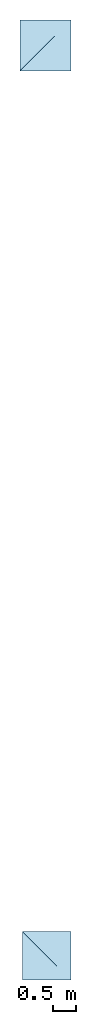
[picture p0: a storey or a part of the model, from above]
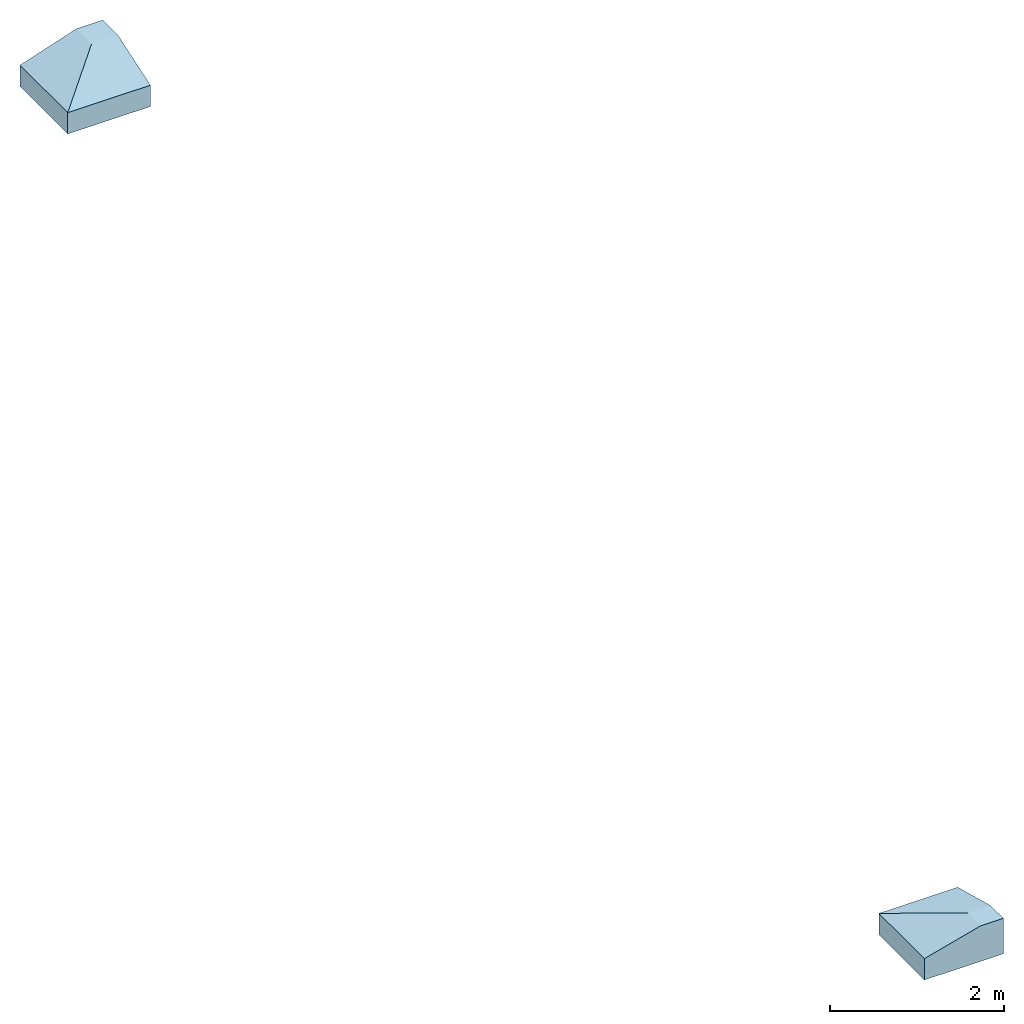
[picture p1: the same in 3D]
Properties of the parts of a building model (IFC4), part 1 of 4

# File
Description: IFC4
Time: 2026-02-24T17:23:19
Made in: IfcPlusPlus

# IfcBuildingStorey (8)
Name | LongName | Elevation (cm)
FUNDAÇÃO | FUNDAÇÃO | -295
FUNDO CISTERNA | FUNDO CISTERNA | -194
TÉRREO | TÉRREO | 10
PAVTO 01 | PAVTO 01 | 302
PAVTO 02 | PAVTO 02 | 604
COB CX DAGUA | COB CX DAGUA | 930
TELHADO CINE | TELHADO CINE | 1054
TELHADO ANEXO | TELHADO ANEXO | 1229

# IfcBeam (600)
Material: Concreto
Pset_ConcreteElementGeneral - ConcreteCover: 2.5 cm; ConstructionMethod: InSitu; ExposureClass: 2; StrengthClass: C-30
AltoQi_Eberick_Elemento - Elemento: Viga; Tipo: retangular
AltoQi_Eberick_Padrão - Ambiente: Interno; Cobrimento: 2.5 cm; Classe de concreto: C-30
AltoQi_Eberick-Itens_associados - Status: Dimensionado
AltoQi_Eberick_Cargas - Solo (S): 0; Acidental (Q): 0; Água (A): 0; Subpressão (AS): 0
Pset_BeamCommon - IsExternal: no; LoadBearing: yes
Name | In | Seção_bw (cm) | Seção_h (cm) | Elevação (cm) | Taxa de armadura | Concreto - C-30 - Abatimento 5 cm (m3) | Forma - Estrutura - Concreto (m2) | Armadura - Aço CA50 - ø 8.0 mm (kg) | Armadura - Aço CA60 - ø 5.0 mm (kg) | Cargas de parede (G2) | Adicional (G2) | Reference | Armadura - Aço CA50 - ø 10.0 mm (kg)
VB1 | TÉRREO | 12 | 30 | 0 | 0.28 % | 0.216781 | 4.33562 | 11.2677 | 5.2136 | 0 | 0 | Viga C-30 - Seção Retangular 12 X 30
VB10 | TÉRREO | 14 | 70 | -44 | 0.16 % | 0.279741 | 4.39592 |  | 3.23503 | 0 | 0 | Viga C-30 - Seção Retangular 14 X 70 | 9.00653 | AltoQi_Eberick-Itens_associados - Armadura - Aço CA50 - ø 6.3 mm: 7.07132 kg
VB10 | TÉRREO | 14 | 70 | -44 | 0.16 % | 0.279731 | 4.39578 |  | 3.23492 | 0 | 0 | Viga C-30 - Seção Retangular 14 X 70 | 9.00623 | AltoQi_Eberick-Itens_associados - Armadura - Aço CA50 - ø 6.3 mm: 7.07109 kg
VB11 | TÉRREO | 14 | 40 | -54 | 0.18 % | 0.040243 | 0.675506 | 1.52886 | 0.619849 | 0 | 0 | Viga C-30 - Seção Retangular 14 X 40
VB11 | TÉRREO | 14 | 40 | -54 | 0.18 % | 0.101426 | 1.70251 | 3.85326 | 1.56223 | 0 | 0 | Viga C-30 - Seção Retangular 14 X 40
VB12 | TÉRREO | 14 | 30 | -24 | 0.24 % | 0.147428 | 2.59755 | 6.66689 | 3.08068 | 408.48 | 0 | Viga C-30 - Seção Retangular 14 X 30
VB13 | TÉRREO | 14 | 30 | -24 | 0.24 % | 0.068809 | 1.21234 | 3.75013 | 1.47337 | 0 | 0 | Viga C-30 - Seção Retangular 14 X 30
VB14 | TÉRREO | 14 | 40 | -24 | 0.44 % | 0.178401 | 2.99458 |  | 2.5517 | 0 | 0 | Viga C-30 - Seção Retangular 14 X 40 | 8.53378 | AltoQi_Eberick-Itens_associados - Armadura - Aço CA50 - ø 12.5 mm: 7.90815 kg
VB14 | TÉRREO | 14 | 40 | -24 | 0.44 % | 0.079776 | 1.3391 |  | 1.14105 | 0 | 0 | Viga C-30 - Seção Retangular 14 X 40 | 3.81609 | AltoQi_Eberick-Itens_associados - Armadura - Aço CA50 - ø 12.5 mm: 3.53633 kg
VB15 | TÉRREO | 14 | 30 | -24 | 0.24 % | 0.07182 | 1.2654 | 3.76749 | 1.60731 | 0 | 0 | Viga C-30 - Seção Retangular 14 X 30
VB16 | TÉRREO | 14 | 40 | -24 | 0.18 % | 0.059025 | 0.990775 | 1.1063 | 0.888222 | 408.48 | 0 | Viga C-30 - Seção Retangular 14 X 40 | 1.80037 | AltoQi_Eberick-Itens_associados - Armadura - Aço CA50 - ø 6.3 mm: 1.31044 kg
VB16 | TÉRREO | 14 | 40 | -24 | 0.18 % | 0.074826 | 1.25601 | 1.40247 | 1.12601 | 0 | 0 | Viga C-30 - Seção Retangular 14 X 40 | 2.28234 | AltoQi_Eberick-Itens_associados - Armadura - Aço CA50 - ø 6.3 mm: 1.66125 kg
VB17 | TÉRREO | 14 | 30 | 21 | 0.24 % | 0.131065 | 2.30924 | 6.1634 | 2.8128 | 0 | 0 | Viga C-30 - Seção Retangular 14 X 30
VB18 | TÉRREO | 14 | 30 | -9 | 0.24 % | 0.154409 | 2.72054 | 7.13566 | 3.34857 | 0 | 0 | Viga C-30 - Seção Retangular 14 X 30
VB19 | TÉRREO | 14 | 50 | -24 | 0.14 % | 0.241591 | 3.93448 | 7.17038 | 2.82467 | 0 | 0 | Viga C-30 - Seção Retangular 14 X 50
VB2 | TÉRREO | 12 | 30 | 0 | 0.28 % | 0.119322 | 2.38644 | 6.49327 | 2.9247 | 0 | 0 | Viga C-30 - Seção Retangular 12 X 30
VB20 | TÉRREO | 14 | 60 | -24 | 0.19 % | 0.340091 | 5.42526 |  | 4.00641 | 0 | 0 | Viga C-30 - Seção Retangular 14 X 60 | 12.8314 | AltoQi_Eberick-Itens_associados - Armadura - Aço CA50 - ø 6.3 mm: 7.2677 kg
VB21 | TÉRREO | 14 | 95 | -24 | 0.18 % | 0.705073 | 10.8147 |  | 7.79581 | 0 | 0 | Viga C-30 - Seção Retangular 14 X 95 | 22.6584 | AltoQi_Eberick-Itens_associados - Armadura - Aço CA50 - ø 6.3 mm: 15.4775 kg
VB22 | TÉRREO | 14 | 40 | -54 | 0.18 % | 0.097296 | 1.63319 | 1.81966 | 1.41684 | 0 | 0 | Viga C-30 - Seção Retangular 14 X 40 | 3.08174 | AltoQi_Eberick-Itens_associados - Armadura - Aço CA50 - ø 6.3 mm: 2.2115 kg
VB22 | TÉRREO | 14 | 40 | -54 | 0.18 % | 0.041024 | 0.688612 | 0.767235 | 0.597391 | 0 | 0 | Viga C-30 - Seção Retangular 14 X 40 | 1.29938 | AltoQi_Eberick-Itens_associados - Armadura - Aço CA50 - ø 6.3 mm: 0.932451 kg
VB23 | TÉRREO | 15 | 30 | -24 | 0.35 % | 0.053107 | 0.857337 |  | 1.08502 | 0 | 0 | Viga C-30 - Seção Retangular 15 X 30 | 4.51755
VB23 | TÉRREO | 15 | 30 | -24 | 0.35 % | 0.054443 | 0.878913 |  | 1.11232 | 408.48 | 0 | Viga C-30 - Seção Retangular 15 X 30 | 4.63125
VB24 | TÉRREO | 15 | 30 | -24 | 0.22 % | 0.080253 | 1.33755 | 1.92715 | 1.648 | 408.48 | 0 | Viga C-30 - Seção Retangular 15 X 30 | 3.22819
VB25 | TÉRREO | 12 | 30 | 22 | 0.28 % | 0.216781 | 4.33562 | 11.1983 | 5.2136 | 0 | 0 | Viga C-30 - Seção Retangular 12 X 30
VB26 | TÉRREO | 12 | 30 | -24 | 0.44 % | 0.124247 | 2.48494 |  | 3.05186 | 0 | 0 | Viga C-30 - Seção Retangular 12 X 30 | 11.3665 | AltoQi_Eberick-Itens_associados - Armadura - Aço CA50 - ø 6.3 mm: 0.436062 kg
VB27 | TÉRREO | 12 | 30 | -24 | 0.44 % | 0.145294 | 2.90588 |  | 3.44934 | 0 | 0 | Viga C-30 - Seção Retangular 12 X 30 | 12.1345 | AltoQi_Eberick-Itens_associados - Armadura - Aço CA50 - ø 6.3 mm: 0.115966 kg
VB27 | TÉRREO | 12 | 30 | -24 | 0.44 % | 0.127877 | 2.55755 |  | 3.03586 | 0 | 0 | Viga C-30 - Seção Retangular 12 X 30 | 10.6799 | AltoQi_Eberick-Itens_associados - Armadura - Aço CA50 - ø 6.3 mm: 0.102065 kg
VB28 | TÉRREO | 12 | 30 | -34 | 0.28 % | 0.152348 | 3.04697 | 9.44476 | 3.68766 | 0 | 0 | Viga C-30 - Seção Retangular 12 X 30 | AltoQi_Eberick-Itens_associados - Armadura - Aço CA50 - ø 6.3 mm: 0.218031 kg
VB29 | TÉRREO | 12 | 30 | -24 | 0.28 % | 0.04334 | 0.841687 | 1.1818 | 1.05117 | 0 | 0 | Viga C-30 - Seção Retangular 12 X 30 | 1.82554
VB29 | TÉRREO | 12 | 30 | -24 | 0.28 % | 0.065104 | 1.26437 | 1.77528 | 1.57906 | 0 | 0 | Viga C-30 - Seção Retangular 12 X 30 | 2.7423
VB29 | TÉRREO | 12 | 30 | -24 | 0.28 % | 0.059326 | 1.15216 | 1.61773 | 1.43892 | 0 | 0 | Viga C-30 - Seção Retangular 12 X 30 | 2.49892
VB3 | TÉRREO | 12 | 30 | -44 | 0.28 % | 0.106154 | 2.12308 | 2.87826 | 2.57784 | 336.6 | 0 | Viga C-30 - Seção Retangular 12 X 30 | 4.39951
VB3 | TÉRREO | 12 | 30 | -44 | 0.28 % | 0.129484 | 2.58969 | 3.51085 | 3.1444 | 336.6 | 0 | Viga C-30 - Seção Retangular 12 X 30 | 5.36644
VB30 | TÉRREO | 12 | 30 | 0 | 0.28 % | 0.158047 | 3.15097 | 8.51487 | 3.81436 | 0 | 0 | Viga C-30 - Seção Retangular 12 X 30
VB30 | TÉRREO | 12 | 30 | 0 | 0.28 % | 0.116451 | 2.32168 | 6.27388 | 2.81048 | 0 | 0 | Viga C-30 - Seção Retangular 12 X 30
VB30 | TÉRREO | 12 | 30 | 0 | 0.28 % | 0.132981 | 2.65124 | 7.16444 | 3.20941 | 0 | 0 | Viga C-30 - Seção Retangular 12 X 30
VB30 | TÉRREO | 12 | 30 | 0 | 0.28 % | 0.151347 | 3.01739 | 8.15388 | 3.65265 | 0 | 0 | Viga C-30 - Seção Retangular 12 X 30
VB30 | TÉRREO | 12 | 30 | 0 | 0.28 % | 0.126128 | 2.5146 | 6.79521 | 3.04401 | 0 | 0 | Viga C-30 - Seção Retangular 12 X 30
VB31 | TÉRREO | 12 | 30 | 0 | 0.28 % | 0.083765 | 1.67529 | 4.86128 | 2.03457 | 0 | 0 | Viga C-30 - Seção Retangular 12 X 30
VB32 | TÉRREO | 12 | 30 | 41 | 0.28 % | 0.097128 | 1.94256 | 5.67727 | 2.2889 | 0 | 0 | Viga C-30 - Seção Retangular 12 X 30
VB33 | TÉRREO | 12 | 30 | 41 | 0.28 % | 0.068903 | 1.37806 | 3.80525 | 1.64145 | 0 | 0 | Viga C-30 - Seção Retangular 12 X 30
VB33 | TÉRREO | 12 | 30 | 41 | 0.28 % | 0.059172 | 1.18344 | 3.26784 | 1.40963 | 0 | 0 | Viga C-30 - Seção Retangular 12 X 30
VB33 | TÉRREO | 12 | 30 | 41 | 0.28 % | 0.068911 | 1.37822 | 3.80569 | 1.64164 | 0 | 0 | Viga C-30 - Seção Retangular 12 X 30
VB33 | TÉRREO | 12 | 30 | 41 | 0.28 % | 0.059229 | 1.18459 | 3.27101 | 1.411 | 0 | 0 | Viga C-30 - Seção Retangular 12 X 30
VB34 | TÉRREO | 15 | 40 | 0 | 0.17 % | 0.17229 | 2.72792 | 6.41949 | 2.39741 | 0 | 0 | Viga C-30 - Seção Retangular 15 X 40
VB35 | TÉRREO | 12 | 30 | -74 | 0.28 % | 0.111625 | 2.23251 | 7.68689 | 2.67038 | 0 | 0 | Viga C-30 - Seção Retangular 12 X 30
VB36 | TÉRREO | 14 | 30 | -54 | 0.24 % | 0.11424 | 2.0128 | 5.46025 | 2.41097 | 0 | 0 | Viga C-30 - Seção Retangular 14 X 30
VB37 | TÉRREO | 14 | 30 | -54 | 0.24 % | 0.11379 | 2.00488 | 5.44289 | 2.41097 | 0 | 0 | Viga C-30 - Seção Retangular 14 X 30
VB38 | TÉRREO | 14 | 40 | -24 | 0.42 % | 0.031679 | 0.546721 |  | 0.458247 | 0 | 0 | Viga C-30 - Seção Retangular 14 X 40 | 2.90532
VB38 | TÉRREO | 14 | 40 | -24 | 0.42 % | 0.107565 | 1.85639 |  | 1.55598 | 0 | 0 | Viga C-30 - Seção Retangular 14 X 40 | 9.86502
VB39 | TÉRREO | 14 | 30 | -24 | 0.36 % | 0.15181 | 2.67476 | 5.31238 | 3.28695 | 0 | 0 | Viga C-30 - Seção Retangular 14 X 30 | 5.49212
VB39 | TÉRREO | 14 | 30 | -24 | 0.36 % | 0.14513 | 2.55705 | 5.0786 | 3.1423 | 0 | 0 | Viga C-30 - Seção Retangular 14 X 30 | 5.25043
VB4 | TÉRREO | 12 | 30 | -54 | 0.28 % | 0.097362 | 1.94724 | 5.81617 | 2.41606 | 336.6 | 0 | Viga C-30 - Seção Retangular 12 X 30
VB40 | TÉRREO | 14 | 40 | -54 | 0.28 % | 0.02033 | 0.34898 |  | 0.295935 | 0 | 0 | Viga C-30 - Seção Retangular 14 X 40 | 1.2228 | AltoQi_Eberick-Itens_associados - Armadura - Aço CA50 - ø 6.3 mm: 0.474256 kg
VB40 | TÉRREO | 14 | 40 | -54 | 0.28 % | 0.152632 | 2.6201 |  | 2.22185 | 0 | 0 | Viga C-30 - Seção Retangular 14 X 40 | 9.18065 | AltoQi_Eberick-Itens_associados - Armadura - Aço CA50 - ø 6.3 mm: 3.56066 kg
VB41 | TÉRREO | 14 | 30 | -24 | 0.56 % | 0.121859 | 2.14704 |  | 2.67886 | 0 | 0 | Viga C-30 - Seção Retangular 14 X 30 | 12.2414
VB42 | TÉRREO | 15 | 30 | -24 | 0.22 % | 0.077861 | 1.29768 | 3.16325 | 1.85838 | 0 | 0 | Viga C-30 - Seção Retangular 15 X 30
VB42 | TÉRREO | 15 | 30 | -24 | 0.22 % | 0.076234 | 1.27056 | 3.09713 | 1.81954 | 0 | 0 | Viga C-30 - Seção Retangular 15 X 30
2 x VB42 | TÉRREO | 15 | 30 | -24 | 0.22 % |  | 0.058454 | 0.142489 | 0.083711 | 0 | 0 | Viga C-30 - Seção Retangular 15 X 30
VB43 | TÉRREO | 14 | 40 | -24 | 0.18 % | 0.257692 | 4.32554 | 8.47539 | 3.65879 | 408.48 | 0 | Viga C-30 - Seção Retangular 14 X 40
VB43 | TÉRREO | 14 | 40 | -24 | 0.18 % | 0.250654 | 4.20741 | 8.24393 | 3.55886 | 408.48 | 0 | Viga C-30 - Seção Retangular 14 X 40
VB44 | TÉRREO | 12 | 30 | -24 | 0.28 % | 0.0594 | 1.188 | 3.4463 | 1.39877 | 0 | 0 | Viga C-30 - Seção Retangular 12 X 30
VB45 | TÉRREO | 12 | 30 | -24 | 0.44 % | 0.112687 | 2.25374 |  | 2.67038 | 135.3 | 0 | Viga C-30 - Seção Retangular 12 X 30 | 10.2
VB46 | TÉRREO | 12 | 30 | -24 | 0.44 % | 0.105919 | 2.1075 |  | 2.57972 | 303.6 | 0 | Viga C-30 - Seção Retangular 12 X 30 | 9.91784
VB46 | TÉRREO | 12 | 30 | -24 | 0.44 % | 0.030916 | 0.615149 |  | 0.752985 | 303.6 | 0 | Viga C-30 - Seção Retangular 12 X 30 | 2.89488
VB46 | TÉRREO | 12 | 30 | -24 | 0.44 % | 0.123378 | 2.4549 |  | 3.00497 | 303.6 | 0 | Viga C-30 - Seção Retangular 12 X 30 | 11.5527
VB46 | TÉRREO | 12 | 30 | -24 | 0.44 % | 0.082068 | 1.63292 |  | 1.99881 | 303.6 | 0 | Viga C-30 - Seção Retangular 12 X 30 | 7.68451
VB46 | TÉRREO | 12 | 30 | -24 | 0.44 % | 0.069417 | 1.38122 |  | 1.6907 | 303.6 | 0 | Viga C-30 - Seção Retangular 12 X 30 | 6.49997
VB46 | TÉRREO | 12 | 30 | -24 | 0.44 % | 0.079075 | 1.57339 |  | 1.92593 | 303.6 | 0 | Viga C-30 - Seção Retangular 12 X 30 | 7.40433
VB5 | TÉRREO | 12 | 30 | -24 | 0.28 % | 0.164811 | 3.29623 | 4.45672 | 3.94664 | 303.6 | 0 | Viga C-30 - Seção Retangular 12 X 30 | 6.91101
VB5 | TÉRREO | 12 | 30 | -24 | 0.28 % | 0.09008 | 1.80159 | 2.43587 | 2.15708 | 303.6 | 0 | Viga C-30 - Seção Retangular 12 X 30 | 3.77729
VB6 | TÉRREO | 14 | 30 | 0 | 0.24 % | 0.139403 | 2.45615 | 6.30327 | 3.04343 | 0 | 0 | Viga C-30 - Seção Retangular 14 X 30
VB6 | TÉRREO | 14 | 30 | 0 | 0.24 % | 0.142816 | 2.51628 | 6.45758 | 3.11794 | 0 | 0 | Viga C-30 - Seção Retangular 14 X 30
VB7 | TÉRREO | 12 | 30 | 0 | 0.28 % | 0.042192 | 0.84384 | 2.80391 | 1.01729 | 0 | 0 | Viga C-30 - Seção Retangular 12 X 30
VB8 | TÉRREO | 14 | 50 | 0 | 0.14 % | 0.233016 | 3.79483 | 6.96204 | 2.82467 | 0 | 0 | Viga C-30 - Seção Retangular 14 X 50
VB9 | TÉRREO | 14 | 50 | -44 | 0.14 % | 0.254877 | 4.15085 | 7.50025 | 3.02643 | 0 | 0 | Viga C-30 - Seção Retangular 14 X 50
V101 | PAVTO 01 | 15 | 40 | 0 | 0.17 % | 0.361302 | 5.72061 | 11.4587 | 4.96606 | 0 | 0 | Viga C-30 - Seção Retangular 15 X 40
V102 | PAVTO 01 | 15 | 40 | 0 | 0.17 % | 0.199745 | 3.16262 | 6.39469 | 2.74602 | 0 | 0 | Viga C-30 - Seção Retangular 15 X 40
V102 | PAVTO 01 | 15 | 40 | 0 | 0.17 % | 0.198853 | 3.14851 | 6.36615 | 2.73377 | 0 | 0 | Viga C-30 - Seção Retangular 15 X 40
V103 | PAVTO 01 | 15 | 40 | 0 | 0.26 % | 0.149621 | 2.06976 |  | 2.08557 | 224.4 | 0 | Viga C-30 - Seção Retangular 15 X 40 | 8.5023
V103 | PAVTO 01 | 15 | 40 | 0 | 0.26 % | 0.215643 | 2.98306 |  | 3.00584 | 224.4 | 0 | Viga C-30 - Seção Retangular 15 X 40 | 12.254
V103 | PAVTO 01 | 15 | 40 | 0 | 0.26 % | 0.275177 | 3.80662 |  | 3.83569 | 224.4 | 0 | Viga C-30 - Seção Retangular 15 X 40 | 15.6371
V103 | PAVTO 01 | 15 | 40 | 0 | 0.26 % | 0.165588 | 2.29063 |  | 2.30812 | 224.4 | 0 | Viga C-30 - Seção Retangular 15 X 40 | 9.4096
V103 | PAVTO 01 | 15 | 40 | 0 | 0.26 % | 0.176788 | 2.44557 |  | 2.46425 | 224.4 | 0 | Viga C-30 - Seção Retangular 15 X 40 | 10.0461
V104 | PAVTO 01 | 15 | 40 | 0 | 0.17 % | 0.171791 | 2.53504 | 2.77229 | 2.41004 | 0 | 0 | Viga C-30 - Seção Retangular 15 X 40 | 4.53598
V104 | PAVTO 01 | 15 | 40 | 0 | 0.17 % | 0.202725 | 2.99152 | 3.27149 | 2.84402 | 0 | 0 | Viga C-30 - Seção Retangular 15 X 40 | 5.35276
V104 | PAVTO 01 | 15 | 40 | 0 | 0.17 % | 0.197635 | 2.91642 | 3.18936 | 2.77262 | 0 | 0 | Viga C-30 - Seção Retangular 15 X 40 | 5.21838
V104 | PAVTO 01 | 15 | 40 | 0 | 0.17 % | 0.198617 | 2.9309 | 3.2052 | 2.78639 | 0 | 0 | Viga C-30 - Seção Retangular 15 X 40 | 5.2443
V104 | PAVTO 01 | 15 | 40 | 0 | 0.17 % | 0.171762 | 2.53461 | 2.77183 | 2.40964 | 0 | 0 | Viga C-30 - Seção Retangular 15 X 40 | 4.53522
V104 | PAVTO 01 | 15 | 40 | 0 | 0.17 % | 0.21602 | 3.18771 | 3.48604 | 3.03053 | 0 | 0 | Viga C-30 - Seção Retangular 15 X 40 | 5.70381
V104 | PAVTO 01 | 15 | 40 | 0 | 0.17 % | 0.042757 | 0.630947 | 0.689997 | 0.599838 | 0 | 0 | Viga C-30 - Seção Retangular 15 X 40 | 1.12896
V104 | PAVTO 01 | 15 | 40 | 0 | 0.17 % | 0.10478 | 1.54618 | 1.69089 | 1.46995 | 0 | 0 | Viga C-30 - Seção Retangular 15 X 40 | 2.76661
V105 | PAVTO 01 | 15 | 35 | 0 | 0.70 % | 0.244666 | 2.84278 |  | 4.16579 | 0 | 0 | Viga C-30 - Seção Retangular 15 X 35 | AltoQi_Eberick-Itens_associados - Armadura - Aço CA50 - ø 12.5 mm: 14.5281 kg; Armadura - Aço CA50 - ø 16.0 mm: 26.6849 kg
V106 | PAVTO 01 | 15 | 40 | 0 | 0.17 % | 0.07032 | 1.1134 | 2.89072 | 1.02746 | 0 | 0 | Viga C-30 - Seção Retangular 15 X 40
V107 | PAVTO 01 | 20 | 40 | 0 | 0.20 % | 0.379976 | 4.7497 |  | 5.26955 | 207.2 | 0 | Viga C-30 - Seção Retangular 20 X 40 | 14.8524
V108 | PAVTO 01 | 15 | 30 | 0 | 0.22 % | 0.073724 | 1.22873 | 1.90979 | 1.648 | 0 | 0 | Viga C-30 - Seção Retangular 15 X 30 | 3.77753
V109 | PAVTO 01 | 15 | 35 | 0 | 0.75 % | 0.244666 | 2.84278 |  | 4.47437 | 0 | 0 | Viga C-30 - Seção Retangular 15 X 35 | 14.8524 | AltoQi_Eberick-Itens_associados - Armadura - Aço CA50 - ø 16.0 mm: 26.2509 kg
V110 | PAVTO 01 | 15 | 35 | 0 | 0.57 % | 0.244666 | 2.84278 | 11.6497 | 4.16579 | 0 | 0 | Viga C-30 - Seção Retangular 15 X 35 | 22.6991
V111 | PAVTO 01 | 15 | 40 | 0 | 0.61 % | 0.147717 | 1.74798 | 1.5977 | 2.04773 | 204.15 | 0 | Viga C-30 - Seção Retangular 15 X 40 | AltoQi_Eberick-Itens_associados - Armadura - Aço CA50 - ø 6.3 mm: 2.84932 kg; Armadura - Aço CA50 - ø 12.5 mm: 7.73517 kg; Armadura - Aço CA50 - ø 16.0 mm: 4.20638 kg
V111 | PAVTO 01 | 15 | 40 | 0 | 0.61 % | 0.136401 | 1.61408 | 1.47532 | 1.89087 | 286 | 0 | Viga C-30 - Seção Retangular 15 X 40 | AltoQi_Eberick-Itens_associados - Armadura - Aço CA50 - ø 6.3 mm: 2.63106 kg; Armadura - Aço CA50 - ø 12.5 mm: 7.14265 kg; Armadura - Aço CA50 - ø 16.0 mm: 3.88417 kg
V112 | PAVTO 01 | 15 | 30 | 0 | 0.22 % | 0.021466 | 0.314424 | 0.525492 | 0.459729 | 0 | 0 | Viga C-30 - Seção Retangular 15 X 30 | 0.862702
V112 | PAVTO 01 | 15 | 30 | 0 | 0.22 % | 0.055484 | 0.8127 | 1.35825 | 1.18827 | 0 | 0 | Viga C-30 - Seção Retangular 15 X 30 | 2.22985
V113 | PAVTO 01 | 15 | 30 | 0 | 0.22 % | 0.044265 | 0.555546 | 0.982881 | 0.893648 | 286 | 0 | Viga C-30 - Seção Retangular 15 X 30 | 1.55046
V113 | PAVTO 01 | 15 | 30 | 0 | 0.22 % | 0.063384 | 0.7955 | 1.40741 | 1.27964 | 0 | 0 | Viga C-30 - Seção Retangular 15 X 30 | 2.22014
V113 | PAVTO 01 | 15 | 30 | 0 | 0.22 % | 0.096426 | 1.2102 | 2.14111 | 1.94673 | 123.2 | 0 | Viga C-30 - Seção Retangular 15 X 30 | 3.37753
V114 | PAVTO 01 | 15 | 40 | 0 | 0.39 % | 0.368802 | 5.10176 |  | 4.96606 | 0 | 0 | Viga C-30 - Seção Retangular 15 X 40 | 11.2444 | AltoQi_Eberick-Itens_associados - Armadura - Aço CA50 - ø 12.5 mm: 17.3045 kg
V115 | PAVTO 01 | 15 | 40 | 0 | 0.26 % | 0.241621 | 3.36514 |  | 3.43732 | 0 | 0 | Viga C-30 - Seção Retangular 15 X 40 | 13.4535 | AltoQi_Eberick-Itens_associados - Armadura - Aço CA50 - ø 6.3 mm: 0.565848 kg
2 x V115 | PAVTO 01 | 15 | 40 | 0 | 0.26 % | 0.086831 | 1.20932 |  | 1.23526 | 0 | 0 | Viga C-30 - Seção Retangular 15 X 40 | 4.83475 | AltoQi_Eberick-Itens_associados - Armadura - Aço CA50 - ø 6.3 mm: 0.203347 kg
V115 | PAVTO 01 | 15 | 40 | 0 | 0.26 % | 0.133791 | 1.86335 |  | 1.90332 | 0 | 0 | Viga C-30 - Seção Retangular 15 X 40 | 7.4495 | AltoQi_Eberick-Itens_associados - Armadura - Aço CA50 - ø 6.3 mm: 0.313322 kg
V115 | PAVTO 01 | 15 | 40 | 0 | 0.26 % | 0.207647 | 2.89198 |  | 2.95401 | 0 | 0 | Viga C-30 - Seção Retangular 15 X 40 | 11.5619 | AltoQi_Eberick-Itens_associados - Armadura - Aço CA50 - ø 6.3 mm: 0.486286 kg
V115 | PAVTO 01 | 15 | 40 | 0 | 0.26 % | 0.188855 | 2.63025 |  | 2.68667 | 0 | 0 | Viga C-30 - Seção Retangular 15 X 40 | 10.5155 | AltoQi_Eberick-Itens_associados - Armadura - Aço CA50 - ø 6.3 mm: 0.442277 kg
V115 | PAVTO 01 | 15 | 40 | 0 | 0.26 % | 0.0779 | 1.08494 |  | 1.10821 | 0 | 0 | Viga C-30 - Seção Retangular 15 X 40 | 4.33748 | AltoQi_Eberick-Itens_associados - Armadura - Aço CA50 - ø 6.3 mm: 0.182432 kg
V115 | PAVTO 01 | 15 | 40 | 0 | 0.26 % | 0.044846 | 0.624583 |  | 0.63798 | 0 | 0 | Viga C-30 - Seção Retangular 15 X 40 | 2.49702 | AltoQi_Eberick-Itens_associados - Armadura - Aço CA50 - ø 6.3 mm: 0.105024 kg
V115 | PAVTO 01 | 15 | 40 | 0 | 0.26 % | 0.22617 | 3.14995 |  | 3.21752 | 0 | 0 | Viga C-30 - Seção Retangular 15 X 40 | 12.5932 | AltoQi_Eberick-Itens_associados - Armadura - Aço CA50 - ø 6.3 mm: 0.529664 kg
V115 | PAVTO 01 | 15 | 40 | 0 | 0.26 % | 0.029608 | 0.41236 |  | 0.421205 | 0 | 0 | Viga C-30 - Seção Retangular 15 X 40 | 1.64858 | AltoQi_Eberick-Itens_associados - Armadura - Aço CA50 - ø 6.3 mm: 0.069338 kg
V116 | PAVTO 01 | 15 | 40 | 0 | 0.26 % | 0.07176 | 1.009 |  | 1.04442 | 387.76 | 0 | Viga C-30 - Seção Retangular 15 X 40 | 3.83779
V116 | PAVTO 01 | 15 | 40 | 0 | 0.26 % | 0.069625 | 0.978974 |  | 1.01334 | 0 | 0 | Viga C-30 - Seção Retangular 15 X 40 | 3.72359
V116 | PAVTO 01 | 15 | 40 | 0 | 0.26 % | 0.129228 | 1.81704 |  | 1.88083 | 123.2 | 0 | Viga C-30 - Seção Retangular 15 X 40 | 6.91122
V117 | PAVTO 01 | 15 | 40 | 0 | 0.17 % | 0.099 | 1.3695 | 3.39421 | 1.1987 | 387.76 | 0 | Viga C-30 - Seção Retangular 15 X 40
V118 | PAVTO 01 | 15 | 40 | 0 | 0.17 % | 0.099 | 1.3695 | 3.39421 | 1.1987 | 387.76 | 0 | Viga C-30 - Seção Retangular 15 X 40
V119 | PAVTO 01 | 15 | 40 | 0 | 0.26 % | 0.056603 | 0.772551 |  | 0.782032 | 0 | 0 | Viga C-30 - Seção Retangular 15 X 40 | 2.89481
V119 | PAVTO 01 | 15 | 40 | 0 | 0.26 % | 0.11278 | 1.5393 |  | 1.55819 | 387.76 | 0 | Viga C-30 - Seção Retangular 15 X 40 | 5.76788
V119 | PAVTO 01 | 15 | 40 | 0 | 0.26 % | 0.016533 | 0.225656 |  | 0.228426 | 0 | 0 | Viga C-30 - Seção Retangular 15 X 40 | 0.845553
V120 | PAVTO 01 | 13 | 30 | 0 | 0.26 % | 0.019781 | 0.309392 | 1.38026 | 0.391655 | 131 | 0 | Viga C-30 - Seção Retangular 13 X 30
V121 | PAVTO 01 | 15 | 40 | 0 | 0.39 % | 0.336717 | 4.69339 |  | 4.62813 | 0 | 0 | Viga C-30 - Seção Retangular 15 X 40 | 23.3729
V121 | PAVTO 01 | 15 | 40 | 0 | 0.39 % | 0.024585 | 0.342688 |  | 0.337923 | 0 | 0 | Viga C-30 - Seção Retangular 15 X 40 | 1.70657
V122 | PAVTO 01 | 15 | 40 | 0 | 0.17 % | 0.086522 | 1.23098 | 1.36317 | 1.20478 | 0 | 0 | Viga C-30 - Seção Retangular 15 X 40 | 2.21202
V122 | PAVTO 01 | 15 | 40 | 0 | 0.17 % | 0.133249 | 1.89577 | 2.09936 | 1.85543 | 0 | 0 | Viga C-30 - Seção Retangular 15 X 40 | 3.40664
V122 | PAVTO 01 | 15 | 40 | 0 | 0.17 % | 0.206909 | 2.94376 | 3.25989 | 2.88112 | 0 | 0 | Viga C-30 - Seção Retangular 15 X 40 | 5.28984
V122 | PAVTO 01 | 15 | 40 | 0 | 0.17 % | 0.188217 | 2.67783 | 2.9654 | 2.62084 | 0 | 0 | Viga C-30 - Seção Retangular 15 X 40 | 4.81197
V123 | PAVTO 01 | 15 | 40 | 0 | 0.17 % | 0.242922 | 3.36042 | 3.95847 | 3.42487 | 0 | 0 | Viga C-30 - Seção Retangular 15 X 40 | 7.67034
V124 | PAVTO 01 | 15 | 40 | 0 | 0.17 % | 0.125743 | 1.88288 | 2.08171 | 1.72372 | 0 | 0 | Viga C-30 - Seção Retangular 15 X 40 | 4.24855
V124 | PAVTO 01 | 15 | 40 | 0 | 0.17 % | 0.086621 | 1.29707 | 1.43403 | 1.18742 | 0 | 0 | Viga C-30 - Seção Retangular 15 X 40 | 2.92671
V125 | PAVTO 01 | 15 | 40 | 0 | 0.17 % | 0.224133 | 3.31704 | 3.53735 | 3.16527 | 0 | 0 | Viga C-30 - Seção Retangular 15 X 40 | 7.07699
V125 | PAVTO 01 | 15 | 40 | 0 | 0.17 % | 0.252968 | 3.74379 | 3.99245 | 3.57249 | 0 | 0 | Viga C-30 - Seção Retangular 15 X 40 | 7.98746
V125 | PAVTO 01 | 15 | 40 | 0 | 0.17 % | 0.056431 | 0.835152 | 0.890622 | 0.796941 | 0 | 0 | Viga C-30 - Seção Retangular 15 X 40 | 1.78182
V126 | PAVTO 01 | 13 | 30 | 0 | 0.26 % | 0.0156 | 0.244 | 1.43234 | 0.522207 | 131 | 0 | Viga C-30 - Seção Retangular 13 X 30
V127 | PAVTO 01 | 15 | 40 | 0 | 0.17 % | 0.251313 | 3.89677 | 4.64188 | 5.31541 | 0 | 0 | Viga C-30 - Seção Retangular 15 X 40 | 6.85729 | AltoQi_Eberick-Itens_associados - Armadura - Aço CA50 - ø 6.3 mm: 0.858037 kg
V127 | PAVTO 01 | 15 | 40 | 0 | 0.17 % | 0.221573 | 3.43564 | 4.09258 | 4.68641 | 0 | 0 | Viga C-30 - Seção Retangular 15 X 40 | 6.04583 | AltoQi_Eberick-Itens_associados - Armadura - Aço CA50 - ø 6.3 mm: 0.756501 kg
V127 | PAVTO 01 | 15 | 40 | 0 | 0.34 % | 0.022159 | 0.343591 | 0.40929 | 0.468678 | 0 | 0 | Viga C-30 - Seção Retangular 15 X 40 | 0.604631 | AltoQi_Eberick-Itens_associados - Armadura - Aço CA50 - ø 6.3 mm: 0.075656 kg
V127 | PAVTO 01 | 15 | 40 | 0 | 0.17 % | 0.263338 | 4.08323 | 4.864 | 5.56976 | 0 | 0 | Viga C-30 - Seção Retangular 15 X 40 | 7.18542 | AltoQi_Eberick-Itens_associados - Armadura - Aço CA50 - ø 6.3 mm: 0.899095 kg
V127 | PAVTO 01 | 15 | 40 | 0 | 0.17 % | 0.210998 | 3.27166 | 3.89724 | 4.46273 | 0 | 0 | Viga C-30 - Seção Retangular 15 X 40 | 5.75726 | AltoQi_Eberick-Itens_associados - Armadura - Aço CA50 - ø 6.3 mm: 0.720393 kg
V127 | PAVTO 01 | 15 | 40 | 0 | 0.34 % | 0.143087 | 2.21866 | 2.64289 | 3.02637 | 0 | 0 | Viga C-30 - Seção Retangular 15 X 40 | 3.90426 | AltoQi_Eberick-Itens_associados - Armadura - Aço CA50 - ø 6.3 mm: 0.48853 kg
V127 | PAVTO 01 | 15 | 40 | 0 | 0.34 % | 0.029122 | 0.451561 | 0.537905 | 0.615955 | 0 | 0 | Viga C-30 - Seção Retangular 15 X 40 | 0.794629 | AltoQi_Eberick-Itens_associados - Armadura - Aço CA50 - ø 6.3 mm: 0.09943 kg
V128 | PAVTO 01 | 20 | 40 | 0 | 0.20 % | 0.186144 | 2.3268 |  | 2.63477 | 207.2 | 0 | Viga C-30 - Seção Retangular 20 X 40 | 8.1383
V129 | PAVTO 01 | 15 | 40 | 0 | 0.17 % | 0.167748 | 1.98502 | 3.17719 | 2.39741 | 0 | 0 | Viga C-30 - Seção Retangular 15 X 40 | 4.74734 | AltoQi_Eberick-Itens_associados - Armadura - Aço CA50 - ø 6.3 mm: 0.360693 kg
V130 | PAVTO 01 | 15 | 30 | 0 | 0.22 % | 0.12141 | 2.0235 | 5.82485 | 2.47201 | 0 | 0 | Viga C-30 - Seção Retangular 15 X 30 | AltoQi_Eberick-Itens_associados - Armadura - Aço CA50 - ø 6.3 mm: 0.279941 kg
V131 | PAVTO 01 | 15 | 40 | 10 | 0.17 % | 0.114838 | 1.81828 | 2.21895 | 1.65786 | 0 | 0 | Viga C-30 - Seção Retangular 15 X 40 | 3.01297 | AltoQi_Eberick-Itens_associados - Armadura - Aço CA50 - ø 6.3 mm: 0.060806 kg
V131 | PAVTO 01 | 15 | 40 | 10 | 0.17 % | 0.098716 | 1.563 | 1.90742 | 1.42511 | 0 | 0 | Viga C-30 - Seção Retangular 15 X 40 | 2.58997 | AltoQi_Eberick-Itens_associados - Armadura - Aço CA50 - ø 6.3 mm: 0.052269 kg
V131 | PAVTO 01 | 15 | 40 | 10 | 0.17 % | 0.09862 | 1.56149 | 1.90557 | 1.42373 | 0 | 0 | Viga C-30 - Seção Retangular 15 X 40 | 2.58746 | AltoQi_Eberick-Itens_associados - Armadura - Aço CA50 - ø 6.3 mm: 0.052218 kg
V131 | PAVTO 01 | 15 | 40 | 10 | 0.25 % | 0.114852 | 1.81849 | 2.21921 | 1.65806 | 0 | 0 | Viga C-30 - Seção Retangular 15 X 40 | 3.01332 | AltoQi_Eberick-Itens_associados - Armadura - Aço CA50 - ø 6.3 mm: 0.060813 kg
V132 | PAVTO 01 | 15 | 40 | 0 | 0.17 % | 0.17229 | 2.72792 | 5.97242 | 2.39741 | 0 | 0 | Viga C-30 - Seção Retangular 15 X 40
V133 | PAVTO 01 | 15 | 40 | 0 | 0.17 % | 0.088739 | 1.1058 | 3.02973 | 1.24513 | 387.76 | 0 | Viga C-30 - Seção Retangular 15 X 40
V133 | PAVTO 01 | 15 | 40 | 0 | 0.17 % | 0.094327 | 1.17543 | 3.22049 | 1.32352 | 0 | 0 | Viga C-30 - Seção Retangular 15 X 40
V134 | PAVTO 01 | 15 | 40 | 0 | 0.17 % | 0.094201 | 1.17386 | 1.67957 | 1.32176 | 0 | 0 | Viga C-30 - Seção Retangular 15 X 40 | 2.64527
V134 | PAVTO 01 | 15 | 40 | 0 | 0.17 % | 0.088865 | 1.10737 | 1.58443 | 1.24689 | 387.76 | 0 | Viga C-30 - Seção Retangular 15 X 40 | 2.49542
V135 | PAVTO 01 | 15 | 40 | 0 | 0.25 % | 0.183066 | 2.16628 | 4.896 | 2.56865 | 0 | 0 | Viga C-30 - Seção Retangular 15 X 40 | 4.88298
V136 | PAVTO 01 | 15 | 40 | 0 | 0.17 % | 0.188022 | 2.60097 | 3.50706 | 2.56865 | 275 | 0 | Viga C-30 - Seção Retangular 15 X 40 | 5.26276
V137 | PAVTO 01 | 15 | 40 | 0 | 0.17 % | 0.180042 | 2.1305 | 3.3074 | 2.56865 | 0 | 0 | Viga C-30 - Seção Retangular 15 X 40 | 5.18138
V138 | PAVTO 01 | 15 | 40 | 0 | 0.17 % | 0.088865 | 1.10737 | 1.58443 | 1.24689 | 387.76 | 0 | Viga C-30 - Seção Retangular 15 X 40 | 2.43617
V138 | PAVTO 01 | 15 | 40 | 0 | 0.17 % | 0.094201 | 1.17386 | 1.67957 | 1.32176 | 0 | 0 | Viga C-30 - Seção Retangular 15 X 40 | 2.58245
V139 | PAVTO 01 | 15 | 40 | 0 | 0.17 % | 0.096088 | 1.20713 | 3.26492 | 1.38135 | 387.76 | 0 | Viga C-30 - Seção Retangular 15 X 40
V139 | PAVTO 01 | 15 | 40 | 0 | 0.17 % | 0.094501 | 1.18719 | 3.21099 | 1.35854 | 0 | 0 | Viga C-30 - Seção Retangular 15 X 40
V140 | PAVTO 01 | 15 | 40 | 0 | 0.26 % | 0.186042 | 2.2015 |  | 2.56865 | 0 | 0 | Viga C-30 - Seção Retangular 15 X 40 | 11.7395
V141 | PAVTO 01 | 15 | 40 | 0 | 0.17 % | 0.180042 | 2.1305 | 3.22059 | 2.56865 | 0 | 0 | Viga C-30 - Seção Retangular 15 X 40 | 6.09016
V142 | PAVTO 01 | 15 | 30 | 0 | 0.22 % | 0.120023 | 1.7245 | 5.28575 | 2.3824 | 0 | 0 | Viga C-30 - Seção Retangular 15 X 30
V142 | PAVTO 01 | 15 | 30 | 0 | 0.22 % | 0.018352 | 0.263682 | 0.808211 | 0.364278 | 0 | 0 | Viga C-30 - Seção Retangular 15 X 30
V143 | PAVTO 01 | 15 | 30 | 0 | 0.22 % | 0.137862 | 2.2977 | 6.07659 | 2.74668 | 0 | 0 | Viga C-30 - Seção Retangular 15 X 30
V144 | PAVTO 01 | 15 | 30 | 0 | 0.22 % | 0.019098 | 0.274051 | 0.815033 | 0.378178 | 0 | 0 | Viga C-30 - Seção Retangular 15 X 30
V144 | PAVTO 01 | 15 | 30 | 0 | 0.22 % | 0.126545 | 1.81587 | 5.40046 | 2.50583 | 0 | 0 | Viga C-30 - Seção Retangular 15 X 30
V145 | PAVTO 01 | 15 | 40 | 0 | 0.26 % | 0.037163 | 0.488802 |  | 0.59811 | 0 | 0 | Viga C-30 - Seção Retangular 15 X 40 | 2.06595 | AltoQi_Eberick-Itens_associados - Armadura - Aço CA50 - ø 6.3 mm: 0.252246 kg
V145 | PAVTO 01 | 15 | 40 | 0 | 0.26 % | 0.204296 | 2.68707 |  | 3.28796 | 0 | 0 | Viga C-30 - Seção Retangular 15 X 40 | 11.3571 | AltoQi_Eberick-Itens_associados - Armadura - Aço CA50 - ø 6.3 mm: 1.38666 kg
V145 | PAVTO 01 | 15 | 40 | 0 | 0.26 % | 0.079191 | 1.04158 |  | 1.2745 | 0 | 0 | Viga C-30 - Seção Retangular 15 X 40 | 4.40229 | AltoQi_Eberick-Itens_associados - Armadura - Aço CA50 - ø 6.3 mm: 0.537506 kg
V145 | PAVTO 01 | 15 | 40 | 0 | 0.26 % | 0.119414 | 1.57063 |  | 1.92186 | 288.2 | 0 | Viga C-30 - Seção Retangular 15 X 40 | 6.63838 | AltoQi_Eberick-Itens_associados - Armadura - Aço CA50 - ø 6.3 mm: 0.810524 kg
V145 | PAVTO 01 | 15 | 40 | 0 | 0.26 % | 0.085595 | 1.12581 |  | 1.37757 | 0 | 0 | Viga C-30 - Seção Retangular 15 X 40 | 4.7583 | AltoQi_Eberick-Itens_associados - Armadura - Aço CA50 - ø 6.3 mm: 0.580973 kg
V145 | PAVTO 01 | 15 | 40 | 0 | 0.26 % | 0.134568 | 1.76995 |  | 2.16574 | 0 | 0 | Viga C-30 - Seção Retangular 15 X 40 | 7.48078 | AltoQi_Eberick-Itens_associados - Armadura - Aço CA50 - ø 6.3 mm: 0.913379 kg
V145 | PAVTO 01 | 15 | 40 | 0 | 0.26 % | 0.13053 | 1.71684 |  | 2.10077 | 0 | 0 | Viga C-30 - Seção Retangular 15 X 40 | 7.25634 | AltoQi_Eberick-Itens_associados - Armadura - Aço CA50 - ø 6.3 mm: 0.885974 kg
V145 | PAVTO 01 | 15 | 40 | 0 | 0.26 % | 0.098077 | 1.28999 |  | 1.57846 | 0 | 0 | Viga C-30 - Seção Retangular 15 X 40 | 5.45223 | AltoQi_Eberick-Itens_associados - Armadura - Aço CA50 - ø 6.3 mm: 0.665699 kg
V145 | PAVTO 01 | 15 | 40 | 0 | 0.26 % | 0.181581 | 2.38829 |  | 2.92237 | 0 | 0 | Viga C-30 - Seção Retangular 15 X 40 | 10.0943 | AltoQi_Eberick-Itens_associados - Armadura - Aço CA50 - ø 6.3 mm: 1.23248 kg
V145 | PAVTO 01 | 15 | 40 | 0 | 0.26 % | 0.05744 | 0.755502 |  | 0.924449 | 0 | 0 | Viga C-30 - Seção Retangular 15 X 40 | 3.19318 | AltoQi_Eberick-Itens_associados - Armadura - Aço CA50 - ø 6.3 mm: 0.389876 kg
V146 | PAVTO 01 | 15 | 40 | 0 | 0.17 % | 0.0945 | 1.13543 | 3.39737 | 1.30768 | 0 | 0 | Viga C-30 - Seção Retangular 15 X 40
V146 | PAVTO 01 | 15 | 40 | 0 | 0.17 % |  | 0.054068 | 0.161779 | 0.06227 | 0 | 0 | Viga C-30 - Seção Retangular 15 X 40
2 x V147 | PAVTO 01 | 15 | 40 | 0 | 0.17 % |  | 0.059254 | 0.159456 | 0.057716 | 0 | 0 | Viga C-30 - Seção Retangular 15 X 40
V147 | PAVTO 01 | 15 | 40 | 0 | 0.17 % | 0.106054 | 1.28794 | 3.46594 | 1.25451 | 0 | 0 | Viga C-30 - Seção Retangular 15 X 40
V148 | PAVTO 01 | 15 | 30 | 0 | 0.22 % | 0.088896 | 1.12826 | 1.95861 | 1.96527 | 183.67 | 0 | Viga C-30 - Seção Retangular 15 X 30 | 4.45462
V148 | PAVTO 01 | 15 | 30 | 0 | 0.22 % | 0.097467 | 1.23703 | 2.14743 | 2.15474 | 132.56 | 0 | Viga C-30 - Seção Retangular 15 X 30 | 4.88408
V149 | PAVTO 01 | 15 | 40 | 0 | 0.17 % | 0.207082 | 2.92066 | 3.36997 | 2.92414 | 288.2 | 0 | Viga C-30 - Seção Retangular 15 X 40 | 5.27437 | AltoQi_Eberick-Itens_associados - Armadura - Aço CA50 - ø 6.3 mm: 0.048873 kg
V149 | PAVTO 01 | 15 | 40 | 0 | 0.17 % | 0.184057 | 2.59591 | 2.99526 | 2.599 | 288.2 | 0 | Viga C-30 - Seção Retangular 15 X 40 | 4.68791 | AltoQi_Eberick-Itens_associados - Armadura - Aço CA50 - ø 6.3 mm: 0.043439 kg
V149 | PAVTO 01 | 15 | 40 | 0 | 0.17 % | 0.130682 | 1.84312 | 2.12666 | 1.84531 | 288.2 | 0 | Viga C-30 - Seção Retangular 15 X 40 | 3.32845 | AltoQi_Eberick-Itens_associados - Armadura - Aço CA50 - ø 6.3 mm: 0.030842 kg
V149 | PAVTO 01 | 15 | 40 | 0 | 0.17 % | 0.181975 | 2.56655 | 2.96138 | 2.5696 | 288.2 | 0 | Viga C-30 - Seção Retangular 15 X 40 | 4.63488 | AltoQi_Eberick-Itens_associados - Armadura - Aço CA50 - ø 6.3 mm: 0.042948 kg
V149 | PAVTO 01 | 15 | 40 | 0 | 0.17 % | 0.137738 | 1.94263 | 2.24148 | 1.94495 | 288.2 | 0 | Viga C-30 - Seção Retangular 15 X 40 | 3.50817 | AltoQi_Eberick-Itens_associados - Armadura - Aço CA50 - ø 6.3 mm: 0.032507 kg
V149 | PAVTO 01 | 15 | 40 | 0 | 0.17 % | 0.116511 | 1.64326 | 1.89606 | 1.64522 | 288.2 | 0 | Viga C-30 - Seção Retangular 15 X 40 | 2.96754 | AltoQi_Eberick-Itens_associados - Armadura - Aço CA50 - ø 6.3 mm: 0.027498 kg
V150 | PAVTO 01 | 15 | 30 | 0 | 0.34 % | 0.09315 | 1.5525 | 3.4897 | 1.92267 | 159.5 | 0 | Viga C-30 - Seção Retangular 15 X 30 | 3.55372
V151 | PAVTO 01 | 15 | 30 | 0 | 0.22 % | 0.095409 | 1.59015 | 2.32647 | 2.06001 | 159.5 | 0 | Viga C-30 - Seção Retangular 15 X 30 | 3.55372 | AltoQi_Eberick-Itens_associados - Armadura - Aço CA50 - ø 6.3 mm: 0.199189 kg
V152 | PAVTO 01 | 15 | 30 | 17.65 | 0.22 % | 0.075901 | 0.860217 | 3.68068 | 1.51067 | 0 | 0 | Viga C-30 - Seção Retangular 15 X 30
V153 | PAVTO 01 | 15 | 30 | 119.6 | 0.35 % | 0.094941 | 1.58235 |  | 2.06001 | 28.6 | 0 | Viga C-30 - Seção Retangular 15 X 30 | 7.1617 | AltoQi_Eberick-Itens_associados - Armadura - Aço CA50 - ø 6.3 mm: 0.398378 kg
V154 | PAVTO 01 | 15 | 35 | 17.65 | 0.19 % | 0.080347 | 1.1172 | 1.5382 | 1.31579 | 297 | 0 | Viga C-30 - Seção Retangular 15 X 35 | 2.63479
V154 | PAVTO 01 | 15 | 35 | 17.65 | 0.19 % | 0.089239 | 1.24085 | 1.70844 | 1.46141 | 297 | 0 | Viga C-30 - Seção Retangular 15 X 35 | 2.92638
V201 | PAVTO 02 | 15 | 40 | -2 | 0.82 % | 0.241937 | 3.62296 | 3.96157 | 3.28449 | 0 | 0 | Viga C-30 - Seção Retangular 15 X 40 | AltoQi_Eberick-Itens_associados - Armadura - Aço CA50 - ø 6.3 mm: 4.57177 kg; Armadura - Aço CA50 - ø 12.5 mm: 15.1525 kg
V201 | PAVTO 02 | 15 | 40 | -2 | 0.82 % | 0.123865 | 1.85486 | 2.02822 | 1.68157 | 0 | 0 | Viga C-30 - Seção Retangular 15 X 40 | AltoQi_Eberick-Itens_associados - Armadura - Aço CA50 - ø 6.3 mm: 2.34062 kg; Armadura - Aço CA50 - ø 12.5 mm: 7.75766 kg
V202 | PAVTO 02 | 15 | 40 | 0 | 0.17 % | 0.086673 | 1.21716 | 1.46012 | 1.20629 | 0 | 0 | Viga C-30 - Seção Retangular 15 X 40 | 2.143 | AltoQi_Eberick-Itens_associados - Armadura - Aço CA50 - ø 6.3 mm: 0.578904 kg
V202 | PAVTO 02 | 15 | 40 | 0 | 0.25 % | 0.065424 | 0.918758 | 1.10215 | 0.910551 | 0 | 0 | Viga C-30 - Seção Retangular 15 X 40 | 1.61761 | AltoQi_Eberick-Itens_associados - Armadura - Aço CA50 - ø 6.3 mm: 0.436978 kg
V202 | PAVTO 02 | 15 | 40 | 0 | 0.17 % | 0.117485 | 1.64986 | 1.97919 | 1.63512 | 0 | 0 | Viga C-30 - Seção Retangular 15 X 40 | 2.90482 | AltoQi_Eberick-Itens_associados - Armadura - Aço CA50 - ø 6.3 mm: 0.784702 kg
V202 | PAVTO 02 | 15 | 40 | 0 | 0.17 % | 0.198864 | 2.79266 | 3.35012 | 2.76772 | 0 | 0 | Viga C-30 - Seção Retangular 15 X 40 | 4.91691 | AltoQi_Eberick-Itens_associados - Armadura - Aço CA50 - ø 6.3 mm: 1.32824 kg
V202 | PAVTO 02 | 15 | 40 | 0 | 0.25 % | 0.134451 | 1.88811 | 2.265 | 1.87124 | 0 | 0 | Viga C-30 - Seção Retangular 15 X 40 | 3.3243 | AltoQi_Eberick-Itens_associados - Armadura - Aço CA50 - ø 6.3 mm: 0.898019 kg
V203 | PAVTO 02 | 15 | 40 | 0 | 0.26 % | 0.150685 | 2.08447 |  | 2.11102 | 384.8 | 0 | Viga C-30 - Seção Retangular 15 X 40 | 11.0955
V203 | PAVTO 02 | 15 | 40 | 0 | 0.39 % | 0.277133 | 3.83368 |  | 3.8825 | 404.8 | 0 | Viga C-30 - Seção Retangular 15 X 40 | 20.4065
V204 | PAVTO 02 | 15 | 40 | -2 | 0.26 % | 0.0933 | 1.28021 | 0.88702 | 1.26421 | 384.8 | 0 | Viga C-30 - Seção Retangular 15 X 40 | 2.16657 | AltoQi_Eberick-Itens_associados - Armadura - Aço CA50 - ø 6.3 mm: 0.402858 kg; Armadura - Aço CA50 - ø 16.0 mm: 2.71495 kg
V204 | PAVTO 02 | 15 | 40 | -2 | 0.26 % | 0.21087 | 2.89343 | 2.00478 | 2.85728 | 384.8 | 0 | Viga C-30 - Seção Retangular 15 X 40 | 4.89673 | AltoQi_Eberick-Itens_associados - Armadura - Aço CA50 - ø 6.3 mm: 0.910511 kg; Armadura - Aço CA50 - ø 16.0 mm: 6.13614 kg
V204 | PAVTO 02 | 15 | 40 | -2 | 0.26 % | 0.126 | 1.7289 | 1.1979 | 1.7073 | 384.8 | 0 | Viga C-30 - Seção Retangular 15 X 40 | 2.92592 | AltoQi_Eberick-Itens_associados - Armadura - Aço CA50 - ø 6.3 mm: 0.544053 kg; Armadura - Aço CA50 - ø 16.0 mm: 3.66649 kg
V204 | PAVTO 02 | 15 | 40 | -2 | 0.26 % | 0.125898 | 1.7275 | 1.19694 | 1.70591 | 384.8 | 0 | Viga C-30 - Seção Retangular 15 X 40 | 2.92355 | AltoQi_Eberick-Itens_associados - Armadura - Aço CA50 - ø 6.3 mm: 0.543612 kg; Armadura - Aço CA50 - ø 16.0 mm: 3.66352 kg
V205 | PAVTO 02 | 15 | 50 | 0 | 0.42 % | 0.032179 | 0.428451 |  | 0.400968 | 0 | 0 | Viga C-30 - Seção Retangular 15 X 50 | 1.90969 | AltoQi_Eberick-Itens_associados - Armadura - Aço CA50 - ø 6.3 mm: 0.729396 kg
V205 | PAVTO 02 | 15 | 50 | 0 | 0.42 % | 0.118635 | 1.57956 |  | 1.47824 | 0 | 0 | Viga C-30 - Seção Retangular 15 X 50 | 7.04038 | AltoQi_Eberick-Itens_associados - Armadura - Aço CA50 - ø 6.3 mm: 2.68904 kg
V205 | PAVTO 02 | 15 | 50 | 0 | 0.42 % |  | 0.082551 |  | 0.077256 | 0 | 0 | Viga C-30 - Seção Retangular 15 X 50 | 0.367945 | AltoQi_Eberick-Itens_associados - Armadura - Aço CA50 - ø 6.3 mm: 0.140535 kg
V205 | PAVTO 02 | 15 | 50 | 0 | 0.42 % | 0.303988 | 4.04744 |  | 3.78782 | 0 | 0 | Viga C-30 - Seção Retangular 15 X 50 | 18.0402 | AltoQi_Eberick-Itens_associados - Armadura - Aço CA50 - ø 6.3 mm: 6.89037 kg
V206 | PAVTO 02 | 15 | 40 | 0 | 0.17 % | 0.199023 | 2.75314 | 3.18394 | 2.7896 | 0 | 0 | Viga C-30 - Seção Retangular 15 X 40 | 5.48713
V206 | PAVTO 02 | 15 | 40 | 0 | 0.17 % | 0.204147 | 2.82404 | 3.26593 | 2.86143 | 0 | 0 | Viga C-30 - Seção Retangular 15 X 40 | 5.62843
V207 | PAVTO 02 | 15 | 40 | 0 | 0.26 % | 0.091891 | 1.24989 |  | 1.28436 | 0 | 0 | Viga C-30 - Seção Retangular 15 X 40 | 5.89693
V207 | PAVTO 02 | 15 | 40 | 0 | 0.26 % | 0.164259 | 2.23422 |  | 2.29585 | 0 | 0 | Viga C-30 - Seção Retangular 15 X 40 | 10.541
V207 | PAVTO 02 | 15 | 40 | 0 | 0.26 % | 0.023127 | 0.314569 |  | 0.323245 | 0 | 0 | Viga C-30 - Seção Retangular 15 X 40 | 1.48413
V207 | PAVTO 02 | 15 | 40 | 0 | 0.26 % |  | 0.065322 |  | 0.067123 | 0 | 0 | Viga C-30 - Seção Retangular 15 X 40 | 0.308185
V207 | PAVTO 02 | 15 | 40 | 0 | 0.26 % | 0.071223 | 0.968756 |  | 0.995477 | 0 | 0 | Viga C-30 - Seção Retangular 15 X 40 | 4.57056
V208 | PAVTO 02 | 15 | 40 | 0 | 0.26 % | 0.134352 | 1.94361 |  | 1.84306 | 0 | 0 | Viga C-30 - Seção Retangular 15 X 40 | 7.17152 | AltoQi_Eberick-Itens_associados - Armadura - Aço CA50 - ø 6.3 mm: 2.73774 kg
V208 | PAVTO 02 | 15 | 40 | 0 | 0.26 % | 0.065376 | 0.945754 |  | 0.89683 | 0 | 0 | Viga C-30 - Seção Retangular 15 X 40 | 3.48965 | AltoQi_Eberick-Itens_associados - Armadura - Aço CA50 - ø 6.3 mm: 1.33218 kg
V209 | PAVTO 02 | 15 | 35 | 91 | 0.19 % | 0.1507 | 2.43991 | 5.46868 | 2.51046 | 0 | 0 | Viga C-30 - Seção Retangular 15 X 35
V209 | PAVTO 02 | 15 | 35 | 91 | 0.19 % | 0.1895 | 3.06809 | 6.87665 | 3.1568 | 0 | 0 | Viga C-30 - Seção Retangular 15 X 35
V209 | PAVTO 02 | 15 | 35 | 91 | 0.19 % | 0.150675 | 2.4395 | 5.46777 | 2.51004 | 0 | 0 | Viga C-30 - Seção Retangular 15 X 35
V210 | PAVTO 02 | 15 | 45 | 0 | 0.30 % | 0.174564 | 2.20106 | 12.7937 | 3.85115 | 0 | 0 | Viga C-30 - Seção Retangular 15 X 45 | 1.85555 | AltoQi_Eberick-Itens_associados - Armadura - Aço CA50 - ø 6.3 mm: 1.82507 kg
V210 | PAVTO 02 | 15 | 45 | 0 | 0.15 % | 0.028671 | 0.361513 | 2.1013 | 0.632531 | 0 | 0 | Viga C-30 - Seção Retangular 15 X 45 | 0.304764 | AltoQi_Eberick-Itens_associados - Armadura - Aço CA50 - ø 6.3 mm: 0.299758 kg
V210 | PAVTO 02 | 15 | 45 | 0 | 0.15 % | 0.067558 | 0.851829 | 4.95128 | 1.49043 | 0 | 0 | Viga C-30 - Seção Retangular 15 X 45 | 0.718111 | AltoQi_Eberick-Itens_associados - Armadura - Aço CA50 - ø 6.3 mm: 0.706316 kg
V210 | PAVTO 02 | 15 | 45 | 0 | 0.15 % | 0.046822 | 0.590371 | 3.43155 | 1.03296 | 0 | 0 | Viga C-30 - Seção Retangular 15 X 45 | 0.497697 | AltoQi_Eberick-Itens_associados - Armadura - Aço CA50 - ø 6.3 mm: 0.489522 kg
V210 | PAVTO 02 | 15 | 45 | 0 | 0.30 % | 0.063329 | 0.798515 | 4.64139 | 1.39714 | 0 | 0 | Viga C-30 - Seção Retangular 15 X 45 | 0.673167 | AltoQi_Eberick-Itens_associados - Armadura - Aço CA50 - ø 6.3 mm: 0.66211 kg
V210 | PAVTO 02 | 15 | 45 | 0 | 0.15 % | 0.086087 | 1.08547 | 6.30931 | 1.89922 | 0 | 0 | Viga C-30 - Seção Retangular 15 X 45 | 0.915075 | AltoQi_Eberick-Itens_associados - Armadura - Aço CA50 - ø 6.3 mm: 0.900044 kg
V211 | PAVTO 02 | 20 | 60 | 0 | 0.20 % | 0.140172 | 1.37062 |  | 1.76754 | 0 | 0 | Viga C-30 - Seção Retangular 20 X 60 | AltoQi_Eberick-Itens_associados - Armadura - Aço CA50 - ø 6.3 mm: 2.78226 kg; Armadura - Aço CA50 - ø 12.5 mm: 7.68388 kg
V211 | PAVTO 02 | 20 | 60 | 0 | 0.31 % | 0.190339 | 1.86116 |  | 2.40014 | 0 | 0 | Viga C-30 - Seção Retangular 20 X 60 | AltoQi_Eberick-Itens_associados - Armadura - Aço CA50 - ø 6.3 mm: 3.77802 kg; Armadura - Aço CA50 - ø 12.5 mm: 10.4339 kg
V211 | PAVTO 02 | 20 | 60 | 0 | 0.31 % | 0.056766 | 0.555061 |  | 0.715805 | 0 | 0 | Viga C-30 - Seção Retangular 20 X 60 | AltoQi_Eberick-Itens_associados - Armadura - Aço CA50 - ø 6.3 mm: 1.12674 kg; Armadura - Aço CA50 - ø 12.5 mm: 3.11175 kg
V211 | PAVTO 02 | 20 | 60 | 0 | 0.31 % | 0.323328 | 3.16154 |  | 4.07711 | 0 | 0 | Viga C-30 - Seção Retangular 20 X 60 | AltoQi_Eberick-Itens_associados - Armadura - Aço CA50 - ø 6.3 mm: 6.41771 kg; Armadura - Aço CA50 - ø 12.5 mm: 17.7241 kg
V212 | PAVTO 02 | 15 | 30 | 0 | 0.35 % | 0.018409 | 0.26717 |  | 0.377227 | 0 | 0 | Viga C-30 - Seção Retangular 15 X 30 | 1.50721
V212 | PAVTO 02 | 15 | 30 | 0 | 0.35 % | 0.055314 | 0.80276 |  | 1.13345 | 0 | 0 | Viga C-30 - Seção Retangular 15 X 30 | 4.52869
V213 | PAVTO 02 | 15 | 45 | 0 | 0.23 % | 0.067892 | 0.814702 | 0.679431 | 1.6955 | 0 | 0 | Viga C-30 - Seção Retangular 15 X 45 | 6.69804
V213 | PAVTO 02 | 15 | 45 | 0 | 0.35 % | 0.06367 | 0.764039 | 0.63718 | 1.59007 | 0 | 0 | Viga C-30 - Seção Retangular 15 X 45 | 6.28152
V213 | PAVTO 02 | 15 | 45 | 0 | 0.35 % | 0.175509 | 2.1061 | 1.75641 | 4.38308 | 0 | 0 | Viga C-30 - Seção Retangular 15 X 45 | 17.3152
V214 | PAVTO 02 | 15 | 40 | 0 | 0.41 % | 0.247404 | 2.92761 | 4.05396 | 3.25362 | 408.48 | 0 | Viga C-30 - Seção Retangular 15 X 40 | AltoQi_Eberick-Itens_associados - Armadura - Aço CA50 - ø 12.5 mm: 9.45229 kg
V215 | PAVTO 02 | 15 | 40 | 0 | 0.41 % | 0.02789 | 0.348931 |  | 0.571988 | 0 | 0 | Viga C-30 - Seção Retangular 15 X 40 | AltoQi_Eberick-Itens_associados - Armadura - Aço CA50 - ø 12.5 mm: 3.89348 kg
V215 | PAVTO 02 | 15 | 40 | 0 | 0.41 % | 0.089008 | 1.11356 |  | 1.82542 | 0 | 0 | Viga C-30 - Seção Retangular 15 X 40 | AltoQi_Eberick-Itens_associados - Armadura - Aço CA50 - ø 12.5 mm: 12.4255 kg
V216 | PAVTO 02 | 15 | 50 | 0 | 0.82 % | 0.21715 | 2.63475 | 1.86396 | 3.25959 | 544.64 | 0 | Viga C-30 - Seção Retangular 15 X 50 | 6.52514 | AltoQi_Eberick-Itens_associados - Armadura - Aço CA50 - ø 6.3 mm: 2.11924 kg; Armadura - Aço CA50 - ø 12.5 mm: 15.0695 kg; Armadura - Aço CA50 - ø 20.0 mm: 28.4401 kg
V216 | PAVTO 02 | 15 | 50 | 0 | 0.82 % | 0.022387 | 0.271624 | 0.192161 | 0.33604 | 442.62 | 0 | Viga C-30 - Seção Retangular 15 X 50 | 0.672695 | AltoQi_Eberick-Itens_associados - Armadura - Aço CA50 - ø 6.3 mm: 0.218478 kg; Armadura - Aço CA50 - ø 12.5 mm: 1.55356 kg; Armadura - Aço CA50 - ø 20.0 mm: 2.93196 kg
V216 | PAVTO 02 | 15 | 50 | 0 | 0.82 % | 0.054362 | 0.659594 | 0.466631 | 0.816017 | 544.64 | 0 | Viga C-30 - Seção Retangular 15 X 50 | 1.63353 | AltoQi_Eberick-Itens_associados - Armadura - Aço CA50 - ø 6.3 mm: 0.530538 kg; Armadura - Aço CA50 - ø 12.5 mm: 3.77255 kg; Armadura - Aço CA50 - ø 20.0 mm: 7.11979 kg
V216 | PAVTO 02 | 15 | 50 | 0 | 0.65 % | 0.076241 | 0.925061 | 0.654436 | 1.14444 | 442.62 | 0 | Viga C-30 - Seção Retangular 15 X 50 | 2.29097 | AltoQi_Eberick-Itens_associados - Armadura - Aço CA50 - ø 6.3 mm: 0.744064 kg; Armadura - Aço CA50 - ø 12.5 mm: 5.29089 kg; Armadura - Aço CA50 - ø 20.0 mm: 9.9853 kg
V217 | PAVTO 02 | 20 | 60 | 0 | 0.31 % | 0.199194 | 1.94667 | 1.2414 | 3.55188 | 0 | 0 | Viga C-30 - Seção Retangular 20 X 60 | AltoQi_Eberick-Itens_associados - Armadura - Aço CA50 - ø 6.3 mm: 3.79187 kg; Armadura - Aço CA50 - ø 12.5 mm: 4.82605 kg; Armadura - Aço CA50 - ø 16.0 mm: 5.10458 kg
V217 | PAVTO 02 | 20 | 60 | 0 | 0.31 % | 0.485063 | 4.7404 | 3.02297 | 8.64928 | 0 | 0 | Viga C-30 - Seção Retangular 20 X 60 | AltoQi_Eberick-Itens_associados - Armadura - Aço CA50 - ø 6.3 mm: 9.23368 kg; Armadura - Aço CA50 - ø 12.5 mm: 11.752 kg; Armadura - Aço CA50 - ø 16.0 mm: 12.4303 kg
V217 | PAVTO 02 | 20 | 60 | 0 | 0.31 % | 0.062347 | 0.609305 | 0.388557 | 1.11173 | 0 | 0 | Viga C-30 - Seção Retangular 20 X 60 | AltoQi_Eberick-Itens_associados - Armadura - Aço CA50 - ø 6.3 mm: 1.18685 kg; Armadura - Aço CA50 - ø 12.5 mm: 1.51055 kg; Armadura - Aço CA50 - ø 16.0 mm: 1.59772 kg
V218 | PAVTO 02 | 20 | 50 | 0 | 0.40 % | 0.050264 | 0.489205 | 0.965954 | 0.673021 | 0 | 0 | Viga C-30 - Seção Retangular 20 X 50 | AltoQi_Eberick-Itens_associados - Armadura - Aço CA50 - ø 6.3 mm: 0.029227 kg; Armadura - Aço CA50 - ø 16.0 mm: 5.34417 kg
V218 | PAVTO 02 | 20 | 50 | 0 | 0.40 % | 0.16059 | 1.56296 | 3.08613 | 2.15024 | 0 | 0 | Viga C-30 - Seção Retangular 20 X 50 | AltoQi_Eberick-Itens_associados - Armadura - Aço CA50 - ø 6.3 mm: 0.093378 kg; Armadura - Aço CA50 - ø 16.0 mm: 17.0741 kg
V218 | PAVTO 02 | 20 | 50 | 0 | 0.40 % | 0.386315 | 3.75986 | 7.424 | 5.17261 | 0 | 0 | Viga C-30 - Seção Retangular 20 X 50 | AltoQi_Eberick-Itens_associados - Armadura - Aço CA50 - ø 6.3 mm: 0.22463 kg; Armadura - Aço CA50 - ø 16.0 mm: 41.0735 kg
V219 | PAVTO 02 | 15 | 30 | 0 | 0.22 % | 0.021458 | 0.314301 | 1.70903 | 0.497856 | 0 | 0 | Viga C-30 - Seção Retangular 15 X 30
V219 | PAVTO 02 | 15 | 30 | 0 | 0.22 % | 0.055492 | 0.812799 | 4.41965 | 1.28748 | 0 | 0 | Viga C-30 - Seção Retangular 15 X 30
V220 | PAVTO 02 | 15 | 45 | 0 | 0.22 % | 0.067763 | 0.825933 | 3.27754 | 1.15515 | 0 | 0 | Viga C-30 - Seção Retangular 15 X 45 | 1.85394 | AltoQi_Eberick-Itens_associados - Armadura - Aço CA50 - ø 6.3 mm: 0.602247 kg; Armadura - Aço CA50 - ø 12.5 mm: 0.828925 kg; Armadura - Aço CA50 - ø 16.0 mm: 2.43876 kg
V220 | PAVTO 02 | 15 | 45 | 0 | 0.36 % | 0.047072 | 0.573742 | 2.27677 | 0.802433 | 0 | 0 | Viga C-30 - Seção Retangular 15 X 45 | 1.28785 | AltoQi_Eberick-Itens_associados - Armadura - Aço CA50 - ø 6.3 mm: 0.418356 kg; Armadura - Aço CA50 - ø 12.5 mm: 0.57582 kg; Armadura - Aço CA50 - ø 16.0 mm: 1.6941 kg
V220 | PAVTO 02 | 15 | 45 | 0 | 0.35 % | 0.188031 | 2.29182 | 9.09458 | 3.20533 | 0 | 0 | Viga C-30 - Seção Retangular 15 X 45 | 5.14435 | AltoQi_Eberick-Itens_associados - Armadura - Aço CA50 - ø 6.3 mm: 1.67113 kg; Armadura - Aço CA50 - ø 12.5 mm: 2.30012 kg; Armadura - Aço CA50 - ø 16.0 mm: 6.76711 kg
V220 | PAVTO 02 | 15 | 45 | 0 | 0.36 % | 0.019385 | 0.23627 | 0.937585 | 0.330446 | 0 | 0 | Viga C-30 - Seção Retangular 15 X 45 | 0.530345 | AltoQi_Eberick-Itens_associados - Armadura - Aço CA50 - ø 6.3 mm: 0.172281 kg; Armadura - Aço CA50 - ø 12.5 mm: 0.237125 kg; Armadura - Aço CA50 - ø 16.0 mm: 0.697641 kg
V221 | PAVTO 02 | 15 | 40 | 0 | 0.82 % | 0.247404 | 3.02732 |  | 6.58246 | 138 | 0 | Viga C-30 - Seção Retangular 15 X 40 | 6.12175 | AltoQi_Eberick-Itens_associados - Armadura - Aço CA50 - ø 12.5 mm: 14.4743 kg
V221 | PAVTO 02 | 15 | 40 | 0 | 0.82 % | 0.101598 | 1.24319 |  | 2.70313 | 0 | 0 | Viga C-30 - Seção Retangular 15 X 40 | 2.51394 | AltoQi_Eberick-Itens_associados - Armadura - Aço CA50 - ø 12.5 mm: 5.94395 kg
V221 | PAVTO 02 | 15 | 40 | 0 | 0.82 % | 0.0243 | 0.297344 |  | 0.646528 | 0 | 0 | Viga C-30 - Seção Retangular 15 X 40 | 0.601278 | AltoQi_Eberick-Itens_associados - Armadura - Aço CA50 - ø 12.5 mm: 1.42166 kg
V222 | PAVTO 02 | 15 | 60 | 0 | 0.17 % | 0.2259 | 3.0873 |  | 3.47064 | 444 | 0 | Viga C-30 - Seção Retangular 15 X 60 | 11.7463 | AltoQi_Eberick-Itens_associados - Armadura - Aço CA50 - ø 6.3 mm: 4.87744 kg; Armadura - Aço CA50 - ø 16.0 mm: 17.5527 kg
V223 | PAVTO 02 | 15 | 50 | 0 | 0.20 % | 0.068044 | 0.877289 | 3.75452 | 1.15473 | 0 | 0 | Viga C-30 - Seção Retangular 15 X 50
V223 | PAVTO 02 | 15 | 50 | 0 | 0.20 % | 0.03595 | 0.463502 | 1.98364 | 0.610084 | 408.48 | 0 | Viga C-30 - Seção Retangular 15 X 50
V223 | PAVTO 02 | 15 | 50 | 0 | 0.20 % | 0.01998 | 0.257597 | 1.10243 | 0.339061 | 0 | 0 | Viga C-30 - Seção Retangular 15 X 50
V223 | PAVTO 02 | 15 | 50 | 0 | 0.20 % | 0.154509 | 1.99208 | 8.52548 | 2.62207 | 296 | 0 | Viga C-30 - Seção Retangular 15 X 50
V223 | PAVTO 02 | 15 | 50 | 0 | 0.20 % | 0.048517 | 0.625531 | 2.67707 | 0.823353 | 408.48 | 0 | Viga C-30 - Seção Retangular 15 X 50
V224 | PAVTO 02 | 15 | 40 | 0 | 0.82 % | 0.094727 | 1.28845 |  | 1.30744 | 0 | 0 | Viga C-30 - Seção Retangular 15 X 40 | AltoQi_Eberick-Itens_associados - Armadura - Aço CA50 - ø 12.5 mm: 10.2249 kg
V224 | PAVTO 02 | 15 | 40 | 0 | 0.82 % |  | 0.059713 |  | 0.060593 | 408.48 | 0 | Viga C-30 - Seção Retangular 15 X 40 | AltoQi_Eberick-Itens_associados - Armadura - Aço CA50 - ø 12.5 mm: 0.473871 kg
V224 | PAVTO 02 | 15 | 40 | 0 | 0.82 % | 0.236978 | 3.2233 |  | 3.27081 | 0 | 0 | Viga C-30 - Seção Retangular 15 X 40 | AltoQi_Eberick-Itens_associados - Armadura - Aço CA50 - ø 12.5 mm: 25.5794 kg
V224 | PAVTO 02 | 15 | 40 | 0 | 0.82 % | 0.023707 | 0.322451 |  | 0.327204 | 0 | 0 | Viga C-30 - Seção Retangular 15 X 40 | AltoQi_Eberick-Itens_associados - Armadura - Aço CA50 - ø 12.5 mm: 2.5589 kg
V225 | PAVTO 02 | 15 | 40 | 0 | 0.41 % | 0.095444 | 1.28617 |  | 1.2852 | 0 | 0 | Viga C-30 - Seção Retangular 15 X 40 | AltoQi_Eberick-Itens_associados - Armadura - Aço CA50 - ø 12.5 mm: 8.63853 kg
V225 | PAVTO 02 | 15 | 40 | 0 | 0.41 % | 0.025743 | 0.346908 |  | 0.346646 | 0 | 0 | Viga C-30 - Seção Retangular 15 X 40 | AltoQi_Eberick-Itens_associados - Armadura - Aço CA50 - ø 12.5 mm: 2.33001 kg
V225 | PAVTO 02 | 15 | 40 | 0 | 0.41 % |  | 0.059607 |  | 0.059562 | 0 | 0 | Viga C-30 - Seção Retangular 15 X 40 | AltoQi_Eberick-Itens_associados - Armadura - Aço CA50 - ø 12.5 mm: 0.400352 kg
V225 | PAVTO 02 | 15 | 40 | 0 | 0.41 % | 0.243191 | 3.27713 |  | 3.27465 | 0 | 0 | Viga C-30 - Seção Retangular 15 X 40 | AltoQi_Eberick-Itens_associados - Armadura - Aço CA50 - ø 12.5 mm: 22.0108 kg
V226 | PAVTO 02 | 15 | 60 | 0 | 0.17 % | 0.041484 | 0.553326 |  | 0.494359 | 0 | 0 | Viga C-30 - Seção Retangular 15 X 60 | 0.72526 | AltoQi_Eberick-Itens_associados - Armadura - Aço CA50 - ø 6.3 mm: 0.851639 kg; Armadura - Aço CA50 - ø 12.5 mm: 1.23965 kg
V226 | PAVTO 02 | 15 | 60 | 0 | 0.17 % | 0.23937 | 3.19276 |  | 2.85251 | 0 | 0 | Viga C-30 - Seção Retangular 15 X 60 | 4.18485 | AltoQi_Eberick-Itens_associados - Armadura - Aço CA50 - ø 6.3 mm: 4.91407 kg; Armadura - Aço CA50 - ø 12.5 mm: 7.15296 kg
V227 | PAVTO 02 | 15 | 40 | 0 | 0.26 % | 0.04491 | 0.626169 |  | 0.629113 | 0 | 0 | Viga C-30 - Seção Retangular 15 X 40 | 2.47546 | AltoQi_Eberick-Itens_associados - Armadura - Aço CA50 - ø 6.3 mm: 0.122495 kg
V227 | PAVTO 02 | 15 | 40 | 0 | 0.26 % | 0.226492 | 3.15795 |  | 3.1728 | 0 | 0 | Viga C-30 - Seção Retangular 15 X 40 | 12.4845 | AltoQi_Eberick-Itens_associados - Armadura - Aço CA50 - ø 6.3 mm: 0.617777 kg
V227 | PAVTO 02 | 15 | 40 | 0 | 0.26 % | 0.207943 | 2.89932 |  | 2.91295 | 0 | 0 | Viga C-30 - Seção Retangular 15 X 40 | 11.462 | AltoQi_Eberick-Itens_associados - Armadura - Aço CA50 - ø 6.3 mm: 0.567182 kg
V227 | PAVTO 02 | 15 | 40 | 0 | 0.26 % | 0.241965 | 3.37369 |  | 3.38955 | 0 | 0 | Viga C-30 - Seção Retangular 15 X 40 | 13.3374 | AltoQi_Eberick-Itens_associados - Armadura - Aço CA50 - ø 6.3 mm: 0.659981 kg
V227 | PAVTO 02 | 15 | 40 | 0 | 0.26 % | 0.078022 | 1.08785 |  | 1.09297 | 0 | 0 | Viga C-30 - Seção Retangular 15 X 40 | 4.30065 | AltoQi_Eberick-Itens_associados - Armadura - Aço CA50 - ø 6.3 mm: 0.212812 kg
V227 | PAVTO 02 | 15 | 40 | 0 | 0.26 % | 0.029639 | 0.41325 |  | 0.415193 | 0 | 0 | Viga C-30 - Seção Retangular 15 X 40 | 1.63372 | AltoQi_Eberick-Itens_associados - Armadura - Aço CA50 - ø 6.3 mm: 0.080842 kg
2 x V227 | PAVTO 02 | 15 | 40 | 0 | 0.26 % | 0.086954 | 1.21239 |  | 1.21809 | 0 | 0 | Viga C-30 - Seção Retangular 15 X 40 | 4.79301 | AltoQi_Eberick-Itens_associados - Armadura - Aço CA50 - ø 6.3 mm: 0.237175 kg
V227 | PAVTO 02 | 15 | 40 | 0 | 0.26 % | 0.133981 | 1.86808 |  | 1.87687 | 0 | 0 | Viga C-30 - Seção Retangular 15 X 40 | 7.38518 | AltoQi_Eberick-Itens_associados - Armadura - Aço CA50 - ø 6.3 mm: 0.365445 kg
V228 | PAVTO 02 | 15 | 40 | 0 | 0.17 % | 0.026398 | 0.373793 | 1.15371 | 0.625742 | 0 | 0 | Viga C-30 - Seção Retangular 15 X 40
V228 | PAVTO 02 | 15 | 40 | 0 | 0.17 % | 0.053 | 0.750474 | 2.31634 | 1.25632 | 408.48 | 0 | Viga C-30 - Seção Retangular 15 X 40
V228 | PAVTO 02 | 15 | 40 | 0 | 0.17 % | 0.126712 | 1.79425 | 5.53795 | 3.00363 | 296 | 0 | Viga C-30 - Seção Retangular 15 X 40
V228 | PAVTO 02 | 15 | 40 | 0 | 0.17 % | 0.059252 | 0.839013 | 2.58961 | 1.40454 | 0 | 0 | Viga C-30 - Seção Retangular 15 X 40
V229 | PAVTO 02 | 15 | 40 | 0 | 0.17 % | 0.099 | 1.3695 | 3.39421 | 1.1987 | 399.6 | 0 | Viga C-30 - Seção Retangular 15 X 40
V230 | PAVTO 02 | 15 | 40 | 0 | 0.17 % | 0.099 | 1.3695 | 3.39421 | 1.1987 | 399.6 | 0 | Viga C-30 - Seção Retangular 15 X 40
V231 | PAVTO 02 | 15 | 40 | 0 | 0.26 % | 0.056603 | 0.77975 | 0.988448 | 0.782032 | 0 | 0 | Viga C-30 - Seção Retangular 15 X 40 | 1.42469
V231 | PAVTO 02 | 15 | 40 | 0 | 0.26 % | 0.035529 | 0.489438 | 0.620435 | 0.490871 | 408.48 | 0 | Viga C-30 - Seção Retangular 15 X 40 | 0.89426
V231 | PAVTO 02 | 15 | 40 | 0 | 0.26 % | 0.093785 | 1.29196 | 1.63776 | 1.29575 | 408.48 | 0 | Viga C-30 - Seção Retangular 15 X 40 | 2.36057
V232 | PAVTO 02 | 13 | 30 | 0 | 0.26 % | 0.014711 | 0.230092 | 1.38026 | 0.391655 | 135 | 0 | Viga C-30 - Seção Retangular 13 X 30
V233 | PAVTO 02 | 15 | 40 | 0 | 0.39 % | 0.213535 | 3.01318 | 2.06759 | 3.45607 | 0 | 0 | Viga C-30 - Seção Retangular 15 X 40 | 7.8641 | AltoQi_Eberick-Itens_associados - Armadura - Aço CA50 - ø 16.0 mm: 5.33572 kg
V233 | PAVTO 02 | 15 | 40 | 0 | 0.39 % | 0.02435 | 0.343597 | 0.23577 | 0.394101 | 0 | 0 | Viga C-30 - Seção Retangular 15 X 40 | 0.896754 | AltoQi_Eberick-Itens_associados - Armadura - Aço CA50 - ø 16.0 mm: 0.60844 kg
V233 | PAVTO 02 | 15 | 40 | 0 | 0.39 % | 0.123418 | 1.74155 | 1.19502 | 1.99753 | 0 | 0 | Viga C-30 - Seção Retangular 15 X 40 | 4.54526 | AltoQi_Eberick-Itens_associados - Armadura - Aço CA50 - ø 16.0 mm: 3.08392 kg
V234 | PAVTO 02 | 15 | 40 | 0 | 0.17 % | 0.086392 | 1.2464 | 1.38104 | 1.1971 | 0 | 0 | Viga C-30 - Seção Retangular 15 X 40 | 2.60468
V234 | PAVTO 02 | 15 | 40 | 0 | 0.17 % | 0.188156 | 2.7146 | 3.00782 | 2.60722 | 0 | 0 | Viga C-30 - Seção Retangular 15 X 40 | 5.67283
V234 | PAVTO 02 | 15 | 40 | 0 | 0.17 % | 0.133272 | 1.92276 | 2.13045 | 1.84671 | 0 | 0 | Viga C-30 - Seção Retangular 15 X 40 | 4.01809
V235 | PAVTO 02 | 15 | 40 | 0 | 0.17 % | 0.223727 | 3.23664 | 3.46563 | 3.42786 | 0 | 0 | Viga C-30 - Seção Retangular 15 X 40 | 6.48461
V235 | PAVTO 02 | 15 | 40 | 0 | 0.17 % | 0.086991 | 1.2585 | 1.34753 | 1.33285 | 0 | 0 | Viga C-30 - Seção Retangular 15 X 40 | 2.5214
V235 | PAVTO 02 | 15 | 40 | 0 | 0.17 % | 0.208032 | 3.00958 | 3.2225 | 3.18738 | 0 | 0 | Viga C-30 - Seção Retangular 15 X 40 | 6.02968
V235 | PAVTO 02 | 15 | 40 | 0 | 0.17 % | 0.25251 | 3.65305 | 3.91149 | 3.86886 | 0 | 0 | Viga C-30 - Seção Retangular 15 X 40 | 7.31887
V235 | PAVTO 02 | 15 | 40 | 0 | 0.17 % | 0.126237 | 1.82626 | 1.95547 | 1.93416 | 0 | 0 | Viga C-30 - Seção Retangular 15 X 40 | 3.65891
V235 | PAVTO 02 | 15 | 40 | 0 | 0.17 % | 0.056329 | 0.814911 | 0.872563 | 0.863054 | 0 | 0 | Viga C-30 - Seção Retangular 15 X 40 | 1.63267
V235 | PAVTO 02 | 15 | 40 | 0 | 0.17 % | 0.242069 | 3.50199 | 3.74974 | 3.70888 | 0 | 0 | Viga C-30 - Seção Retangular 15 X 40 | 7.01622
V236 | PAVTO 02 | 13 | 30 | 0 | 0.26 % | 0.019554 | 0.305852 | 1.38026 | 0.391655 | 135 | 0 | Viga C-30 - Seção Retangular 13 X 30
V237 | PAVTO 02 | 15 | 60 | 0 | 0.22 % | 0.176559 | 2.40361 | 6.34596 | 4.53543 | 0 | 0 | Viga C-30 - Seção Retangular 15 X 60 | 0.125168 | AltoQi_Eberick-Itens_associados - Armadura - Aço CA50 - ø 6.3 mm: 3.46534 kg
V237 | PAVTO 02 | 15 | 60 | 0 | 0.22 % | 0.261605 | 3.56139 | 9.40271 | 6.72007 | 0 | 0 | Viga C-30 - Seção Retangular 15 X 60 | 0.18546 | AltoQi_Eberick-Itens_associados - Armadura - Aço CA50 - ø 6.3 mm: 5.13454 kg
V237 | PAVTO 02 | 15 | 60 | 0 | 0.22 % | 0.218509 | 2.97469 | 7.85373 | 5.61302 | 0 | 0 | Viga C-30 - Seção Retangular 15 X 60 | 0.154908 | AltoQi_Eberick-Itens_associados - Armadura - Aço CA50 - ø 6.3 mm: 4.28869 kg
V237 | PAVTO 02 | 15 | 60 | 0 | 0.17 % | 0.181103 | 2.46546 | 6.50927 | 4.65214 | 0 | 0 | Viga C-30 - Seção Retangular 15 X 60 | 0.128389 | AltoQi_Eberick-Itens_associados - Armadura - Aço CA50 - ø 6.3 mm: 3.55451 kg
V237 | PAVTO 02 | 15 | 60 | 0 | 0.17 % | 0.151291 | 2.05962 | 5.43778 | 3.88635 | 0 | 0 | Viga C-30 - Seção Retangular 15 X 60 | 0.107255 | AltoQi_Eberick-Itens_associados - Armadura - Aço CA50 - ø 6.3 mm: 2.96941 kg
V237 | PAVTO 02 | 15 | 60 | 0 | 0.22 % | 0.214581 | 2.92123 | 7.71257 | 5.51213 | 0 | 0 | Viga C-30 - Seção Retangular 15 X 60 | 0.152123 | AltoQi_Eberick-Itens_associados - Armadura - Aço CA50 - ø 6.3 mm: 4.2116 kg
V237 | PAVTO 02 | 15 | 60 | 0 | 0.22 % | 0.033231 | 0.452394 | 1.1944 | 0.853634 | 0 | 0 | Viga C-30 - Seção Retangular 15 X 60 | 0.023559 | AltoQi_Eberick-Itens_associados - Armadura - Aço CA50 - ø 6.3 mm: 0.652228 kg
V237 | PAVTO 02 | 15 | 60 | 0 | 0.22 % | 0.216988 | 2.95399 | 7.79906 | 5.57395 | 0 | 0 | Viga C-30 - Seção Retangular 15 X 60 | 0.153829 | AltoQi_Eberick-Itens_associados - Armadura - Aço CA50 - ø 6.3 mm: 4.25883 kg
V237 | PAVTO 02 | 15 | 60 | 0 | 0.22 % | 0.054821 | 0.746311 | 1.9704 | 1.40823 | 0 | 0 | Viga C-30 - Seção Retangular 15 X 60 | 0.038864 | AltoQi_Eberick-Itens_associados - Armadura - Aço CA50 - ø 6.3 mm: 1.07597 kg
V237 | PAVTO 02 | 15 | 60 | 0 | 0.22 % | 0.043674 | 0.594555 | 1.56973 | 1.12188 | 0 | 0 | Viga C-30 - Seção Retangular 15 X 60 | 0.030962 | AltoQi_Eberick-Itens_associados - Armadura - Aço CA50 - ø 6.3 mm: 0.857183 kg
V237 | PAVTO 02 | 15 | 60 | 0 | 0.22 % | 0.100518 | 1.36841 | 3.61285 | 2.58209 | 0 | 0 | Viga C-30 - Seção Retangular 15 X 60 | 0.07126 | AltoQi_Eberick-Itens_associados - Armadura - Aço CA50 - ø 6.3 mm: 1.97287 kg
V237 | PAVTO 02 | 15 | 60 | 0 | 0.22 % | 0.059505 | 0.810082 | 2.13876 | 1.52856 | 0 | 0 | Viga C-30 - Seção Retangular 15 X 60 | 0.042185 | AltoQi_Eberick-Itens_associados - Armadura - Aço CA50 - ø 6.3 mm: 1.16791 kg
V238 | PAVTO 02 | 15 | 40 | 0 | 0.17 % | 0.168594 | 1.99503 | 5.83353 | 2.39741 | 399.6 | 0 | Viga C-30 - Seção Retangular 15 X 40
V239 | PAVTO 02 | 15 | 40 | 0 | 0.26 % | 0.126273 | 1.49423 |  | 1.71631 | 408.48 | 0 | Viga C-30 - Seção Retangular 15 X 40 | 5.90024 | AltoQi_Eberick-Itens_associados - Armadura - Aço CA50 - ø 6.3 mm: 0.674016 kg; Armadura - Aço CA50 - ø 12.5 mm: 2.04405 kg
V239 | PAVTO 02 | 15 | 40 | 0 | 0.26 % | 0.109923 | 1.30075 |  | 1.49407 | 408.48 | 0 | Viga C-30 - Seção Retangular 15 X 40 | 5.13625 | AltoQi_Eberick-Itens_associados - Armadura - Aço CA50 - ø 6.3 mm: 0.586741 kg; Armadura - Aço CA50 - ø 12.5 mm: 1.77938 kg
V239 | PAVTO 02 | 15 | 40 | 0 | 0.26 % | 0.151336 | 1.79081 |  | 2.05696 | 408.48 | 0 | Viga C-30 - Seção Retangular 15 X 40 | 7.07131 | AltoQi_Eberick-Itens_associados - Armadura - Aço CA50 - ø 6.3 mm: 0.807793 kg; Armadura - Aço CA50 - ø 12.5 mm: 2.44975 kg
V239 | PAVTO 02 | 15 | 40 | 0 | 0.61 % | 0.121576 | 1.43865 |  | 1.65247 | 408.48 | 0 | Viga C-30 - Seção Retangular 15 X 40 | 5.68077 | AltoQi_Eberick-Itens_associados - Armadura - Aço CA50 - ø 6.3 mm: 0.648944 kg; Armadura - Aço CA50 - ø 12.5 mm: 1.96802 kg
V239 | PAVTO 02 | 15 | 40 | 0 | 0.61 % | 0.152368 | 1.80302 |  | 2.07098 | 408.48 | 0 | Viga C-30 - Seção Retangular 15 X 40 | 7.11953 | AltoQi_Eberick-Itens_associados - Armadura - Aço CA50 - ø 6.3 mm: 0.813301 kg; Armadura - Aço CA50 - ø 12.5 mm: 2.46646 kg
V239 | PAVTO 02 | 15 | 40 | 0 | 0.26 % | 0.070105 | 0.829576 |  | 0.952868 | 408.48 | 0 | Viga C-30 - Seção Retangular 15 X 40 | 3.27573 | AltoQi_Eberick-Itens_associados - Armadura - Aço CA50 - ø 6.3 mm: 0.374203 kg; Armadura - Aço CA50 - ø 12.5 mm: 1.13483 kg
V239 | PAVTO 02 | 15 | 40 | 0 | 0.26 % | 0.036947 | 0.43721 |  | 0.502188 | 408.48 | 0 | Viga C-30 - Seção Retangular 15 X 40 | 1.7264 | AltoQi_Eberick-Itens_associados - Armadura - Aço CA50 - ø 6.3 mm: 0.197216 kg; Armadura - Aço CA50 - ø 12.5 mm: 0.598086 kg
V240 | PAVTO 02 | 15 | 40 | -2 | 0.17 % | 0.077031 | 1.12644 | 2.50746 | 1.03915 | 384.8 | 0 | Viga C-30 - Seção Retangular 15 X 40 | AltoQi_Eberick-Itens_associados - Armadura - Aço CA50 - ø 6.3 mm: 1.43741 kg
V240 | PAVTO 02 | 15 | 40 | -2 | 0.17 % | 0.11338 | 1.65799 | 3.69067 | 1.5295 | 384.8 | 0 | Viga C-30 - Seção Retangular 15 X 40 | AltoQi_Eberick-Itens_associados - Armadura - Aço CA50 - ø 6.3 mm: 2.11569 kg
V241 | PAVTO 02 | 15 | 40 | 0 | 0.17 % | 0.170797 | 2.21337 | 11.1531 | 1.10638 | 0 | 0 | Viga C-30 - Seção Retangular 15 X 40 | 4.15011 | AltoQi_Eberick-Itens_associados - Armadura - Aço CA50 - ø 6.3 mm: 8.47688 kg
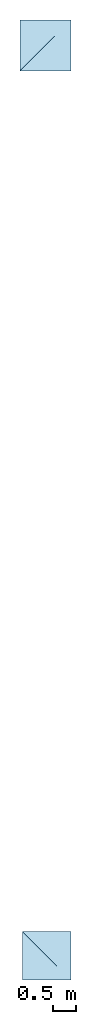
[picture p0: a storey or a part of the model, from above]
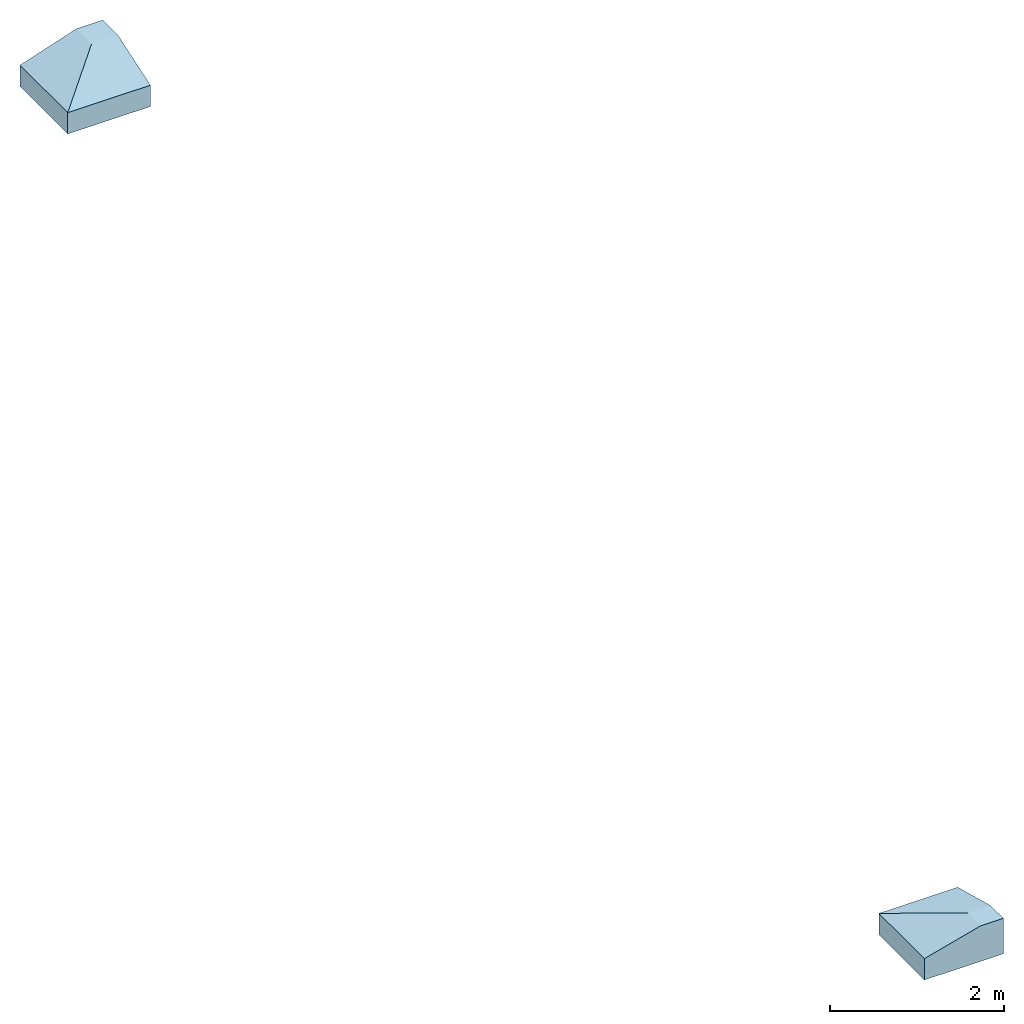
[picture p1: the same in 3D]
Properties of the parts of a building model (IFC4), part 2 of 4

# IfcBeam (600)
Name | In | Seção_bw (cm) | Seção_h (cm) | Elevação (cm) | Taxa de armadura | Concreto - C-30 - Abatimento 5 cm (m3) | Forma - Estrutura - Concreto (m2) | Armadura - Aço CA50 - ø 8.0 mm (kg) | Armadura - Aço CA60 - ø 5.0 mm (kg) | Cargas de parede (G2) | Adicional (G2) | Reference | Armadura - Aço CA50 - ø 10.0 mm (kg)
V241 | PAVTO 02 | 15 | 50 | 0 | 0.40 % | 0.028188 | 0.365294 | 1.84071 | 0.182597 | 0 | 0 | Viga C-30 - Seção Retangular 15 X 50 | 0.684934 | AltoQi_Eberick-Itens_associados - Armadura - Aço CA50 - ø 6.3 mm: 1.39902 kg
V241 | PAVTO 02 | 15 | 50 | 0 | 0.40 % | 0.138031 | 1.78874 | 9.01343 | 0.89413 | 0 | 0 | Viga C-30 - Seção Retangular 15 X 50 | 3.35393 | AltoQi_Eberick-Itens_associados - Armadura - Aço CA50 - ø 6.3 mm: 6.85064 kg
V241 | PAVTO 02 | 15 | 50 | 0 | 0.40 % |  | 0.035077 | 0.176751 | 0.017534 | 0 | 0 | Viga C-30 - Seção Retangular 15 X 50 | 0.06577 | AltoQi_Eberick-Itens_associados - Armadura - Aço CA50 - ø 6.3 mm: 0.134339 kg
V241 | PAVTO 02 | 15 | 50 | 0 | 0.40 % | 0.030375 | 0.393631 | 1.9835 | 0.196762 | 0 | 0 | Viga C-30 - Seção Retangular 15 X 50 | 0.738067 | AltoQi_Eberick-Itens_associados - Armadura - Aço CA50 - ø 6.3 mm: 1.50755 kg
V242 | PAVTO 02 | 15 | 50 | 0 | 0.31 % | 0.176051 | 2.69944 |  | 2.85098 | 0 | 0 | Viga C-30 - Seção Retangular 15 X 50 | 5.80453 | AltoQi_Eberick-Itens_associados - Armadura - Aço CA50 - ø 6.3 mm: 4.4228 kg; Armadura - Aço CA50 - ø 12.5 mm: 6.6181 kg
V242 | PAVTO 02 | 15 | 50 | 0 | 0.31 % | 0.039312 | 0.60278 |  | 0.636617 | 0 | 0 | Viga C-30 - Seção Retangular 15 X 50 | 1.29614 | AltoQi_Eberick-Itens_associados - Armadura - Aço CA50 - ø 6.3 mm: 0.987601 kg; Armadura - Aço CA50 - ø 12.5 mm: 1.47781 kg
V243 | PAVTO 02 | 15 | 50 | -2 | 0.33 % | 0.091046 | 1.21989 |  | 1.95434 | 0 | 0 | Viga C-30 - Seção Retangular 15 X 50 | AltoQi_Eberick-Itens_associados - Armadura - Aço CA50 - ø 12.5 mm: 7.25609 kg
V243 | PAVTO 02 | 15 | 50 | -2 | 0.33 % | 0.126421 | 1.69387 |  | 2.71367 | 0 | 0 | Viga C-30 - Seção Retangular 15 X 50 | AltoQi_Eberick-Itens_associados - Armadura - Aço CA50 - ø 12.5 mm: 10.0754 kg
V243 | PAVTO 02 | 15 | 50 | -2 | 0.33 % | 0.021468 | 0.287635 |  | 0.460808 | 0 | 0 | Viga C-30 - Seção Retangular 15 X 50 | AltoQi_Eberick-Itens_associados - Armadura - Aço CA50 - ø 12.5 mm: 1.71089 kg
V244 | PAVTO 02 | 15 | 30 | -2 | 0.22 % | 0.10039 | 1.13776 | 4.52272 | 1.92267 | 384.8 | 0 | Viga C-30 - Seção Retangular 15 X 30
V245 | PAVTO 02 | 15 | 60 | 0 | 0.17 % | 0.043374 | 0.602427 | 1.06231 | 0.511003 | 444 | 0 | Viga C-30 - Seção Retangular 15 X 60 | AltoQi_Eberick-Itens_associados - Armadura - Aço CA50 - ø 6.3 mm: 0.791541 kg
V245 | PAVTO 02 | 15 | 60 | 0 | 0.17 % | 0.240711 | 3.34324 | 5.89539 | 2.83587 | 444 | 0 | Viga C-30 - Seção Retangular 15 X 60 | AltoQi_Eberick-Itens_associados - Armadura - Aço CA50 - ø 6.3 mm: 4.39275 kg
V246 | PAVTO 02 | 15 | 40 | -2 | 0.41 % | 0.072855 | 0.997075 |  | 1.63171 | 0 | 0 | Viga C-30 - Seção Retangular 15 X 40 | 2.41945 | AltoQi_Eberick-Itens_associados - Armadura - Aço CA50 - ø 12.5 mm: 3.13417 kg
V246 | PAVTO 02 | 15 | 40 | -2 | 0.41 % | 0.118293 | 1.61893 |  | 2.64938 | 0 | 0 | Viga C-30 - Seção Retangular 15 X 40 | 3.92842 | AltoQi_Eberick-Itens_associados - Armadura - Aço CA50 - ø 12.5 mm: 5.0889 kg
V247 | PAVTO 02 | 15 | 40 | 0 | 0.17 % | 0.09379 | 1.17227 | 3.19203 | 1.27983 | 399.6 | 0 | Viga C-30 - Seção Retangular 15 X 40
V247 | PAVTO 02 | 15 | 40 | 0 | 0.17 % | 0.094448 | 1.18051 | 3.21444 | 1.28882 | 0 | 0 | Viga C-30 - Seção Retangular 15 X 40
V248 | PAVTO 02 | 15 | 40 | 0 | 0.17 % | 0.088865 | 1.10737 | 1.58443 | 1.24689 | 399.6 | 0 | Viga C-30 - Seção Retangular 15 X 40 | 2.37032
V248 | PAVTO 02 | 15 | 40 | 0 | 0.17 % | 0.094201 | 1.17386 | 1.67957 | 1.32176 | 0 | 0 | Viga C-30 - Seção Retangular 15 X 40 | 2.51265
V249 | PAVTO 02 | 15 | 45 | 0 | 0.35 % | 0.13308 | 1.59696 |  | 1.63055 | 384.8 | 0 | Viga C-30 - Seção Retangular 15 X 45 | 8.29333 | AltoQi_Eberick-Itens_associados - Armadura - Aço CA50 - ø 6.3 mm: 3.73806 kg
V249 | PAVTO 02 | 15 | 45 | 0 | 0.35 % | 0.081962 | 0.983541 |  | 1.00423 | 384.8 | 0 | Viga C-30 - Seção Retangular 15 X 45 | 5.10773 | AltoQi_Eberick-Itens_associados - Armadura - Aço CA50 - ø 6.3 mm: 2.30221 kg
V250 | PAVTO 02 | 15 | 40 | 0 | 0.26 % | 0.218022 | 3.01597 | 3.61991 | 2.91114 | 384.8 | 0 | Viga C-30 - Seção Retangular 15 X 40 | 5.26276
V251 | PAVTO 02 | 15 | 40 | 0 | 0.17 % | 0.183066 | 2.16628 | 6.3891 | 2.56865 | 0 | 0 | Viga C-30 - Seção Retangular 15 X 40
V252 | PAVTO 02 | 15 | 40 | -12 | 0.17 % | 0.182194 | 2.88474 | 6.26244 | 2.49569 | 0 | 0 | Viga C-30 - Seção Retangular 15 X 40
V252 | PAVTO 02 | 15 | 40 | -12 | 0.17 % | 0.017828 | 0.282276 | 0.612789 | 0.244207 | 0 | 0 | Viga C-30 - Seção Retangular 15 X 40
V253 | PAVTO 02 | 15 | 40 | 0 | 0.17 % | 0.088865 | 1.10737 | 1.58443 | 1.24689 | 399.6 | 0 | Viga C-30 - Seção Retangular 15 X 40 | 2.43617
V253 | PAVTO 02 | 15 | 40 | 0 | 0.17 % | 0.094201 | 1.17386 | 1.67957 | 1.32176 | 0 | 0 | Viga C-30 - Seção Retangular 15 X 40 | 2.58245
V254 | PAVTO 02 | 15 | 40 | 0 | 0.17 % | 0.097532 | 1.22621 | 3.30612 | 1.39133 | 399.6 | 0 | Viga C-30 - Seção Retangular 15 X 40
V254 | PAVTO 02 | 15 | 40 | 0 | 0.17 % | 0.094534 | 1.18852 | 3.20451 | 1.34857 | 0 | 0 | Viga C-30 - Seção Retangular 15 X 40
V255 | PAVTO 02 | 15 | 40 | 28 | 0.17 % | 0.180042 | 2.49058 | 3.22059 | 2.56865 | 384.8 | 0 | Viga C-30 - Seção Retangular 15 X 40 | 5.07287
V256 | PAVTO 02 | 15 | 30 | 0 | 0.22 % | 0.018378 | 0.264064 | 0.8278 | 0.364793 | 0 | 0 | Viga C-30 - Seção Retangular 15 X 30
V256 | PAVTO 02 | 15 | 30 | 0 | 0.22 % | 0.119997 | 1.72419 | 5.40505 | 2.38188 | 0 | 0 | Viga C-30 - Seção Retangular 15 X 30
V257 | PAVTO 02 | 15 | 30 | 0 | 0.22 % | 0.017359 | 0.249096 | 0.782466 | 0.345778 | 0 | 0 | Viga C-30 - Seção Retangular 15 X 30
V257 | PAVTO 02 | 15 | 30 | 0 | 0.22 % | 0.120534 | 1.72959 | 5.43302 | 2.4009 | 0 | 0 | Viga C-30 - Seção Retangular 15 X 30
V258 | PAVTO 02 | 15 | 30 | 0 | 0.22 % | 0.126518 | 1.81555 | 5.3993 | 2.5053 | 0 | 0 | Viga C-30 - Seção Retangular 15 X 30
V258 | PAVTO 02 | 15 | 30 | 0 | 0.22 % | 0.019125 | 0.274447 | 0.816185 | 0.378713 | 0 | 0 | Viga C-30 - Seção Retangular 15 X 30
V259 | PAVTO 02 | 15 | 30 | 0 | 0.22 % | 0.018067 | 0.258917 | 0.770388 | 0.357463 | 0 | 0 | Viga C-30 - Seção Retangular 15 X 30
V259 | PAVTO 02 | 15 | 30 | 0 | 0.22 % | 0.127701 | 1.83002 | 5.4451 | 2.52655 | 0 | 0 | Viga C-30 - Seção Retangular 15 X 30
V260 | PAVTO 02 | 15 | 50 | 0 | 0.31 % | 0.076617 | 1.00982 | 1.41014 | 1.21412 | 0 | 0 | Viga C-30 - Seção Retangular 15 X 50 | 2.21217 | AltoQi_Eberick-Itens_associados - Armadura - Aço CA50 - ø 6.3 mm: 0.304998 kg
V260 | PAVTO 02 | 15 | 50 | 0 | 0.20 % | 0.225465 | 2.97167 | 4.14973 | 3.57289 | 0 | 0 | Viga C-30 - Seção Retangular 15 X 50 | 6.5099 | AltoQi_Eberick-Itens_associados - Armadura - Aço CA50 - ø 6.3 mm: 0.897538 kg
V260 | PAVTO 02 | 15 | 40 | 0 | 0.17 % | 0.097424 | 1.28407 | 1.79312 | 1.54386 | 0 | 0 | Viga C-30 - Seção Retangular 15 X 40 | 2.81296 | AltoQi_Eberick-Itens_associados - Armadura - Aço CA50 - ø 6.3 mm: 0.387831 kg
V260 | PAVTO 02 | 15 | 50 | 0 | 0.20 % | 0.219513 | 2.89323 | 4.04019 | 3.47858 | 384.8 | 0 | Viga C-30 - Seção Retangular 15 X 50 | 6.33807 | AltoQi_Eberick-Itens_associados - Armadura - Aço CA50 - ø 6.3 mm: 0.873847 kg
V260 | PAVTO 02 | 15 | 40 | 0 | 0.17 % | 0.085025 | 1.12064 | 1.5649 | 1.34737 | 0 | 0 | Viga C-30 - Seção Retangular 15 X 40 | 2.45494 | AltoQi_Eberick-Itens_associados - Armadura - Aço CA50 - ø 6.3 mm: 0.33847 kg
V260 | PAVTO 02 | 15 | 50 | 0 | 0.20 % | 0.075435 | 0.994246 | 1.3884 | 1.1954 | 0 | 0 | Viga C-30 - Seção Retangular 15 X 50 | 2.17805 | AltoQi_Eberick-Itens_associados - Armadura - Aço CA50 - ø 6.3 mm: 0.300294 kg
V260 | PAVTO 02 | 15 | 50 | 0 | 0.20 % | 0.046145 | 0.608199 | 0.849308 | 0.731248 | 0 | 0 | Viga C-30 - Seção Retangular 15 X 50 | 1.33236 | AltoQi_Eberick-Itens_associados - Armadura - Aço CA50 - ø 6.3 mm: 0.183695 kg
V260 | PAVTO 02 | 15 | 50 | 0 | 0.20 % | 0.089275 | 1.17667 | 1.64314 | 1.41473 | 0 | 0 | Viga C-30 - Seção Retangular 15 X 50 | 2.57768 | AltoQi_Eberick-Itens_associados - Armadura - Aço CA50 - ø 6.3 mm: 0.355391 kg
V260 | PAVTO 02 | 15 | 50 | 0 | 0.20 % | 0.162077 | 2.1362 | 2.98306 | 2.56839 | 0 | 0 | Viga C-30 - Seção Retangular 15 X 50 | 4.67969 | AltoQi_Eberick-Itens_associados - Armadura - Aço CA50 - ø 6.3 mm: 0.645201 kg
V260 | PAVTO 02 | 15 | 50 | 0 | 0.31 % | 0.088099 | 1.16116 | 1.62148 | 1.39608 | 0 | 0 | Viga C-30 - Seção Retangular 15 X 50 | 2.54371 | AltoQi_Eberick-Itens_associados - Armadura - Aço CA50 - ø 6.3 mm: 0.350707 kg
V260 | PAVTO 02 | 15 | 50 | 0 | 0.20 % | 0.189979 | 2.50396 | 3.49661 | 3.01056 | 0 | 0 | Viga C-30 - Seção Retangular 15 X 50 | 5.48533 | AltoQi_Eberick-Itens_associados - Armadura - Aço CA50 - ø 6.3 mm: 0.756277 kg
V261 | PAVTO 02 | 15 | 40 | 0 | 0.17 % |  | 0.054068 | 0.161779 | 0.06227 | 0 | 0 | Viga C-30 - Seção Retangular 15 X 40
V261 | PAVTO 02 | 15 | 40 | 0 | 0.17 % | 0.0945 | 1.13543 | 3.39737 | 1.30768 | 0 | 0 | Viga C-30 - Seção Retangular 15 X 40
V262 | PAVTO 02 | 15 | 30 | 0 | 0.22 % | 0.080109 | 1.12153 | 3.68068 | 1.51067 | 408.48 | 0 | Viga C-30 - Seção Retangular 15 X 30
V263 | PAVTO 02 | 15 | 45 | 0 | 0.15 % | 0.035951 | 0.431408 | 1.37157 | 0.564594 | 408.48 | 0 | Viga C-30 - Seção Retangular 15 X 45 | AltoQi_Eberick-Itens_associados - Armadura - Aço CA50 - ø 6.3 mm: 1.30819 kg
V264 | PAVTO 02 | 15 | 45 | 0 | 0.55 % | 0.077945 | 0.935345 | 1.18354 | 1.3236 | 408.48 | 0 | Viga C-30 - Seção Retangular 15 X 45 | 0.736899 | AltoQi_Eberick-Itens_associados - Armadura - Aço CA50 - ø 12.5 mm: 6.11882 kg; Armadura - Aço CA50 - ø 16.0 mm: 1.25764 kg
V264 | PAVTO 02 | 15 | 45 | 0 | 0.91 % | 0.25993 | 3.11916 | 3.94684 | 4.4139 | 408.48 | 0 | Viga C-30 - Seção Retangular 15 X 45 | 2.45738 | AltoQi_Eberick-Itens_associados - Armadura - Aço CA50 - ø 12.5 mm: 20.4048 kg; Armadura - Aço CA50 - ø 16.0 mm: 4.19393 kg
V265 | PAVTO 02 | 15 | 72 | 0 | 0.15 % | 0.227858 | 3.10141 |  | 2.79754 | 178.36 | 0 | Viga C-30 - Seção Retangular 15 X 72 | 7.75851 | AltoQi_Eberick-Itens_associados - Armadura - Aço CA50 - ø 6.3 mm: 5.82493 kg
V266 | PAVTO 02 | 15 | 50 | 0 | 0.21 % | 0.163553 | 2.3196 |  | 2.81977 | 412.5 | 0 | Viga C-30 - Seção Retangular 15 X 50 | 7.32935 | AltoQi_Eberick-Itens_associados - Armadura - Aço CA50 - ø 6.3 mm: 1.11175 kg
V266 | PAVTO 02 | 15 | 50 | 0 | 0.21 % | 0.172384 | 2.44484 |  | 2.97201 | 404.8 | 0 | Viga C-30 - Seção Retangular 15 X 50 | 7.72508 | AltoQi_Eberick-Itens_associados - Armadura - Aço CA50 - ø 6.3 mm: 1.17178 kg
V266 | PAVTO 02 | 15 | 50 | 0 | 0.31 % | 0.078277 | 1.11017 |  | 1.34956 | 404.8 | 0 | Viga C-30 - Seção Retangular 15 X 50 | 3.50787 | AltoQi_Eberick-Itens_associados - Armadura - Aço CA50 - ø 6.3 mm: 0.532091 kg
V266 | PAVTO 02 | 15 | 50 | 0 | 0.21 % | 0.230354 | 3.26701 |  | 3.97146 | 404.8 | 0 | Viga C-30 - Seção Retangular 15 X 50 | 10.3229 | AltoQi_Eberick-Itens_associados - Armadura - Aço CA50 - ø 6.3 mm: 1.56583 kg
V266 | PAVTO 02 | 15 | 50 | 0 | 0.21 % | 0.227748 | 3.23005 |  | 3.92653 | 404.8 | 0 | Viga C-30 - Seção Retangular 15 X 50 | 10.2061 | AltoQi_Eberick-Itens_associados - Armadura - Aço CA50 - ø 6.3 mm: 1.54812 kg
V266 | PAVTO 02 | 15 | 50 | 0 | 0.21 % | 0.240272 | 3.40768 |  | 4.14246 | 314.6 | 0 | Viga C-30 - Seção Retangular 15 X 50 | 10.7674 | AltoQi_Eberick-Itens_associados - Armadura - Aço CA50 - ø 6.3 mm: 1.63325 kg
V266 | PAVTO 02 | 15 | 50 | 0 | 0.21 % | 0.042705 | 0.605667 |  | 0.736265 | 404.8 | 0 | Viga C-30 - Seção Retangular 15 X 50 | 1.91376 | AltoQi_Eberick-Itens_associados - Armadura - Aço CA50 - ø 6.3 mm: 0.290288 kg
V266 | PAVTO 02 | 15 | 50 | 0 | 0.31 % | 0.181145 | 2.5691 |  | 3.12307 | 404.8 | 0 | Viga C-30 - Seção Retangular 15 X 50 | 8.11772 | AltoQi_Eberick-Itens_associados - Armadura - Aço CA50 - ø 6.3 mm: 1.23134 kg
V266 | PAVTO 02 | 15 | 50 | 0 | 0.21 % | 0.103381 | 1.46621 |  | 1.78236 | 404.8 | 0 | Viga C-30 - Seção Retangular 15 X 50 | 4.63286 | AltoQi_Eberick-Itens_associados - Armadura - Aço CA50 - ø 6.3 mm: 0.702734 kg
V267 | PAVTO 02 | 15 | 60 | 0 | 0.26 % | 0.065681 | 0.963509 |  | 2.20322 | 0 | 0 | Viga C-30 - Seção Retangular 15 X 60 | 3.20944 | AltoQi_Eberick-Itens_associados - Armadura - Aço CA50 - ø 6.3 mm: 1.33613 kg
V267 | PAVTO 02 | 15 | 60 | 0 | 0.26 % | 0.240769 | 3.53199 |  | 8.07647 | 0 | 0 | Viga C-30 - Seção Retangular 15 X 60 | 11.765 | AltoQi_Eberick-Itens_associados - Armadura - Aço CA50 - ø 6.3 mm: 4.89794 kg
V268 | PAVTO 02 | 15 | 30 | 0 | 0.22 % | 0.1287 | 1.8018 | 5.55574 | 2.60934 | 0 | 0 | Viga C-30 - Seção Retangular 15 X 30
V269 | PAVTO 02 | 15 | 60 | 0 | 0.17 % | 0.2394 | 2.9526 |  | 3.47064 | 0 | 0 | Viga C-30 - Seção Retangular 15 X 60 | 8.7351 | AltoQi_Eberick-Itens_associados - Armadura - Aço CA50 - ø 6.3 mm: 4.87744 kg; Armadura - Aço CA50 - ø 12.5 mm: 12.6737 kg
V270 | PAVTO 02 | 15 | 60 | 0 | 0.17 % | 0.22815 | 2.81385 |  | 2.86875 | 0 | 0 | Viga C-30 - Seção Retangular 15 X 60 | 4.21835 | AltoQi_Eberick-Itens_associados - Armadura - Aço CA50 - ø 6.3 mm: 4.87744 kg; Armadura - Aço CA50 - ø 16.0 mm: 21.0424 kg
V271 | PAVTO 02 | 20 | 60 | 0 | 0.20 % | 0.3132 | 3.0276 |  | 4.09628 | 0 | 0 | Viga C-30 - Seção Retangular 20 X 60 | 4.72021 | AltoQi_Eberick-Itens_associados - Armadura - Aço CA50 - ø 6.3 mm: 6.50325 kg; Armadura - Aço CA50 - ø 16.0 mm: 20.8688 kg
V272 | PAVTO 02 | 15 | 60 | 0 | 0.17 % | 0.22815 | 2.81385 |  | 2.86875 | 0 | 0 | Viga C-30 - Seção Retangular 15 X 60 | 4.21835 | AltoQi_Eberick-Itens_associados - Armadura - Aço CA50 - ø 6.3 mm: 4.87744 kg; Armadura - Aço CA50 - ø 12.5 mm: 12.3982 kg
V273 | PAVTO 02 | 15 | 60 | 0 | 0.17 % | 0.2259 | 3.0873 |  | 2.86875 | 44 | 0 | Viga C-30 - Seção Retangular 15 X 60 | 4.21835 | AltoQi_Eberick-Itens_associados - Armadura - Aço CA50 - ø 6.3 mm: 4.87744 kg; Armadura - Aço CA50 - ø 12.5 mm: 12.6737 kg
V274 | PAVTO 02 | 15 | 30 | -30 | 0.22 % | 0.020745 | 0.345757 | 0.931044 | 0.426057 | 0 | 0 | Viga C-30 - Seção Retangular 15 X 30
V274 | PAVTO 02 | 15 | 30 | -30 | 0.22 % | 0.119682 | 1.99469 | 5.37125 | 2.45795 | 0 | 0 | Viga C-30 - Seção Retangular 15 X 30
V275 | PAVTO 02 | 15 | 60 | 0 | 0.17 % | 0.207923 | 2.85326 |  | 2.87521 | 0 | 0 | Viga C-30 - Seção Retangular 15 X 60 | 7.21861 | AltoQi_Eberick-Itens_associados - Armadura - Aço CA50 - ø 6.3 mm: 4.20982 kg
V275 | PAVTO 02 | 15 | 60 | 0 | 0.17 % | 0.046429 | 0.637126 |  | 0.642027 | 0 | 0 | Viga C-30 - Seção Retangular 15 X 60 | 1.6119 | AltoQi_Eberick-Itens_associados - Armadura - Aço CA50 - ø 6.3 mm: 0.940042 kg
V275 | PAVTO 02 | 15 | 60 | 0 | 0.17 % | 0.149018 | 2.04492 |  | 2.06065 | 0 | 0 | Viga C-30 - Seção Retangular 15 X 60 | 5.17356 | AltoQi_Eberick-Itens_associados - Armadura - Aço CA50 - ø 6.3 mm: 3.01716 kg
V275 | PAVTO 02 | 15 | 60 | 0 | 0.17 % | 0.173376 | 2.37918 |  | 2.39749 | 0 | 0 | Viga C-30 - Seção Retangular 15 X 60 | 6.01922 | AltoQi_Eberick-Itens_associados - Armadura - Aço CA50 - ø 6.3 mm: 3.51035 kg
V275 | PAVTO 02 | 15 | 60 | 0 | 0.17 % | 0.173356 | 2.37891 |  | 2.39721 | 0 | 0 | Viga C-30 - Seção Retangular 15 X 60 | 6.01853 | AltoQi_Eberick-Itens_associados - Armadura - Aço CA50 - ø 6.3 mm: 3.50994 kg
V275 | PAVTO 02 | 15 | 60 | 0 | 0.17 % | 0.148873 | 2.04294 |  | 2.05866 | 0 | 0 | Viga C-30 - Seção Retangular 15 X 60 | 5.16855 | AltoQi_Eberick-Itens_associados - Armadura - Aço CA50 - ø 6.3 mm: 3.01424 kg
V276 | PAVTO 02 | 15 | 30 | -30 | 0.22 % | 0.135319 | 2.25533 | 5.53838 | 2.74668 | 77 | 0 | Viga C-30 - Seção Retangular 15 X 30
V277 | PAVTO 02 | 15 | 60 | 0 | 0.17 % | 0.19422 | 2.64731 | 1.55852 | 2.6862 | 370 | 0 | Viga C-30 - Seção Retangular 15 X 60 | 4.58129 | AltoQi_Eberick-Itens_associados - Armadura - Aço CA50 - ø 6.3 mm: 3.50121 kg
V277 | PAVTO 02 | 15 | 60 | 0 | 0.17 % | 0.191949 | 2.61635 | 1.5403 | 2.65479 | 370 | 0 | Viga C-30 - Seção Retangular 15 X 60 | 4.52771 | AltoQi_Eberick-Itens_associados - Armadura - Aço CA50 - ø 6.3 mm: 3.46027 kg
V277 | PAVTO 02 | 15 | 60 | 0 | 0.17 % | 0.058808 | 0.801578 | 0.471905 | 0.813354 | 0 | 0 | Viga C-30 - Seção Retangular 15 X 60 | 1.38717 | AltoQi_Eberick-Itens_associados - Armadura - Aço CA50 - ø 6.3 mm: 1.06013 kg
V277 | PAVTO 02 | 15 | 60 | 0 | 0.17 % | 0.22912 | 3.12301 | 1.83858 | 3.16889 | 370 | 0 | Viga C-30 - Seção Retangular 15 X 60 | 5.40451 | AltoQi_Eberick-Itens_associados - Armadura - Aço CA50 - ø 6.3 mm: 4.13035 kg
V277 | PAVTO 02 | 15 | 60 | 0 | 0.17 % | 0.170586 | 2.32516 | 1.36887 | 2.35932 | 370 | 0 | Viga C-30 - Seção Retangular 15 X 60 | 4.0238 | AltoQi_Eberick-Itens_associados - Armadura - Aço CA50 - ø 6.3 mm: 3.07515 kg
V277 | PAVTO 02 | 15 | 60 | 0 | 0.17 % | 0.133953 | 1.82584 | 1.07491 | 1.85266 | 370 | 0 | Viga C-30 - Seção Retangular 15 X 60 | 3.1597 | AltoQi_Eberick-Itens_associados - Armadura - Aço CA50 - ø 6.3 mm: 2.41477 kg
V277 | PAVTO 02 | 15 | 60 | 0 | 0.17 % | 0.032838 | 0.4476 | 0.263512 | 0.454176 | 370 | 0 | Viga C-30 - Seção Retangular 15 X 60 | 0.774593 | AltoQi_Eberick-Itens_associados - Armadura - Aço CA50 - ø 6.3 mm: 0.591976 kg
V278 | PAVTO 02 | 15 | 30 | 0 | 0.22 % | 0.09315 | 1.5525 | 4.51404 | 1.92267 | 148.5 | 0 | Viga C-30 - Seção Retangular 15 X 30
V279 | PAVTO 02 | 15 | 30 | 0 | 0.22 % | 0.095409 | 1.59015 | 4.65294 | 2.06001 | 148.5 | 0 | Viga C-30 - Seção Retangular 15 X 30
V280 | PAVTO 02 | 15 | 30 | 0 | 0.22 % | 0.145359 | 2.03503 | 7.30059 | 3.02134 | 132 | 0 | Viga C-30 - Seção Retangular 15 X 30
V301 | COB CX DAGUA | 15 | 40 | -26 | 0.17 % | 0.117485 | 1.64484 | 3.75539 | 1.63512 | 0 | 0 | Viga C-30 - Seção Retangular 15 X 40
V301 | COB CX DAGUA | 15 | 40 | -26 | 0.17 % | 0.065424 | 0.915963 | 2.09127 | 0.910551 | 0 | 0 | Viga C-30 - Seção Retangular 15 X 40
V301 | COB CX DAGUA | 15 | 40 | -26 | 0.17 % | 0.086673 | 1.21346 | 2.77049 | 1.20629 | 0 | 0 | Viga C-30 - Seção Retangular 15 X 40
V301 | COB CX DAGUA | 15 | 40 | -26 | 0.17 % | 0.134451 | 1.88237 | 4.2977 | 1.87124 | 0 | 0 | Viga C-30 - Seção Retangular 15 X 40
V301 | COB CX DAGUA | 15 | 40 | -26 | 0.17 % | 0.198864 | 2.78417 | 6.35664 | 2.76772 | 0 | 0 | Viga C-30 - Seção Retangular 15 X 40
V302 | COB CX DAGUA | 15 | 25 | -41 | 0.27 % | 0.092625 | 1.3091 | 5.10434 | 2.52796 | 199.8 | 0 | Viga C-30 - Seção Retangular 15 X 25
V303 | COB CX DAGUA | 15 | 60 | -26 | 0.17 % | 0.30645 | 4.18815 | 10.2087 | 3.58594 | 0 | 0 | Viga C-30 - Seção Retangular 15 X 60 | AltoQi_Eberick-Itens_associados - Armadura - Aço CA50 - ø 6.3 mm: 6.23407 kg
V304 | COB CX DAGUA | 15 | 40 | -26 | 0.17 % | 0.19887 | 2.75103 | 6.63217 | 2.73989 | 0 | 0 | Viga C-30 - Seção Retangular 15 X 40
V305 | COB CX DAGUA | 15 | 50 | 0 | 0.21 % | 0.029641 | 0.401088 |  | 0.34719 | 0 | 0 | Viga C-30 - Seção Retangular 15 X 50 | 1.18746 | AltoQi_Eberick-Itens_associados - Armadura - Aço CA50 - ø 6.3 mm: 0.012965 kg
V305 | COB CX DAGUA | 15 | 50 | 0 | 0.21 % | 0.091282 | 1.2352 |  | 1.06922 | 0 | 0 | Viga C-30 - Seção Retangular 15 X 50 | 3.65695 | AltoQi_Eberick-Itens_associados - Armadura - Aço CA50 - ø 6.3 mm: 0.039928 kg
V305 | COB CX DAGUA | 15 | 50 | 0 | 0.21 % | 0.206387 | 2.79276 |  | 2.41747 | 0 | 0 | Viga C-30 - Seção Retangular 15 X 50 | 8.26827 | AltoQi_Eberick-Itens_associados - Armadura - Aço CA50 - ø 6.3 mm: 0.090277 kg
V305 | COB CX DAGUA | 15 | 50 | 0 | 0.21 % | 0.128068 | 1.73298 |  | 1.5001 | 0 | 0 | Viga C-30 - Seção Retangular 15 X 50 | 5.13066 | AltoQi_Eberick-Itens_associados - Armadura - Aço CA50 - ø 6.3 mm: 0.056019 kg
V306 | COB CX DAGUA | 15 | 40 | -26 | 0.17 % | 0.134352 | 2.02214 | 4.48466 | 1.84306 | 0 | 0 | Viga C-30 - Seção Retangular 15 X 40
V306 | COB CX DAGUA | 15 | 40 | -26 | 0.17 % | 0.065376 | 0.983969 | 2.18223 | 0.89683 | 0 | 0 | Viga C-30 - Seção Retangular 15 X 40
V307 | COB CX DAGUA | 15 | 25 | -41 | 0.27 % | 0.088867 | 1.25599 | 5.03489 | 2.40758 | 0 | 0 | Viga C-30 - Seção Retangular 15 X 25
V308 | COB CX DAGUA | 15 | 50 | 0 | 0.21 % | 0.08761 | 1.00267 |  | 1.09267 | 0 | 0 | Viga C-30 - Seção Retangular 15 X 50 | 2.73987 | AltoQi_Eberick-Itens_associados - Armadura - Aço CA50 - ø 12.5 mm: 4.0323 kg
V308 | COB CX DAGUA | 15 | 50 | 0 | 0.42 % | 0.035516 | 0.406467 |  | 0.442954 | 0 | 0 | Viga C-30 - Seção Retangular 15 X 50 | 1.11071 | AltoQi_Eberick-Itens_associados - Armadura - Aço CA50 - ø 12.5 mm: 1.63464 kg
V308 | COB CX DAGUA | 15 | 50 | 0 | 0.42 % | 0.198085 | 2.267 |  | 2.4705 | 0 | 0 | Viga C-30 - Seção Retangular 15 X 50 | 6.19477 | AltoQi_Eberick-Itens_associados - Armadura - Aço CA50 - ø 12.5 mm: 9.11691 kg
V308 | COB CX DAGUA | 15 | 50 | 0 | 0.42 % | 0.122916 | 1.40673 |  | 1.533 | 0 | 0 | Viga C-30 - Seção Retangular 15 X 50 | 3.84401 | AltoQi_Eberick-Itens_associados - Armadura - Aço CA50 - ø 12.5 mm: 5.65726 kg
V309 | COB CX DAGUA | 12 | 25 | -50 | 0.34 % | 0.0753 | 1.5562 | 2.70843 | 2.53474 | 0 | 0 | Viga C-30 - Seção Retangular 12 X 25 | AltoQi_Eberick-Itens_associados - Armadura - Aço CA50 - ø 12.5 mm: 7.43891 kg
V310 | COB CX DAGUA | 15 | 50 | 0 | 0.49 % | 0.200534 | 2.26653 |  | 2.38825 | 0 | 0 | Viga C-30 - Seção Retangular 15 X 50 | AltoQi_Eberick-Itens_associados - Armadura - Aço CA50 - ø 12.5 mm: 16.2883 kg
V310 | COB CX DAGUA | 15 | 50 | 0 | 0.49 % | 0.209612 | 2.36913 |  | 2.49636 | 0 | 0 | Viga C-30 - Seção Retangular 15 X 50 | AltoQi_Eberick-Itens_associados - Armadura - Aço CA50 - ø 12.5 mm: 17.0256 kg
V310 | COB CX DAGUA | 15 | 50 | 0 | 0.49 % | 0.037731 | 0.426453 |  | 0.449355 | 0 | 0 | Viga C-30 - Seção Retangular 15 X 50 | AltoQi_Eberick-Itens_associados - Armadura - Aço CA50 - ø 12.5 mm: 3.06468 kg
V311 | COB CX DAGUA | 15 | 50 | 0 | 0.65 % | 0.038497 | 0.434856 |  | 0.462561 | 0 | 0 | Viga C-30 - Seção Retangular 15 X 50 | AltoQi_Eberick-Itens_associados - Armadura - Aço CA50 - ø 12.5 mm: 3.96883 kg
V311 | COB CX DAGUA | 15 | 50 | 0 | 0.65 % | 0.204835 | 2.31376 |  | 2.46117 | 0 | 0 | Viga C-30 - Seção Retangular 15 X 50 | AltoQi_Eberick-Itens_associados - Armadura - Aço CA50 - ø 12.5 mm: 21.1172 kg
V311 | COB CX DAGUA | 15 | 50 | 0 | 0.65 % | 0.21767 | 2.45874 |  | 2.61539 | 0 | 0 | Viga C-30 - Seção Retangular 15 X 50 | AltoQi_Eberick-Itens_associados - Armadura - Aço CA50 - ø 12.5 mm: 22.4404 kg
V312 | COB CX DAGUA | 12 | 30 | 0 | 0.28 % | 0.10026 | 2.0052 | 2.70843 | 2.54322 | 0 | 0 | Viga C-30 - Seção Retangular 12 X 30 | AltoQi_Eberick-Itens_associados - Armadura - Aço CA50 - ø 12.5 mm: 7.20578 kg
V313 | COB CX DAGUA | 15 | 50 | 0 | 0.82 % | 0.209596 | 2.36894 |  | 2.59218 | 0 | 0 | Viga C-30 - Seção Retangular 15 X 50 | AltoQi_Eberick-Itens_associados - Armadura - Aço CA50 - ø 12.5 mm: 29.2284 kg
V313 | COB CX DAGUA | 15 | 50 | 0 | 0.82 % | 0.200584 | 2.26708 |  | 2.48072 | 0 | 0 | Viga C-30 - Seção Retangular 15 X 50 | AltoQi_Eberick-Itens_associados - Armadura - Aço CA50 - ø 12.5 mm: 27.9717 kg
V313 | COB CX DAGUA | 15 | 50 | 0 | 0.82 % | 0.037698 | 0.426083 |  | 0.466234 | 0 | 0 | Viga C-30 - Seção Retangular 15 X 50 | AltoQi_Eberick-Itens_associados - Armadura - Aço CA50 - ø 12.5 mm: 5.25709 kg
V314 | COB CX DAGUA | 12 | 25 | 0 | 0.52 % | 0.0753 | 1.5562 |  | 2.53474 | 0 | 0 | Viga C-30 - Seção Retangular 12 X 25 | 4.21835 | AltoQi_Eberick-Itens_associados - Armadura - Aço CA50 - ø 12.5 mm: 11.116 kg
V315 | COB CX DAGUA | 15 | 50 | 0 | 0.63 % | 0.21405 | 2.43844 | 2.90965 | 3.53347 | 0 | 0 | Viga C-30 - Seção Retangular 15 X 50 | 10.1532
V315 | COB CX DAGUA | 15 | 50 | 0 | 0.63 % | 0.227462 | 2.59123 | 3.09197 | 3.75487 | 0 | 0 | Viga C-30 - Seção Retangular 15 X 50 | 10.7893
V315 | COB CX DAGUA | 15 | 50 | 0 | 0.63 % | 0.030741 | 0.350201 | 0.417875 | 0.507466 | 0 | 0 | Viga C-30 - Seção Retangular 15 X 50 | 1.45816
V316 | COB CX DAGUA | 15 | 50 | 0 | 0.42 % | 0.216458 | 2.85846 |  | 2.53544 | 0 | 0 | Viga C-30 - Seção Retangular 15 X 50 | 11.1669
V316 | COB CX DAGUA | 15 | 50 | 0 | 0.42 % | 0.208916 | 2.75886 |  | 2.44709 | 0 | 0 | Viga C-30 - Seção Retangular 15 X 50 | 10.7778
V316 | COB CX DAGUA | 15 | 50 | 0 | 0.42 % | 0.030004 | 0.396219 |  | 0.351444 | 0 | 0 | Viga C-30 - Seção Retangular 15 X 50 | 1.54787
V317 | COB CX DAGUA | 15 | 40 | 0 | 0.17 % | 0.133842 | 2.13357 | 4.26893 | 1.86944 | 0 | 0 | Viga C-30 - Seção Retangular 15 X 40
V317 | COB CX DAGUA | 15 | 40 | 0 | 0.17 % | 0.188928 | 3.0117 | 6.0259 | 2.63885 | 0 | 0 | Viga C-30 - Seção Retangular 15 X 40
V317 | COB CX DAGUA | 15 | 40 | 0 | 0.17 % | 0.207727 | 3.31137 | 6.6255 | 2.90142 | 0 | 0 | Viga C-30 - Seção Retangular 15 X 40
V317 | COB CX DAGUA | 15 | 40 | 0 | 0.17 % | 0.1519 | 2.42143 | 4.84487 | 2.12166 | 0 | 0 | Viga C-30 - Seção Retangular 15 X 40
V317 | COB CX DAGUA | 15 | 40 | 0 | 0.17 % | 0.226257 | 3.60676 | 7.21652 | 3.16024 | 0 | 0 | Viga C-30 - Seção Retangular 15 X 40
2 x V317 | COB CX DAGUA | 15 | 40 | 0 | 0.17 % | 0.086864 | 1.3847 | 2.77055 | 1.21327 | 0 | 0 | Viga C-30 - Seção Retangular 15 X 40
V317 | COB CX DAGUA | 15 | 40 | 0 | 0.17 % | 0.241714 | 3.85316 | 7.70952 | 3.37613 | 0 | 0 | Viga C-30 - Seção Retangular 15 X 40
V318 | COB CX DAGUA | 15 | 40 | 0 | 0.17 % | 0.129238 | 1.78779 | 4.33648 | 1.88098 | 72.52 | 0 | Viga C-30 - Seção Retangular 15 X 40
V318 | COB CX DAGUA | 15 | 40 | 0 | 0.17 % | 0.141374 | 1.95567 | 4.74369 | 2.05761 | 72.52 | 0 | Viga C-30 - Seção Retangular 15 X 40
V319 | COB CX DAGUA | 15 | 40 | 0 | 0.17 % | 0.099 | 1.5675 | 3.39421 | 1.1987 | 229.4 | 0 | Viga C-30 - Seção Retangular 15 X 40
V320 | COB CX DAGUA | 15 | 40 | 0 | 0.17 % | 0.099 | 1.5675 | 3.39421 | 1.1987 | 229.4 | 0 | Viga C-30 - Seção Retangular 15 X 40
V321 | COB CX DAGUA | 15 | 40 | 0 | 0.17 % | 0.133288 | 2.13367 | 4.34085 | 1.84692 | 103.6 | 0 | Viga C-30 - Seção Retangular 15 X 40
V321 | COB CX DAGUA | 15 | 40 | 0 | 0.17 % | 0.086402 | 1.38313 | 2.8139 | 1.19724 | 229.4 | 0 | Viga C-30 - Seção Retangular 15 X 40
V321 | COB CX DAGUA | 15 | 40 | 0 | 0.17 % | 0.18813 | 3.0116 | 6.12695 | 2.60686 | 103.6 | 0 | Viga C-30 - Seção Retangular 15 X 40
V322 | COB CX DAGUA | 15 | 40 | 0 | 0.17 % | 0.208077 | 3.20965 | 6.71299 | 2.91992 | 103.6 | 0 | Viga C-30 - Seção Retangular 15 X 40
V322 | COB CX DAGUA | 15 | 40 | 0 | 0.17 % | 0.242121 | 3.73479 | 7.81133 | 3.39766 | 103.6 | 0 | Viga C-30 - Seção Retangular 15 X 40
V322 | COB CX DAGUA | 15 | 40 | 0 | 0.17 % | 0.126265 | 1.94767 | 4.07356 | 1.77186 | 103.6 | 0 | Viga C-30 - Seção Retangular 15 X 40
V322 | COB CX DAGUA | 15 | 40 | 0 | 0.17 % | 0.279857 | 4.31687 | 9.02875 | 3.92719 | 103.6 | 0 | Viga C-30 - Seção Retangular 15 X 40
V322 | COB CX DAGUA | 15 | 40 | 0 | 0.17 % | 0.252565 | 3.89589 | 8.14827 | 3.54422 | 103.6 | 0 | Viga C-30 - Seção Retangular 15 X 40
V322 | COB CX DAGUA | 15 | 40 | 0 | 0.17 % | 0.08701 | 1.34216 | 2.80713 | 1.22101 | 229.4 | 0 | Viga C-30 - Seção Retangular 15 X 40
V323 | COB CX DAGUA | 15 | 50 | 0 | 0.31 % | 0.188218 | 2.46922 |  | 2.31936 | 0 | 0 | Viga C-30 - Seção Retangular 15 X 50 | 8.29183 | AltoQi_Eberick-Itens_associados - Armadura - Aço CA50 - ø 6.3 mm: 1.65769 kg
V323 | COB CX DAGUA | 15 | 50 | 0 | 0.21 % | 0.150155 | 1.96987 |  | 1.85032 | 0 | 0 | Viga C-30 - Seção Retangular 15 X 50 | 6.61499 | AltoQi_Eberick-Itens_associados - Armadura - Aço CA50 - ø 6.3 mm: 1.32246 kg
V323 | COB CX DAGUA | 15 | 50 | 0 | 0.21 % | 0.125438 | 1.64561 |  | 1.54574 | 0 | 0 | Viga C-30 - Seção Retangular 15 X 50 | 5.5261 | AltoQi_Eberick-Itens_associados - Armadura - Aço CA50 - ø 6.3 mm: 1.10477 kg
V323 | COB CX DAGUA | 15 | 50 | 0 | 0.21 % | 0.13436 | 1.76266 |  | 1.65568 | 0 | 0 | Viga C-30 - Seção Retangular 15 X 50 | 5.91916 | AltoQi_Eberick-Itens_associados - Armadura - Aço CA50 - ø 6.3 mm: 1.18335 kg
V323 | COB CX DAGUA | 15 | 50 | 0 | 0.21 % | 0.178146 | 2.33708 |  | 2.19523 | 0 | 0 | Viga C-30 - Seção Retangular 15 X 50 | 7.84809 | AltoQi_Eberick-Itens_associados - Armadura - Aço CA50 - ø 6.3 mm: 1.56897 kg
V323 | COB CX DAGUA | 15 | 50 | 0 | 0.31 % | 0.139343 | 1.82802 |  | 1.71708 | 0 | 0 | Viga C-30 - Seção Retangular 15 X 50 | 6.13865 | AltoQi_Eberick-Itens_associados - Armadura - Aço CA50 - ø 6.3 mm: 1.22723 kg
V324 | COB CX DAGUA | 15 | 50 | 0 | 0.21 % | 0.15969 | 1.75701 |  | 1.88763 | 0 | 0 | Viga C-30 - Seção Retangular 15 X 50 | 6.65351
V324 | COB CX DAGUA | 15 | 50 | 0 | 0.21 % | 0.139012 | 1.5295 |  | 1.64321 | 0 | 0 | Viga C-30 - Seção Retangular 15 X 50 | 5.79198
V324 | COB CX DAGUA | 15 | 50 | 0 | 0.42 % | 0.20019 | 2.20261 |  | 2.36637 | 0 | 0 | Viga C-30 - Seção Retangular 15 X 50 | 8.34095
V324 | COB CX DAGUA | 15 | 50 | 0 | 0.21 % | 0.18951 | 2.08511 |  | 2.24012 | 0 | 0 | Viga C-30 - Seção Retangular 15 X 50 | 7.89597
V324 | COB CX DAGUA | 15 | 50 | 0 | 0.21 % | 0.137257 | 1.51019 |  | 1.62247 | 0 | 0 | Viga C-30 - Seção Retangular 15 X 50 | 5.71886
V324 | COB CX DAGUA | 15 | 50 | 0 | 0.42 % | 0.14625 | 1.60913 |  | 1.72876 | 0 | 0 | Viga C-30 - Seção Retangular 15 X 50 | 6.09353
V325 | COB CX DAGUA | 15 | 40 | 0 | 0.17 % | 0.176748 | 2.79851 | 6.40647 | 2.56865 | 0 | 0 | Viga C-30 - Seção Retangular 15 X 40
V326 | COB CX DAGUA | 15 | 50 | 0 | 0.20 % | 0.031386 | 0.454491 | 0.668512 | 0.954611 | 0 | 0 | Viga C-30 - Seção Retangular 15 X 50 | 0.746859 | AltoQi_Eberick-Itens_associados - Armadura - Aço CA50 - ø 6.3 mm: 0.804114 kg
V326 | COB CX DAGUA | 15 | 50 | 0 | 0.20 % | 0.133401 | 1.93176 | 2.84144 | 4.05747 | 0 | 0 | Viga C-30 - Seção Retangular 15 X 50 | 3.17444 | AltoQi_Eberick-Itens_associados - Armadura - Aço CA50 - ø 6.3 mm: 3.41779 kg
V326 | COB CX DAGUA | 15 | 50 | 0 | 0.20 % | 0.037563 | 0.543948 | 0.800094 | 1.14251 | 0 | 0 | Viga C-30 - Seção Retangular 15 X 50 | 0.893861 | AltoQi_Eberick-Itens_associados - Armadura - Aço CA50 - ø 6.3 mm: 0.962386 kg
V327 | COB CX DAGUA | 15 | 50 | 0 | 0.21 % | 0.123885 | 1.88531 | 0.254091 | 1.35703 | 0 | 0 | Viga C-30 - Seção Retangular 15 X 50 | 6.62367 | AltoQi_Eberick-Itens_associados - Armadura - Aço CA50 - ø 6.3 mm: 2.93608 kg
V327 | COB CX DAGUA | 15 | 50 | 0 | 0.42 % | 0.025794 | 0.392544 | 0.052905 | 0.282551 | 0 | 0 | Viga C-30 - Seção Retangular 15 X 50 | 1.37913 | AltoQi_Eberick-Itens_associados - Armadura - Aço CA50 - ø 6.3 mm: 0.611326 kg
V327 | COB CX DAGUA | 15 | 50 | 0 | 0.21 % | 0.038598 | 0.587396 | 0.079166 | 0.422804 | 0 | 0 | Viga C-30 - Seção Retangular 15 X 50 | 2.06371 | AltoQi_Eberick-Itens_associados - Armadura - Aço CA50 - ø 6.3 mm: 0.914778 kg
V327 | COB CX DAGUA | 15 | 50 | 0 | 0.21 % | 0.172856 | 2.63055 | 0.35453 | 1.89346 | 0 | 0 | Viga C-30 - Seção Retangular 15 X 50 | 9.24195 | AltoQi_Eberick-Itens_associados - Armadura - Aço CA50 - ø 6.3 mm: 4.09668 kg
V327 | COB CX DAGUA | 15 | 50 | 0 | 0.21 % | 0.144135 | 2.19348 | 0.295624 | 1.57885 | 0 | 0 | Viga C-30 - Seção Retangular 15 X 50 | 7.70638 | AltoQi_Eberick-Itens_associados - Armadura - Aço CA50 - ø 6.3 mm: 3.41601 kg
V327 | COB CX DAGUA | 15 | 50 | 0 | 0.21 % | 0.144119 | 2.19323 | 0.29559 | 1.57867 | 0 | 0 | Viga C-30 - Seção Retangular 15 X 50 | 7.70549 | AltoQi_Eberick-Itens_associados - Armadura - Aço CA50 - ø 6.3 mm: 3.41561 kg
V327 | COB CX DAGUA | 15 | 50 | 0 | 0.42 % | 0.099757 | 1.51813 | 0.204604 | 1.09274 | 0 | 0 | Viga C-30 - Seção Retangular 15 X 50 | 5.33366 | AltoQi_Eberick-Itens_associados - Armadura - Aço CA50 - ø 6.3 mm: 2.36425 kg
V328 | COB CX DAGUA | 15 | 50 | -26 | 0.20 % | 0.07108 | 0.97617 | 3.51494 | 1.05224 | 0 | 0 | Viga C-30 - Seção Retangular 15 X 50
V328 | COB CX DAGUA | 15 | 50 | -26 | 0.20 % | 0.164855 | 2.26401 | 8.15212 | 2.44044 | 0 | 0 | Viga C-30 - Seção Retangular 15 X 50
V329 | COB CX DAGUA | 12 | 30 | -150 | 0.28 % | 0.156695 | 3.13389 | 8.46378 | 3.7727 | 222 | 0 | Viga C-30 - Seção Retangular 12 X 30
V329 | COB CX DAGUA | 12 | 30 | -150 | 0.28 % | 0.112661 | 2.25322 | 6.08532 | 2.71251 | 222 | 0 | Viga C-30 - Seção Retangular 12 X 30
V330 | COB CX DAGUA | 15 | 40 | -26 | 0.17 % | 0.131465 | 1.55566 | 6.01704 | 2.83139 | 0 | 0 | Viga C-30 - Seção Retangular 15 X 40
V330 | COB CX DAGUA | 15 | 40 | -26 | 0.17 % | 0.056683 | 0.670755 | 2.59436 | 1.22081 | 0 | 0 | Viga C-30 - Seção Retangular 15 X 40
V331 | COB CX DAGUA | 15 | 40 | 0 | 0.17 % | 0.09379 | 1.4495 | 3.19203 | 1.27983 | 229.4 | 0 | Viga C-30 - Seção Retangular 15 X 40
V331 | COB CX DAGUA | 15 | 40 | 0 | 0.17 % | 0.094448 | 1.45968 | 3.21444 | 1.28882 | 0 | 0 | Viga C-30 - Seção Retangular 15 X 40
V332 | COB CX DAGUA | 15 | 40 | 0 | 0.17 % | 0.094201 | 1.45485 | 3.38594 | 1.32176 | 0 | 0 | Viga C-30 - Seção Retangular 15 X 40
V332 | COB CX DAGUA | 15 | 40 | 0 | 0.17 % | 0.088865 | 1.37244 | 3.19414 | 1.24689 | 229.4 | 0 | Viga C-30 - Seção Retangular 15 X 40
V333 | COB CX DAGUA | 15 | 40 | -26 | 0.17 % | 0.055893 | 0.680027 | 2.63359 | 1.40265 | 0 | 0 | Viga C-30 - Seção Retangular 15 X 40
V333 | COB CX DAGUA | 15 | 40 | -26 | 0.17 % | 0.12963 | 1.57717 | 6.10802 | 3.25313 | 0 | 0 | Viga C-30 - Seção Retangular 15 X 40
V334 | COB CX DAGUA | 15 | 40 | -26 | 0.17 % | 0.058416 | 0.835598 | 1.87469 | 0.779999 | 0 | 0 | Viga C-30 - Seção Retangular 15 X 40
V334 | COB CX DAGUA | 15 | 40 | -26 | 0.17 % | 0.141606 | 2.02557 | 4.54442 | 1.89079 | 0 | 0 | Viga C-30 - Seção Retangular 15 X 40
V334 | COB CX DAGUA | 15 | 40 | -26 | 0.17 % | 0.018 | 0.257477 | 0.577656 | 0.240345 | 0 | 0 | Viga C-30 - Seção Retangular 15 X 40
V335 | COB CX DAGUA | 15 | 40 | 0 | 0.17 % | 0.183066 | 2.89854 | 6.58008 | 2.56865 | 0 | 0 | Viga C-30 - Seção Retangular 15 X 40
V336 | COB CX DAGUA | 15 | 40 | 0 | 0.17 % | 0.094201 | 1.45485 | 3.38594 | 1.32176 | 0 | 0 | Viga C-30 - Seção Retangular 15 X 40
V336 | COB CX DAGUA | 15 | 40 | 0 | 0.17 % | 0.088865 | 1.37244 | 3.19414 | 1.24689 | 229.4 | 0 | Viga C-30 - Seção Retangular 15 X 40
V337 | COB CX DAGUA | 15 | 40 | 0 | 0.17 % | 0.094534 | 1.46172 | 3.20451 | 1.34857 | 0 | 0 | Viga C-30 - Seção Retangular 15 X 40
V337 | COB CX DAGUA | 15 | 40 | 0 | 0.17 % | 0.097532 | 1.50807 | 3.30612 | 1.39133 | 229.4 | 0 | Viga C-30 - Seção Retangular 15 X 40
V338 | COB CX DAGUA | 15 | 30 | -41 | 0.22 % | 0.135032 | 1.89044 | 6.37174 | 2.88401 | 66.6 | 0 | Viga C-30 - Seção Retangular 15 X 30
V339 | COB CX DAGUA | 15 | 40 | 0 | 0.17 % | 0.180066 | 2.49091 | 6.58008 | 2.56865 | 0 | 0 | Viga C-30 - Seção Retangular 15 X 40
V340 | COB CX DAGUA | 15 | 30 | -41 | 0.22 % | 0.132813 | 1.85938 | 6.11132 | 2.74668 | 122.84 | 0 | Viga C-30 - Seção Retangular 15 X 30
V341 | COB CX DAGUA | 15 | 40 | 0 | 0.17 % | 0.193812 | 2.68107 | 6.61481 | 2.73989 | 296 | 0 | Viga C-30 - Seção Retangular 15 X 40
V342 | COB CX DAGUA | 15 | 30 | 60 | 0.22 % | 0.09315 | 1.5525 | 4.51404 | 1.92267 | 214.6 | 0 | Viga C-30 - Seção Retangular 15 X 30
V343 | COB CX DAGUA | 15 | 30 | 60 | 0.22 % | 0.095409 | 1.59015 | 4.65294 | 2.06001 | 214.6 | 0 | Viga C-30 - Seção Retangular 15 X 30
V344 | COB CX DAGUA | 15 | 30 | 90 | 0.22 % | 0.094941 | 1.58235 | 4.54877 | 2.06001 | 170.2 | 0 | Viga C-30 - Seção Retangular 15 X 30
V401 | TELHADO CINE | 15 | 30 | 0 | 0.22 % | 0.1134 | 1.89 | 5.24323 | 2.33467 | 177.6 | 0 | Viga C-30 - Seção Retangular 15 X 30
V402 | TELHADO CINE | 15 | 40 | -42 | 0.17 % | 0.279618 | 3.86805 | 4.57481 | 3.9386 | 266.4 | 0 | Viga C-30 - Seção Retangular 15 X 40 | 7.44654
V403 | TELHADO CINE | 15 | 40 | -42 | 0.26 % | 0.279618 | 3.30881 |  | 3.9386 | 0 | 0 | Viga C-30 - Seção Retangular 15 X 40 | 15.734
V404 | TELHADO CINE | 15 | 40 | -42 | 0.26 % | 0.279618 | 3.30881 |  | 3.9386 | 0 | 0 | Viga C-30 - Seção Retangular 15 X 40 | 15.734
V405 | TELHADO CINE | 15 | 40 | -42 | 0.39 % | 0.279618 | 3.30881 |  | 3.9386 | 0 | 0 | Viga C-30 - Seção Retangular 15 X 40 | 17.6398
V406 | TELHADO CINE | 15 | 40 | -42 | 0.17 % | 0.1509 | 1.81103 | 4.77287 | 2.02762 | 0 | 0 | Viga C-30 - Seção Retangular 15 X 40
V406 | TELHADO CINE | 15 | 40 | -42 | 0.17 % | 0.142218 | 1.70684 | 4.49828 | 1.91097 | 0 | 0 | Viga C-30 - Seção Retangular 15 X 40
V407 | TELHADO CINE | 15 | 40 | -35 | 0.17 % | 0.1242 | 1.5111 | 4.896 | 1.71243 | 0 | 0 | Viga C-30 - Seção Retangular 15 X 40
V408 | TELHADO CINE | 15 | 40 | -42 | 0.17 % | 0.1434 | 2.0315 | 5.06962 | 2.05492 | 0 | 0 | Viga C-30 - Seção Retangular 15 X 40 | AltoQi_Eberick-Itens_associados - Armadura - Aço CA50 - ø 6.3 mm: 0.199189 kg
V409 | TELHADO CINE | 15 | 40 | -35 | 0.17 % | 0.127212 | 1.80217 | 4.77447 | 1.88368 | 0 | 0 | Viga C-30 - Seção Retangular 15 X 40
V410 | TELHADO CINE | 15 | 40 | -42 | 0.17 % | 0.210355 | 2.94001 | 7.07287 | 2.87875 | 0 | 0 | Viga C-30 - Seção Retangular 15 X 40
V410 | TELHADO CINE | 15 | 40 | -42 | 0.17 % | 0.165036 | 2.30662 | 5.54909 | 2.25855 | 0 | 0 | Viga C-30 - Seção Retangular 15 X 40
V411 | TELHADO CINE | 15 | 40 | -42 | 0.17 % | 0.207831 | 2.875 | 6.66943 | 2.92228 | 0 | 0 | Viga C-30 - Seção Retangular 15 X 40
V411 | TELHADO CINE | 15 | 40 | -42 | 0.17 % | 0.184722 | 2.55533 | 5.92786 | 2.59736 | 0 | 0 | Viga C-30 - Seção Retangular 15 X 40
V411 | TELHADO CINE | 15 | 40 | -42 | 0.17 % | 0.179847 | 2.48788 | 5.77139 | 2.5288 | 0 | 0 | Viga C-30 - Seção Retangular 15 X 40
V412 | TELHADO CINE | 15 | 40 | -35 | 0.17 % | 0.081282 | 1.03849 | 3.08239 | 1.2095 | 0 | 0 | Viga C-30 - Seção Retangular 15 X 40
V412 | TELHADO CINE | 15 | 40 | -35 | 0.17 % | 0.01916 | 0.244796 | 0.726587 | 0.285106 | 0 | 0 | Viga C-30 - Seção Retangular 15 X 40
V412 | TELHADO CINE | 15 | 40 | -35 | 0.17 % | 0.026146 | 0.334059 | 0.991531 | 0.389068 | 0 | 0 | Viga C-30 - Seção Retangular 15 X 40
V413 | TELHADO CINE | 15 | 30 | -42 | 0.22 % | 0.032517 | 0.382979 | 0.92017 | 0.824002 | 0 | 0 | Viga C-30 - Seção Retangular 15 X 30 | 2.6246
V414 | TELHADO CINE | 15 | 40 | -35 | 0.17 % | 0.04201 | 0.621072 | 1.55341 | 0.610648 | 266.4 | 0 | Viga C-30 - Seção Retangular 15 X 40
V414 | TELHADO CINE | 15 | 40 | -35 | 0.17 % | 0.043277 | 0.639815 | 1.60029 | 0.629077 | 266.4 | 0 | Viga C-30 - Seção Retangular 15 X 40
V414 | TELHADO CINE | 15 | 40 | -35 | 0.17 % | 0.044301 | 0.654943 | 1.63813 | 0.643952 | 266.4 | 0 | Viga C-30 - Seção Retangular 15 X 40
V415 | TELHADO CINE | 15 | 40 | -42 | 0.17 % | 0.070742 | 0.978597 | 2.40673 | 1.01736 | 266.4 | 0 | Viga C-30 - Seção Retangular 15 X 40
V415 | TELHADO CINE | 15 | 40 | -42 | 0.17 % | 0.135358 | 1.87245 | 4.60506 | 1.94661 | 266.4 | 0 | Viga C-30 - Seção Retangular 15 X 40
V415 | TELHADO CINE | 15 | 40 | -42 | 0.17 % | 0.043956 | 0.60806 | 1.49544 | 0.632142 | 266.4 | 0 | Viga C-30 - Seção Retangular 15 X 40
V416 | TELHADO CINE | 15 | 40 | -42 | 0.17 % | 0.183653 | 2.54054 | 5.89305 | 2.55553 | 266.4 | 0 | Viga C-30 - Seção Retangular 15 X 40
V416 | TELHADO CINE | 15 | 40 | -42 | 0.17 % | 0.185755 | 2.5696 | 5.96048 | 2.58477 | 266.4 | 0 | Viga C-30 - Seção Retangular 15 X 40
V416 | TELHADO CINE | 15 | 40 | -42 | 0.17 % | 0.208992 | 2.89106 | 6.70613 | 2.90813 | 266.4 | 0 | Viga C-30 - Seção Retangular 15 X 40
VTR1 | TELHADO CINE | 13 | 40 | 0 | 0.30 % | 0.152301 | 2.72385 |  | 2.3668 | 0 | 0 | Viga C-30 - Seção Retangular 13 X 40 | 8.76822
VTR1 | TELHADO CINE | 13 | 40 | 0 | 0.30 % | 0.134898 | 2.4126 |  | 2.09634 | 0 | 0 | Viga C-30 - Seção Retangular 13 X 40 | 7.76627
VTR1 | TELHADO CINE | 13 | 40 | 0 | 0.30 % | 0.036833 | 0.65874 |  | 0.57239 | 0 | 0 | Viga C-30 - Seção Retangular 13 X 40 | 2.12052
VTR1 | TELHADO CINE | 13 | 40 | 0 | 0.30 % | 0.066916 | 1.19677 |  | 1.0399 | 0 | 0 | Viga C-30 - Seção Retangular 13 X 40 | 3.85248
VTR1 | TELHADO CINE | 13 | 40 | 0 | 0.30 % | 0.037734 | 0.674859 |  | 0.586396 | 0 | 0 | Viga C-30 - Seção Retangular 13 X 40 | 2.17241
VTR1 | TELHADO CINE | 13 | 40 | 0 | 0.30 % | 0.172284 | 3.08124 |  | 2.67734 | 0 | 0 | Viga C-30 - Seção Retangular 13 X 40 | 9.91867
VTR1 | TELHADO CINE | 13 | 40 | 0 | 0.30 % | 0.035304 | 0.631401 |  | 0.548635 | 0 | 0 | Viga C-30 - Seção Retangular 13 X 40 | 2.03251
VTR1 | TELHADO CINE | 13 | 40 | 0 | 0.30 % | 0.091864 | 1.64294 |  | 1.42758 | 0 | 0 | Viga C-30 - Seção Retangular 13 X 40 | 5.28872
VTR1 | TELHADO CINE | 13 | 40 | 0 | 0.30 % | 0.149014 | 2.66507 |  | 2.31572 | 0 | 0 | Viga C-30 - Seção Retangular 13 X 40 | 8.57899
VTR1 | TELHADO CINE | 13 | 40 | 0 | 0.30 % | 0.057566 | 1.02955 |  | 0.89459 | 0 | 0 | Viga C-30 - Seção Retangular 13 X 40 | 3.31417
VTR1 | TELHADO CINE | 13 | 40 | 0 | 0.30 % | 0.109138 | 1.95189 |  | 1.69603 | 0 | 0 | Viga C-30 - Seção Retangular 13 X 40 | 6.28325
VTR1 | TELHADO CINE | 13 | 40 | 0 | 0.30 % |  | 0.069006 |  | 0.05996 | 0 | 0 | Viga C-30 - Seção Retangular 13 X 40 | 0.222134
VTR2 | TELHADO CINE | 13 | 40 | 0 | 0.30 % | 0.096251 | 1.72141 |  | 1.49602 | 0 | 0 | Viga C-30 - Seção Retangular 13 X 40 | 5.50535
VTR2 | TELHADO CINE | 13 | 40 | 0 | 0.30 % | 0.208441 | 3.72788 |  | 3.23978 | 0 | 0 | Viga C-30 - Seção Retangular 13 X 40 | 11.9224
VTR2 | TELHADO CINE | 13 | 40 | 0 | 0.30 % | 0.183744 | 3.28618 |  | 2.85591 | 0 | 0 | Viga C-30 - Seção Retangular 13 X 40 | 10.5098
VTR2 | TELHADO CINE | 13 | 40 | 0 | 0.30 % | 0.041006 | 0.733381 |  | 0.637356 | 0 | 0 | Viga C-30 - Seção Retangular 13 X 40 | 2.34547
VTR2 | TELHADO CINE | 13 | 40 | 0 | 0.30 % | 0.150285 | 2.68779 |  | 2.33587 | 0 | 0 | Viga C-30 - Seção Retangular 13 X 40 | 8.596
VTR2 | TELHADO CINE | 13 | 40 | 0 | 0.30 % | 0.038218 | 0.683516 |  | 0.59402 | 0 | 0 | Viga C-30 - Seção Retangular 13 X 40 | 2.186
VTR2 | TELHADO CINE | 13 | 40 | 0 | 0.30 % |  | 0.069711 |  | 0.060584 | 0 | 0 | Viga C-30 - Seção Retangular 13 X 40 | 0.222948
VTR2 | TELHADO CINE | 13 | 40 | 0 | 0.30 % | 0.067505 | 1.20729 |  | 1.04922 | 0 | 0 | Viga C-30 - Seção Retangular 13 X 40 | 3.86112
VTR2 | TELHADO CINE | 13 | 40 | 0 | 0.30 % | 0.179926 | 3.21791 |  | 2.79658 | 0 | 0 | Viga C-30 - Seção Retangular 13 X 40 | 10.2914
VTR2 | TELHADO CINE | 13 | 40 | 0 | 0.30 % | 0.026008 | 0.465144 |  | 0.404241 | 0 | 0 | Viga C-30 - Seção Retangular 13 X 40 | 1.48761
VTR2 | TELHADO CINE | 13 | 40 | 0 | 0.30 % | 0.06283 | 1.1237 |  | 0.976567 | 0 | 0 | Viga C-30 - Seção Retangular 13 X 40 | 3.59377
V501 | TELHADO ANEXO | 15 | 30 | 0 | 0.22 % | 0.211964 | 3.53273 | 9.28851 | 4.39468 | 88.8 | 40 | Viga C-30 - Seção Retangular 15 X 30
V502 | TELHADO ANEXO | 12 | 30 | -50 | 0.28 % | 0.106817 | 2.13634 | 5.65107 | 2.55456 | 162.8 | 100 | Viga C-30 - Seção Retangular 12 X 30
V502 | TELHADO ANEXO | 12 | 30 | -50 | 0.28 % | 0.128403 | 2.56805 | 6.79305 | 3.0708 | 162.8 | 100 | Viga C-30 - Seção Retangular 12 X 30
V502 | TELHADO ANEXO | 12 | 30 | -50 | 0.28 % | 0.126007 | 2.52015 | 6.66634 | 3.01351 | 162.8 | 100 | Viga C-30 - Seção Retangular 12 X 30
V502 | TELHADO ANEXO | 12 | 30 | -50 | 0.28 % | 0.111997 | 2.23994 | 5.92511 | 2.67844 | 162.8 | 100 | Viga C-30 - Seção Retangular 12 X 30
V503 | TELHADO ANEXO | 12 | 30 | 0 | 0.28 % | 0.10805 | 2.16101 | 6.25021 | 2.67038 | 88.8 | 100 | Viga C-30 - Seção Retangular 12 X 30
V504 | TELHADO ANEXO | 12 | 30 | 0 | 0.28 % | 0.113658 | 2.27316 | 5.89626 | 2.73883 | 88.8 | 100 | Viga C-30 - Seção Retangular 12 X 30
V504 | TELHADO ANEXO | 12 | 30 | 0 | 0.28 % | 0.113217 | 2.26435 | 5.8734 | 2.72821 | 88.8 | 100 | Viga C-30 - Seção Retangular 12 X 30
V504 | TELHADO ANEXO | 12 | 30 | 0 | 0.28 % | 0.127381 | 2.54762 | 6.60815 | 3.06951 | 88.8 | 100 | Viga C-30 - Seção Retangular 12 X 30
V504 | TELHADO ANEXO | 12 | 30 | 0 | 0.28 % | 0.084725 | 1.69451 | 4.39532 | 2.04164 | 88.8 | 100 | Viga C-30 - Seção Retangular 12 X 30
V504 | TELHADO ANEXO | 12 | 30 | 0 | 0.28 % | 0.152045 | 3.04089 | 7.88763 | 3.66383 | 88.8 | 100 | Viga C-30 - Seção Retangular 12 X 30

# IfcColumn (267)
Material: Concreto
Pset_ConcreteElementGeneral - ConstructionMethod: InSitu; ExposureClass: 2; StrengthClass: C-30
AltoQi_Eberick_Elemento - Elemento: Pilar; Tipo: retangular
AltoQi_Eberick_Padrão - Classe de concreto: C-30
AltoQi_Eberick-Itens_associados - Status: Dimensionado
Pset_ColumnCommon - LoadBearing: yes
Name | In | ConcreteCover (cm) = Cobrimento (cm) | Seção_b (cm) | Seção_h (cm) | Elevação (cm) | Taxa de armadura | Taxa de compressão bruta | Taxa de compressão homogeneizada | Ambiente | Concreto - C-30 - Abatimento 5 cm (m3) | Forma - Estrutura - Concreto (m2) | Armadura - Aço CA50 - ø 10.0 mm (kg) | Armadura - Aço CA60 - ø 5.0 mm (kg) | Reference | IsExternal
P1 | TÉRREO | 4.5 | 20 | 30 | 0 | 0.52 % | 0.06 | 0.06 | Contato com solo | 0.192 | 3.2 | 10.7697 | 3.81483 | Pilar C-30 - Retangular 20x30 | yes
P10 | TÉRREO | 4.5 | 35 | 35 | -24 | 0.90 % | 0.07 | 0.06 | Contato com solo | 0.331975 | 3.794 | 26.2867 | 8.19933 | Pilar C-30 - Retangular 35x35 | yes
P11 | TÉRREO | 4.5 | 20 | 30 | 0 | 1.31 % | 0.17 | 0.14 | Contato com solo | 0.189 | 3.15 | 26.9242 | 3.81483 | Pilar C-30 - Retangular 20x30 | yes
P12 | TÉRREO | 4.5 | 20 | 30 | 0 | 1.05 % | 0.13 | 0.11 | Contato com solo | 0.192 | 3.2 | 21.5394 | 3.81483 | Pilar C-30 - Retangular 20x30 | yes
P13 | TÉRREO | 4.5 | 20 | 65 | 0 | 0.48 % | 0.06 | 0.06 | Contato com solo | 0.416 | 5.44 | 21.4173 | 10.0203 | Pilar C-30 - Retangular 20x65 | yes
P14 | TÉRREO | 4.5 | 20 | 50 | 0 | 0.47 % | 0.07 | 0.06 | Contato com solo | 0.32 | 4.48 | 15.6391 | 7.17187 | Pilar C-30 - Retangular 20x50 | yes
P15 | TÉRREO | 4.5 | 20 | 50 | -44 | 0.47 % | 0.05 | 0.05 | Contato com solo | 0.276 | 3.864 | 15.1508 | 6.21562 | Pilar C-30 - Retangular 20x50 | yes
P16 | TÉRREO | 4.5 | 20 | 50 | -44 | 0.47 % | 0.05 | 0.05 | Contato com solo | 0.276 | 3.864 | 15.1508 | 6.21562 | Pilar C-30 - Retangular 20x50 | yes
P17 | TÉRREO | 4.5 | 20 | 50 | -44 | 0.47 % | 0.06 | 0.06 | Contato com solo | 0.276 | 3.864 | 13.8487 | 6.21562 | Pilar C-30 - Retangular 20x50 | yes
P18 | TÉRREO | 4.5 | 20 | 30 | -24 | 0.79 % | 0.19 | 0.17 | Contato com solo | 0.1746 | 2.91 | 15.1779 | 3.5605 | Pilar C-30 - Retangular 20x30 | yes
P19 | TÉRREO | 4.5 | 20 | 35 | -24 | 1.72 % | 0.17 | 0.14 | Contato com solo | 0.1827 | 2.871 | 0.908776 | 3.02643 | Pilar C-30 - Retangular 20x35 | yes | AltoQi_Eberick-Itens_associados - Armadura - Aço CA50 - ø 16.0 mm: 46.4599 kg
P2 | TÉRREO | 4.5 | 20 | 55 | 0 | 0.43 % | 0.06 | 0.05 | Contato com solo | 0.352 | 4.8 | 16.1545 | 7.68052 | Pilar C-30 - Retangular 20x55 | yes
P20 | TÉRREO | 4.5 | 20 | 30 | 0 | 0.52 % | 0.11 | 0.1 | Contato com solo | 0.192 | 3.2 | 10.7697 | 3.81483 | Pilar C-30 - Retangular 20x30 | yes
P21 | TÉRREO | 2.5 | 15 | 25 | -24 | 0.84 % | 0.04 | 0.04 | Interno | 0.111 | 2.368 | 9.14202 | 3.37061 | Pilar C-30 - Retangular 15x25 | no
P22 | TÉRREO | 2.5 | 20 | 30 | 0 | 0.52 % | 0.14 | 0.12 | Interno | 0.189 | 3.15 | 10.7697 | 4.62866 | Pilar C-30 - Retangular 20x30 | no
P23 | TÉRREO | 4.5 | 20 | 35 | 0 | 0.45 % | 0.14 | 0.13 | Contato com solo | 0.2205 | 3.465 | 10.7697 | 4.32347 | Pilar C-30 - Retangular 20x35 | yes
P24 | TÉRREO | 4.5 | 15 | 25 | -24 | 0.84 % | 0.03 | 0.03 | Contato com solo | 0.111 | 2.368 | 10.1186 | 2.61104 | Pilar C-30 - Retangular 15x25 | yes
P25 | TÉRREO | 4.5 | 20 | 30 | -24 | 0.79 % | 0.17 | 0.15 | Contato com solo | 0.1746 | 2.91 | 15.1779 | 3.5605 | Pilar C-30 - Retangular 20x30 | yes
P26 | TÉRREO | 4.5 | 20 | 35 | -24 | 2.87 % | 0.18 | 0.13 | Contato com solo | 0.1827 | 2.871 | 2.72633 | 3.02643 | Pilar C-30 - Retangular 20x35 | yes | AltoQi_Eberick-Itens_associados - Armadura - Aço CA50 - ø 16.0 mm: 76.2873 kg
P27 | TÉRREO | 4.5 | 25 | 30 | 0 | 1.05 % | 0.09 | 0.08 | Contato com solo | 0.24 | 3.52 | 26.4088 | 4.32347 | Pilar C-30 - Retangular 25x30 | yes
P28 | TÉRREO | 4.5 | 20 | 40 | 41 | 0.61 % | 0.1 | 0.09 | Contato com solo | 0.2848 | 4.272 |  | 4.3489 | Pilar C-30 - Retangular 20x40 | yes | AltoQi_Eberick-Itens_associados - Armadura - Aço CA50 - ø 12.5 mm: 18.9046 kg
P29 | TÉRREO | 4.5 | 20 | 40 | 41 | 0.61 % | 0.12 | 0.11 | Contato com solo | 0.2808 | 4.212 |  | 4.3489 | Pilar C-30 - Retangular 20x40 | yes | AltoQi_Eberick-Itens_associados - Armadura - Aço CA50 - ø 12.5 mm: 18.9046 kg
P3 | TÉRREO | 4.5 | 20 | 30 | 0 | 1.83 % | 0.09 | 0.07 | Contato com solo | 0.186 | 3.1 | 38.9553 | 3.81483 | Pilar C-30 - Retangular 20x30 | yes
P30 | TÉRREO | 4.5 | 20 | 30 | -24 | 0.79 % | 0.19 | 0.17 | Contato com solo | 0.1716 | 2.86 | 15.1779 | 3.5605 | Pilar C-30 - Retangular 20x30 | yes
P31 | TÉRREO | 4.5 | 20 | 35 | -24 | 2.30 % | 0.18 | 0.13 | Contato com solo | 0.1862 | 2.926 |  | 3.95216 | Pilar C-30 - Retangular 20x35 | yes | AltoQi_Eberick-Itens_associados - Armadura - Aço CA50 - ø 16.0 mm: 58.6131 kg
P32 | TÉRREO | 4.5 | 25 | 30 | 0 | 2.14 % | 0.13 | 0.1 | Contato com solo | 0.23625 | 3.465 | 2.72633 | 2.7382 | Pilar C-30 - Retangular 25x30 | yes | AltoQi_Eberick-Itens_associados - Armadura - Aço CA50 - ø 16.0 mm: 57.6408 kg
P33 | TÉRREO | 4.5 | 20 | 40 | 41 | 0.61 % | 0.13 | 0.12 | Contato com solo | 0.2808 | 4.212 |  | 4.3489 | Pilar C-30 - Retangular 20x40 | yes | AltoQi_Eberick-Itens_associados - Armadura - Aço CA50 - ø 12.5 mm: 18.9046 kg
P34 | TÉRREO | 4.5 | 20 | 30 | -24 | 1.64 % | 0.13 | 0.11 | Contato com solo | 0.1656 | 2.76 | 0.908776 | 2.79754 | Pilar C-30 - Retangular 20x30 | yes | AltoQi_Eberick-Itens_associados - Armadura - Aço CA50 - ø 12.5 mm: 35.1176 kg
P35 | TÉRREO | 4.5 | 20 | 35 | 41 | 0.45 % | 0.14 | 0.13 | Contato com solo | 0.2492 | 3.916 | 11.8819 | 4.75582 | Pilar C-30 - Retangular 20x35 | yes
P36 | TÉRREO | 4.5 | 15 | 25 | -24 | 0.84 % | 0.14 | 0.12 | Contato com solo | 0.111 | 2.368 | 10.1186 | 2.61104 | Pilar C-30 - Retangular 15x25 | yes
P37 | TÉRREO | 4.5 | 20 | 40 | -24 | 0.59 % | 0.13 | 0.12 | Contato com solo | 0.2328 | 3.492 | 15.1779 | 5.74428 | Pilar C-30 - Retangular 20x40 | yes
P38 | TÉRREO | 4.5 | 15 | 25 | -24 | 1.68 % | 0.19 | 0.15 | Contato com solo | 0.111 | 2.368 | 20.2372 | 2.61104 | Pilar C-30 - Retangular 15x25 | yes
P39 | TÉRREO | 4.5 | 20 | 35 | -24 | 1.72 % | 0.13 | 0.1 | Contato com solo | 0.1862 | 2.926 | 0.908776 | 3.02643 | Pilar C-30 - Retangular 20x35 | yes | AltoQi_Eberick-Itens_associados - Armadura - Aço CA50 - ø 16.0 mm: 43.4737 kg
P4 | TÉRREO | 4.5 | 20 | 30 | 0 | 1.31 % | 0.1 | 0.08 | Contato com solo | 0.183 | 3.05 | 27.5888 | 3.81483 | Pilar C-30 - Retangular 20x30 | yes
P40 | TÉRREO | 4.5 | 20 | 30 | 0 | 1.64 % | 0.14 | 0.12 | Contato com solo | 0.189 | 3.15 |  | 3.05186 | Pilar C-30 - Retangular 20x30 | yes | AltoQi_Eberick-Itens_associados - Armadura - Aço CA50 - ø 12.5 mm: 32.3412 kg
P41 | TÉRREO | 4.5 | 20 | 30 | 21 | 0.52 % | 0.18 | 0.16 | Contato com solo | 0.2016 | 3.36 | 11.3394 | 3.94199 | Pilar C-30 - Retangular 20x30 | yes
P42 | TÉRREO | 4.5 | 20 | 30 | -9 | 0.52 % | 0.12 | 0.11 | Contato com solo | 0.1866 | 3.11 | 10.5255 | 3.68766 | Pilar C-30 - Retangular 20x30 | yes
P43 | TÉRREO | 4.5 | 20 | 50 | -24 | 0.47 % | 0.08 | 0.08 | Contato com solo | 0.291 | 4.074 | 14.6625 | 6.69375 | Pilar C-30 - Retangular 20x50 | yes
P44 | TÉRREO | 4.5 | 20 | 50 | -24 | 0.47 % | 0.08 | 0.07 | Contato com solo | 0.291 | 4.074 | 14.6625 | 6.69375 | Pilar C-30 - Retangular 20x50 | yes
P45 | TÉRREO | 4.5 | 20 | 50 | -24 | 0.47 % | 0.11 | 0.1 | Contato com solo | 0.291 | 4.074 | 14.6625 | 6.69375 | Pilar C-30 - Retangular 20x50 | yes
P46 | TÉRREO | 4.5 | 20 | 50 | -24 | 0.47 % | 0.08 | 0.08 | Contato com solo | 0.296 | 4.144 | 14.6625 | 6.69375 | Pilar C-30 - Retangular 20x50 | yes
P47 | TÉRREO | 4.5 | 20 | 50 | -24 | 0.47 % | 0.1 | 0.09 | Contato com solo | 0.291 | 4.074 | 14.6625 | 6.69375 | Pilar C-30 - Retangular 20x50 | yes
P48 | TÉRREO | 4.5 | 15 | 25 | -24 | 1.26 % | 0.19 | 0.16 | Contato com solo | 0.111 | 2.368 | 14.6625 | 2.61104 | Pilar C-30 - Retangular 15x25 | yes
P49 | TÉRREO | 4.5 | 20 | 35 | -24 | 2.80 % | 0.16 | 0.12 | Contato com solo | 0.1792 | 2.816 |  | 4.14036 | Pilar C-30 - Retangular 20x35 | yes | AltoQi_Eberick-Itens_associados - Armadura - Aço CA50 - ø 12.5 mm: 68.794 kg
P5 | TÉRREO | 4.5 | 20 | 50 | -44 | 0.47 % | 0.05 | 0.05 | Contato com solo | 0.266 | 3.724 | 15.9918 | 6.21562 | Pilar C-30 - Retangular 20x50 | yes
P50 | TÉRREO | 4.5 | 15 | 25 | -24 | 0.84 % | 0.19 | 0.16 | Contato com solo | 0.111 | 2.368 | 12.3295 | 2.61104 | Pilar C-30 - Retangular 15x25 | yes
P51 | TÉRREO | 4.5 | 20 | 30 | 0 | 0.52 % | 0.07 | 0.06 | Contato com solo | 0.189 | 3.15 | 11.4479 | 3.81483 | Pilar C-30 - Retangular 20x30 | yes
P52 | TÉRREO | 4.5 | 20 | 45 | 22 | 0.52 % | 0.09 | 0.08 | Contato com solo | 0.2853 | 4.121 | 19.4912 | 6.88534 | Pilar C-30 - Retangular 20x45 | yes
P53 | TÉRREO | 4.5 | 20 | 30 | -40 | 1.05 % | 0.12 | 0.11 | Contato com solo | 0.153 | 2.55 | 20.7798 | 3.30618 | Pilar C-30 - Retangular 20x30 | yes
P54 | TÉRREO | 4.5 | 20 | 30 | -24 | 2.09 % | 0.15 | 0.1 | Contato com solo | 0.1596 | 2.66 |  | 2.67038 | Pilar C-30 - Retangular 20x30 | yes | AltoQi_Eberick-Itens_associados - Armadura - Aço CA50 - ø 20.0 mm: 49.6979 kg
P55 | TÉRREO | 4.5 | 20 | 30 | -24 | 1.05 % | 0.1 | 0.08 | Contato com solo | 0.1686 | 2.81 | 21.3766 | 3.5605 | Pilar C-30 - Retangular 20x30 | yes
P56 | TÉRREO | 4.5 | 20 | 30 | -24 | 1.31 % | 0.13 | 0.11 | Contato com solo | 0.1626 | 2.71 | 26.1239 | 3.5605 | Pilar C-30 - Retangular 20x30 | yes
P57 | TÉRREO | 4.5 | 20 | 30 | -24 | 1.05 % | 0.1 | 0.09 | Contato com solo | 0.1686 | 2.81 | 21.3766 | 3.5605 | Pilar C-30 - Retangular 20x30 | yes
P58 | TÉRREO | 4.5 | 20 | 35 | -24 | 1.35 % | 0.14 | 0.12 | Contato com solo | 0.1862 | 2.926 | 32.3633 | 5.26955 | Pilar C-30 - Retangular 20x35 | yes
P59 | TÉRREO | 4.5 | 30 | 30 | -24 | 1.05 % | 0.06 | 0.06 | Contato com solo | 0.2484 | 3.312 | 23.0856 | 4.18783 | Pilar C-30 - Retangular 30x30 | yes
P6 | TÉRREO | 4.5 | 20 | 30 | -44 | 0.52 % | 0.06 | 0.05 | Contato com solo | 0.1656 | 2.76 | 10.1186 | 3.30618 | Pilar C-30 - Retangular 20x30 | yes
P7 | TÉRREO | 4.5 | 20 | 30 | -44 | 0.79 % | 0.05 | 0.04 | Contato com solo | 0.1656 | 2.76 | 15.1779 | 3.30618 | Pilar C-30 - Retangular 20x30 | yes
P8 | TÉRREO | 4.5 | 20 | 30 | -24 | 0.52 % | 0.09 | 0.08 | Contato com solo | 0.1716 | 2.86 | 10.9324 | 3.5605 | Pilar C-30 - Retangular 20x30 | yes
P9 | TÉRREO | 4.5 | 20 | 35 | -24 | 1.72 % | 0.17 | 0.13 | Contato com solo | 0.1862 | 2.926 |  | 3.02643 | Pilar C-30 - Retangular 20x35 | yes | AltoQi_Eberick-Itens_associados - Armadura - Aço CA50 - ø 16.0 mm: 44.9668 kg
P1 | PAVTO 01 | 2.5 | 20 | 30 | 0 | 0.52 % | 0.05 | 0.05 | Interno | 0.1752 | 2.92 | 8.81649 | 3.85721 | Pilar C-30 - Retangular 20x30 | no
P10 | PAVTO 01 | 2.5 | 20 | 30 | 0 | 0.52 % | 0.12 | 0.11 | Interno | 0.1896 | 3.16 | 9.46755 | 4.16579 | Pilar C-30 - Retangular 20x30 | no
P11 | PAVTO 01 | 2.5 | 20 | 30 | 0 | 1.31 % | 0.16 | 0.14 | Interno | 0.1752 | 2.92 | 22.0412 | 3.85721 | Pilar C-30 - Retangular 20x30 | no
P12 | PAVTO 01 | 2.5 | 20 | 30 | 0 | 1.05 % | 0.12 | 0.11 | Interno | 0.1752 | 2.92 | 17.633 | 5.12882 | Pilar C-30 - Retangular 20x30 | no
P13 | PAVTO 01 | 2.5 | 20 | 30 | 0 | 0.79 % | 0.11 | 0.1 | Interno | 0.1752 | 2.92 | 13.2247 | 3.85721 | Pilar C-30 - Retangular 20x30 | no
P14 | PAVTO 01 | 2.5 | 20 | 30 | 0 | 0.52 % | 0.09 | 0.08 | Interno | 0.1752 | 2.92 | 8.81649 | 3.85721 | Pilar C-30 - Retangular 20x30 | no
P15 | PAVTO 01 | 2.5 | 20 | 40 | 0 | 0.59 % | 0.05 | 0.05 | Interno | 0.2688 | 4.032 | 15.0152 | 6.69375 | Pilar C-30 - Retangular 20x40 | no
P16 | PAVTO 01 | 2.5 | 20 | 40 | 0 | 0.59 % | 0.05 | 0.04 | Interno | 0.2688 | 4.032 | 15.0152 | 6.69375 | Pilar C-30 - Retangular 20x40 | no
P17 | PAVTO 01 | 2.5 | 20 | 30 | 0 | 0.52 % | 0.08 | 0.07 | Interno | 0.2016 | 3.36 | 10.0101 | 4.32008 | Pilar C-30 - Retangular 20x30 | no
P18 | PAVTO 01 | 2.5 | 20 | 30 | 0 | 0.79 % | 0.17 | 0.15 | Interno | 0.1896 | 3.16 | 14.2013 | 4.16579 | Pilar C-30 - Retangular 20x30 | no
P19 | PAVTO 01 | 2.5 | 20 | 30 | 0 | 1.05 % | 0.18 | 0.16 | Interno | 0.1896 | 3.16 | 21.6614 | 5.53913 | Pilar C-30 - Retangular 20x30 | no
P2 | PAVTO 01 | 2.5 | 20 | 55 | 0 | 0.43 % | 0.05 | 0.05 | Interno | 0.3212 | 4.38 | 13.6452 | 7.24817 | Pilar C-30 - Retangular 20x55 | no
P20 | PAVTO 01 | 2.5 | 20 | 30 | 0 | 0.52 % | 0.09 | 0.08 | Interno | 0.1752 | 2.92 | 8.81649 | 3.85721 | Pilar C-30 - Retangular 20x30 | no
P22 | PAVTO 01 | 2.5 | 20 | 30 | 0 | 0.52 % | 0.13 | 0.12 | Interno | 0.1752 | 2.92 | 8.81649 | 3.85721 | Pilar C-30 - Retangular 20x30 | no
P23 | PAVTO 01 | 2.5 | 20 | 35 | 0 | 0.45 % | 0.13 | 0.12 | Interno | 0.2044 | 3.212 | 12.4516 | 4.28108 | Pilar C-30 - Retangular 20x35 | no
P24 | PAVTO 01 | 2.5 | 15 | 25 | 0 | 0.84 % | 0.02 | 0.02 | Interno | 0.1185 | 2.528 | 9.46755 | 3.25023 | Pilar C-30 - Retangular 15x25 | no
P25 | PAVTO 01 | 2.5 | 20 | 30 | 0 | 0.79 % | 0.16 | 0.14 | Interno | 0.1896 | 3.16 | 14.2013 | 4.16579 | Pilar C-30 - Retangular 20x30 | no
P26 | PAVTO 01 | 2.5 | 20 | 30 | 0 | 1.83 % | 0.18 | 0.15 | Interno | 0.1896 | 3.16 | 34.0452 | 5.53913 | Pilar C-30 - Retangular 20x30 | no
P27 | PAVTO 01 | 2.5 | 25 | 30 | 0 | 0.84 % | 0.08 | 0.07 | Interno | 0.219 | 3.212 | 17.633 | 4.28108 | Pilar C-30 - Retangular 25x30 | no
P28 | PAVTO 01 | 2.5 | 20 | 40 | 0 | 0.61 % | 0.09 | 0.08 | Interno | 0.2008 | 3.012 |  | 3.19937 | Pilar C-30 - Retangular 20x40 | no | AltoQi_Eberick-Itens_associados - Armadura - Aço CA50 - ø 12.5 mm: 22.9737 kg
P29 | PAVTO 01 | 2.5 | 20 | 40 | 0 | 0.61 % | 0.11 | 0.1 | Interno | 0.2008 | 3.012 |  | 3.19937 | Pilar C-30 - Retangular 20x40 | no | AltoQi_Eberick-Itens_associados - Armadura - Aço CA50 - ø 12.5 mm: 26.4918 kg
P3 | PAVTO 01 | 2.5 | 20 | 30 | 0 | 0.79 % | 0.08 | 0.07 | Interno | 0.1752 | 2.92 | 13.2247 | 3.85721 | Pilar C-30 - Retangular 20x30 | no
P30 | PAVTO 01 | 2.5 | 20 | 30 | 0 | 0.79 % | 0.16 | 0.14 | Interno | 0.1896 | 3.16 | 13.713 | 4.16579 | Pilar C-30 - Retangular 20x30 | no
P31 | PAVTO 01 | 2.5 | 20 | 30 | 0 | 0.52 % | 0.17 | 0.16 | Interno | 0.1896 | 3.16 | 9.46755 | 4.16579 | Pilar C-30 - Retangular 20x30 | no
P32 | PAVTO 01 | 2.5 | 25 | 30 | 0 | 1.47 % | 0.12 | 0.1 | Interno | 0.219 | 3.212 | 30.8577 | 5.76463 | Pilar C-30 - Retangular 25x30 | no
P33 | PAVTO 01 | 2.5 | 20 | 40 | 0 | 0.61 % | 0.12 | 0.11 | Interno | 0.2008 | 3.012 |  | 3.19937 | Pilar C-30 - Retangular 20x40 | no | AltoQi_Eberick-Itens_associados - Armadura - Aço CA50 - ø 12.5 mm: 22.9737 kg
P34 | PAVTO 01 | 2.5 | 20 | 30 | 0 | 1.05 % | 0.12 | 0.1 | Interno | 0.1896 | 3.16 | 16.9819 | 4.16579 | Pilar C-30 - Retangular 20x30 | no | AltoQi_Eberick-Itens_associados - Armadura - Aço CA50 - ø 12.5 mm: 5.27718 kg
P35 | PAVTO 01 | 2.5 | 20 | 35 | 0 | 0.45 % | 0.13 | 0.12 | Interno | 0.1757 | 2.761 | 13.1569 | 3.59611 | Pilar C-30 - Retangular 20x35 | no
P36 | PAVTO 01 | 2.5 | 15 | 25 | 0 | 0.84 % | 0.13 | 0.11 | Interno | 0.1185 | 2.528 | 9.46755 | 3.25023 | Pilar C-30 - Retangular 15x25 | no
P37 | PAVTO 01 | 2.5 | 20 | 40 | 0 | 0.59 % | 0.12 | 0.11 | Interno | 0.2528 | 3.792 | 14.2013 | 6.45469 | Pilar C-30 - Retangular 20x40 | no
P38 | PAVTO 01 | 2.5 | 15 | 25 | 0 | 1.68 % | 0.19 | 0.16 | Interno | 0.1185 | 2.528 | 17.9585 | 3.25023 | Pilar C-30 - Retangular 15x25 | no
P39 | PAVTO 01 | 2.5 | 15 | 25 | 0 | 0.84 % | 0.16 | 0.14 | Interno | 0.1185 | 2.528 | 9.46755 | 3.25023 | Pilar C-30 - Retangular 15x25 | no
P4 | PAVTO 01 | 2.5 | 20 | 30 | 0 | 0.79 % | 0.09 | 0.08 | Interno | 0.1752 | 2.92 | 13.2247 | 3.85721 | Pilar C-30 - Retangular 20x30 | no
P40 | PAVTO 01 | 2.5 | 20 | 30 | 0 | 0.82 % | 0.13 | 0.12 | Interno | 0.1752 | 2.92 | 2.72633 | 3.08577 | Pilar C-30 - Retangular 20x30 | no | AltoQi_Eberick-Itens_associados - Armadura - Aço CA50 - ø 12.5 mm: 14.1572 kg
P41 | PAVTO 01 | 2.5 | 20 | 30 | 0 | 0.52 % | 0.17 | 0.15 | Interno | 0.1626 | 2.71 | 8.24681 | 3.54864 | Pilar C-30 - Retangular 20x30 | no
P42 | PAVTO 01 | 2.5 | 20 | 30 | 0 | 0.52 % | 0.11 | 0.1 | Interno | 0.1806 | 3.01 | 9.06064 | 4.0115 | Pilar C-30 - Retangular 20x30 | no
P43 | PAVTO 01 | 2.5 | 20 | 30 | 0 | 0.52 % | 0.12 | 0.11 | Interno | 0.1896 | 3.16 | 9.46755 | 4.16579 | Pilar C-30 - Retangular 20x30 | no
P44 | PAVTO 01 | 2.5 | 20 | 30 | 0 | 0.52 % | 0.11 | 0.1 | Interno | 0.1896 | 3.16 | 9.46755 | 4.16579 | Pilar C-30 - Retangular 20x30 | no
P45 | PAVTO 01 | 2.5 | 20 | 30 | 0 | 0.52 % | 0.15 | 0.14 | Interno | 0.1896 | 3.16 | 9.46755 | 4.16579 | Pilar C-30 - Retangular 20x30 | no
P46 | PAVTO 01 | 2.5 | 20 | 30 | 0 | 0.52 % | 0.12 | 0.11 | Interno | 0.1896 | 3.16 | 9.46755 | 4.16579 | Pilar C-30 - Retangular 20x30 | no
P47 | PAVTO 01 | 2.5 | 20 | 30 | 0 | 0.52 % | 0.14 | 0.13 | Interno | 0.1896 | 3.16 | 9.46755 | 4.16579 | Pilar C-30 - Retangular 20x30 | no
P48 | PAVTO 01 | 2.5 | 15 | 25 | 0 | 0.84 % | 0.16 | 0.14 | Interno | 0.1185 | 2.528 | 9.46755 | 3.25023 | Pilar C-30 - Retangular 15x25 | no
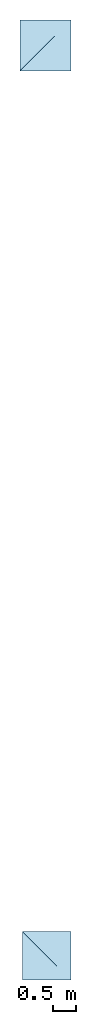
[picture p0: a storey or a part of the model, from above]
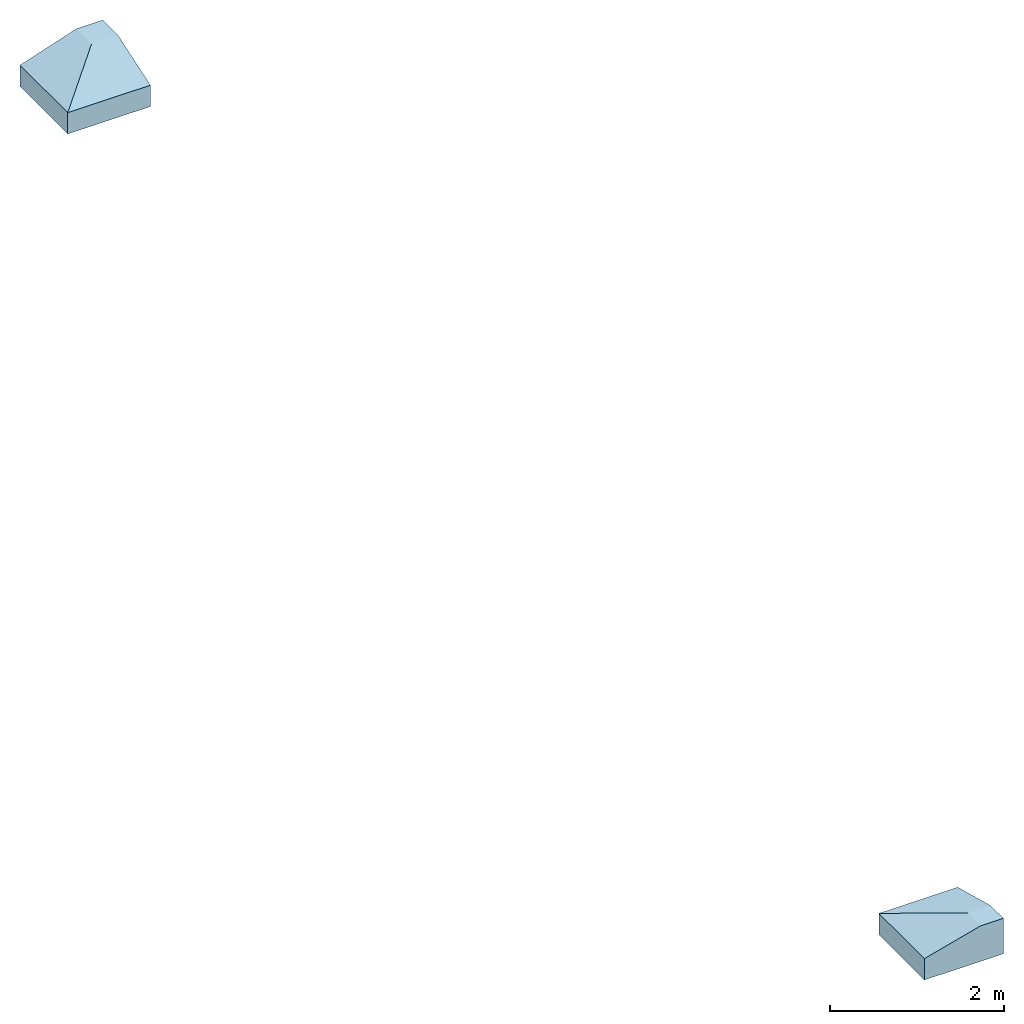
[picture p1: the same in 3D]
Properties of the parts of a building model (IFC4), part 3 of 4

# IfcColumn (267)
Name | In | ConcreteCover (cm) = Cobrimento (cm) | Seção_b (cm) | Seção_h (cm) | Elevação (cm) | Taxa de armadura | Taxa de compressão bruta | Taxa de compressão homogeneizada | Ambiente | Concreto - C-30 - Abatimento 5 cm (m3) | Forma - Estrutura - Concreto (m2) | Armadura - Aço CA50 - ø 10.0 mm (kg) | Armadura - Aço CA60 - ø 5.0 mm (kg) | Reference | IsExternal
P49 | PAVTO 01 | 2.5 | 20 | 30 | 0 | 0.82 % | 0.13 | 0.12 | Interno | 0.1896 | 3.16 |  | 3.39435 | Pilar C-30 - Retangular 20x30 | no | AltoQi_Eberick-Itens_associados - Armadura - Aço CA50 - ø 12.5 mm: 15.1745 kg
P5 | PAVTO 01 | 2.5 | 20 | 50 | 0 | 0.47 % | 0.04 | 0.04 | Interno | 0.336 | 4.704 | 14.5269 | 7.64322 | Pilar C-30 - Retangular 20x50 | no
P50 | PAVTO 01 | 2.5 | 15 | 25 | 0 | 1.68 % | 0.16 | 0.13 | Interno | 0.1185 | 2.528 | 18.9351 | 3.25023 | Pilar C-30 - Retangular 15x25 | no
P51 | PAVTO 01 | 2.5 | 20 | 30 | 0 | 0.52 % | 0.06 | 0.05 | Interno | 0.1752 | 2.92 | 12.4516 | 3.85721 | Pilar C-30 - Retangular 20x30 | no
P52 | PAVTO 01 | 2.5 | 20 | 45 | 0 | 0.52 % | 0.07 | 0.06 | Interno | 0.243 | 3.51 | 12.3295 | 5.8884 | Pilar C-30 - Retangular 20x45 | no
P53 | PAVTO 01 | 2.5 | 20 | 30 | 0 | 0.52 % | 0.08 | 0.07 | Interno | 0.1992 | 3.32 | 9.90159 | 4.32008 | Pilar C-30 - Retangular 20x30 | no
P54 | PAVTO 01 | 2.5 | 20 | 30 | 0 | 0.52 % | 0.11 | 0.1 | Interno | 0.1896 | 3.16 | 9.46755 | 4.16579 | Pilar C-30 - Retangular 20x30 | no
P55 | PAVTO 01 | 2.5 | 20 | 30 | 0 | 0.52 % | 0.09 | 0.08 | Interno | 0.1896 | 3.16 | 9.46755 | 4.93723 | Pilar C-30 - Retangular 20x30 | no
P56 | PAVTO 01 | 2.5 | 20 | 30 | 0 | 0.52 % | 0.12 | 0.11 | Interno | 0.1896 | 3.16 | 9.46755 | 4.16579 | Pilar C-30 - Retangular 20x30 | no
P57 | PAVTO 01 | 2.5 | 20 | 30 | 0 | 0.52 % | 0.09 | 0.08 | Interno | 0.1896 | 3.16 | 9.46755 | 4.16579 | Pilar C-30 - Retangular 20x30 | no
P58 | PAVTO 01 | 2.5 | 20 | 35 | 0 | 0.45 % | 0.12 | 0.11 | Interno | 0.2212 | 3.476 | 9.46755 | 4.96606 | Pilar C-30 - Retangular 20x35 | no
P59 | PAVTO 01 | 2.5 | 20 | 30 | 0 | 0.52 % | 0.08 | 0.07 | Interno | 0.1896 | 3.16 | 9.46755 | 4.16579 | Pilar C-30 - Retangular 20x30 | no
P6 | PAVTO 01 | 2.5 | 20 | 30 | 0 | 0.52 % | 0.04 | 0.03 | Interno | 0.2016 | 3.36 | 9.03351 | 4.32008 | Pilar C-30 - Retangular 20x30 | no
P7 | PAVTO 01 | 2.5 | 20 | 30 | 0 | 0.79 % | 0.03 | 0.03 | Interno | 0.2016 | 3.36 | 13.5503 | 5.74428 | Pilar C-30 - Retangular 20x30 | no
P8 | PAVTO 01 | 2.5 | 20 | 30 | 0 | 0.52 % | 0.07 | 0.07 | Interno | 0.1896 | 3.16 | 9.46755 | 4.16579 | Pilar C-30 - Retangular 20x30 | no
P9 | PAVTO 01 | 2.5 | 20 | 30 | 0 | 0.52 % | 0.17 | 0.16 | Interno | 0.1896 | 3.16 | 9.46755 | 4.16579 | Pilar C-30 - Retangular 20x30 | no
P1 | PAVTO 02 | 2.5 | 20 | 30 | 0 | 0.52 % | 0.04 | 0.03 | Interno | 0.1812 | 3.02 | 8.11117 | 4.0115 | Pilar C-30 - Retangular 20x30 | no
P10 | PAVTO 02 | 2.5 | 20 | 30 | 0 | 0.52 % | 0.09 | 0.08 | Interno | 0.1812 | 3.02 | 9.08776 | 4.0115 | Pilar C-30 - Retangular 20x30 | no
P11 | PAVTO 02 | 2.5 | 20 | 30 | 0 | 1.31 % | 0.15 | 0.13 | Interno | 0.1812 | 3.02 | 21.2545 | 4.0115 | Pilar C-30 - Retangular 20x30 | no
P12 | PAVTO 02 | 2.5 | 20 | 30 | 0 | 1.05 % | 0.11 | 0.1 | Interno | 0.1812 | 3.02 | 17.1989 | 5.33397 | Pilar C-30 - Retangular 20x30 | no
P13 | PAVTO 02 | 2.5 | 20 | 30 | 0 | 0.79 % | 0.1 | 0.09 | Interno | 0.1812 | 3.02 | 13.1433 | 4.0115 | Pilar C-30 - Retangular 20x30 | no
P14 | PAVTO 02 | 2.5 | 20 | 30 | 0 | 0.52 % | 0.07 | 0.06 | Interno | 0.1812 | 3.02 | 9.08776 | 4.0115 | Pilar C-30 - Retangular 20x30 | no
P15 | PAVTO 02 | 2.5 | 20 | 40 | 91 | 0.59 % | 0.03 | 0.03 | Interno | 0.3144 | 4.716 | 17.3346 | 7.88906 | Pilar C-30 - Retangular 20x40 | no
P16 | PAVTO 02 | 2.5 | 20 | 40 | 91 | 0.59 % | 0.03 | 0.03 | Interno | 0.3144 | 4.716 | 17.3346 | 7.88906 | Pilar C-30 - Retangular 20x40 | no
P17 | PAVTO 02 | 2.5 | 20 | 30 | 0 | 0.52 % | 0.06 | 0.06 | Interno | 0.1812 | 3.02 | 9.08776 | 4.0115 | Pilar C-30 - Retangular 20x30 | no
P18 | PAVTO 02 | 2.5 | 20 | 30 | 0 | 0.79 % | 0.11 | 0.1 | Interno | 0.1812 | 3.02 | 13.6316 | 4.0115 | Pilar C-30 - Retangular 20x30 | no
P19 | PAVTO 02 | 2.5 | 20 | 30 | 0 | 1.83 % | 0.13 | 0.1 | Interno | 0.1812 | 3.02 | 29.3657 | 5.33397 | Pilar C-30 - Retangular 20x30 | no
P2 | PAVTO 02 | 2.5 | 20 | 30 | 0 | 0.79 % | 0.08 | 0.07 | Interno | 0.1812 | 3.02 | 13.1433 | 4.0115 | Pilar C-30 - Retangular 20x30 | no
P20 | PAVTO 02 | 2.5 | 20 | 30 | 0 | 0.52 % | 0.07 | 0.07 | Interno | 0.1812 | 3.02 | 9.08776 | 4.0115 | Pilar C-30 - Retangular 20x30 | no
P22 | PAVTO 02 | 2.5 | 20 | 30 | 0 | 0.52 % | 0.11 | 0.1 | Interno | 0.1812 | 3.02 | 10.9053 | 4.0115 | Pilar C-30 - Retangular 20x30 | no
P23 | PAVTO 02 | 2.5 | 20 | 35 | 0 | 1.35 % | 0.12 | 0.1 | Interno | 0.2114 | 3.322 | 27.2633 | 4.45233 | Pilar C-30 - Retangular 20x35 | no
P24 | PAVTO 02 | 2.5 | 15 | 25 | 0 | 0.84 % | 0.02 | 0.02 | Interno | 0.11325 | 2.416 | 8.11117 | 3.12985 | Pilar C-30 - Retangular 15x25 | no
P25 | PAVTO 02 | 2.5 | 20 | 30 | 0 | 0.79 % | 0.11 | 0.1 | Interno | 0.1812 | 3.02 | 13.6316 | 4.0115 | Pilar C-30 - Retangular 20x30 | no
P26 | PAVTO 02 | 2.5 | 20 | 30 | 0 | 2.09 % | 0.13 | 0.11 | Interno | 0.1812 | 3.02 | 33.4213 | 4.0115 | Pilar C-30 - Retangular 20x30 | no
P27 | PAVTO 02 | 2.5 | 25 | 30 | 0 | 0.84 % | 0.07 | 0.06 | Interno | 0.2265 | 3.322 | 19.9931 | 4.45233 | Pilar C-30 - Retangular 25x30 | no
P28 | PAVTO 02 | 2.5 | 20 | 40 | 0 | 2.45 % | 0.08 | 0.07 | Interno | 0.2416 | 3.624 |  | 6.08846 | Pilar C-30 - Retangular 20x40 | no | AltoQi_Eberick-Itens_associados - Armadura - Aço CA50 - ø 12.5 mm: 58.3245 kg
P29 | PAVTO 02 | 2.5 | 20 | 40 | 0 | 3.07 % | 0.11 | 0.08 | Interno | 0.2416 | 3.624 |  | 6.08846 | Pilar C-30 - Retangular 20x40 | no | AltoQi_Eberick-Itens_associados - Armadura - Aço CA50 - ø 12.5 mm: 71.9519 kg
P3 | PAVTO 02 | 2.5 | 20 | 30 | 0 | 0.79 % | 0.07 | 0.07 | Interno | 0.1812 | 3.02 | 13.6316 | 4.0115 | Pilar C-30 - Retangular 20x30 | no
P30 | PAVTO 02 | 2.5 | 20 | 30 | 0 | 0.52 % | 0.11 | 0.1 | Interno | 0.1812 | 3.02 | 9.08776 | 4.0115 | Pilar C-30 - Retangular 20x30 | no
P31 | PAVTO 02 | 2.5 | 20 | 30 | 0 | 0.52 % | 0.13 | 0.12 | Interno | 0.1812 | 3.02 | 9.08776 | 4.0115 | Pilar C-30 - Retangular 20x30 | no
P32 | PAVTO 02 | 2.5 | 25 | 30 | 0 | 1.47 % | 0.11 | 0.09 | Interno | 0.2265 | 3.322 | 35.4423 | 5.99521 | Pilar C-30 - Retangular 25x30 | no
P33 | PAVTO 02 | 2.5 | 20 | 40 | 0 | 2.45 % | 0.11 | 0.09 | Interno | 0.2416 | 3.624 |  | 8.98773 | Pilar C-30 - Retangular 20x40 | no | AltoQi_Eberick-Itens_associados - Armadura - Aço CA50 - ø 12.5 mm: 58.3245 kg
P34 | PAVTO 02 | 2.5 | 20 | 30 | 0 | 1.23 % | 0.07 | 0.06 | Interno | 0.1812 | 3.02 |  | 3.24006 | Pilar C-30 - Retangular 20x30 | no | AltoQi_Eberick-Itens_associados - Armadura - Aço CA50 - ø 12.5 mm: 20.918 kg
P35 | PAVTO 02 | 2.5 | 20 | 35 | 0 | 1.80 % | 0.13 | 0.1 | Interno | 0.2114 | 3.322 | 37.2598 | 12.0108 | Pilar C-30 - Retangular 20x35 | no
P36 | PAVTO 02 | 2.5 | 15 | 25 | 0 | 0.84 % | 0.08 | 0.07 | Interno | 0.11325 | 2.416 | 8.11117 | 3.12985 | Pilar C-30 - Retangular 15x25 | no
P37 | PAVTO 02 | 2.5 | 20 | 40 | 0 | 0.59 % | 0.09 | 0.08 | Interno | 0.2416 | 3.624 | 13.6316 | 6.21562 | Pilar C-30 - Retangular 20x40 | no
P38 | PAVTO 02 | 2.5 | 15 | 25 | 0 | 0.84 % | 0.13 | 0.11 | Interno | 0.11325 | 2.416 | 9.08776 | 3.12985 | Pilar C-30 - Retangular 15x25 | no
P39 | PAVTO 02 | 2.5 | 15 | 25 | 0 | 0.84 % | 0.12 | 0.1 | Interno | 0.11325 | 2.416 | 9.08776 | 3.12985 | Pilar C-30 - Retangular 15x25 | no
P4 | PAVTO 02 | 2.5 | 20 | 30 | 0 | 0.79 % | 0.08 | 0.07 | Interno | 0.1812 | 3.02 | 13.6316 | 4.0115 | Pilar C-30 - Retangular 20x30 | no
P40 | PAVTO 02 | 2.5 | 20 | 30 | 0 | 1.31 % | 0.11 | 0.09 | Interno | 0.1812 | 3.02 | 22.7194 | 5.33397 | Pilar C-30 - Retangular 20x30 | no
P41 | PAVTO 02 | 2.5 | 20 | 30 | 0 | 0.52 % | 0.12 | 0.11 | Interno | 0.1812 | 3.02 | 9.08776 | 4.0115 | Pilar C-30 - Retangular 20x30 | no
P42 | PAVTO 02 | 2.5 | 20 | 30 | 0 | 0.52 % | 0.08 | 0.07 | Interno | 0.1812 | 3.02 | 9.08776 | 4.78294 | Pilar C-30 - Retangular 20x30 | no
P43 | PAVTO 02 | 2.5 | 20 | 30 | 0 | 0.52 % | 0.08 | 0.08 | Interno | 0.1812 | 3.02 | 9.08776 | 4.0115 | Pilar C-30 - Retangular 20x30 | no
P44 | PAVTO 02 | 2.5 | 20 | 30 | 0 | 0.52 % | 0.07 | 0.07 | Interno | 0.1812 | 3.02 | 9.08776 | 4.0115 | Pilar C-30 - Retangular 20x30 | no
P45 | PAVTO 02 | 2.5 | 20 | 30 | 0 | 0.52 % | 0.1 | 0.09 | Interno | 0.1812 | 3.02 | 9.08776 | 4.0115 | Pilar C-30 - Retangular 20x30 | no
P46 | PAVTO 02 | 2.5 | 20 | 30 | 0 | 0.52 % | 0.08 | 0.07 | Interno | 0.1812 | 3.02 | 9.08776 | 4.0115 | Pilar C-30 - Retangular 20x30 | no
P47 | PAVTO 02 | 2.5 | 20 | 30 | 0 | 0.52 % | 0.08 | 0.08 | Interno | 0.1812 | 3.02 | 9.08776 | 4.0115 | Pilar C-30 - Retangular 20x30 | no
P48 | PAVTO 02 | 2.5 | 15 | 25 | 0 | 0.84 % | 0.1 | 0.09 | Interno | 0.11325 | 2.416 | 9.08776 | 3.12985 | Pilar C-30 - Retangular 15x25 | no
P49 | PAVTO 02 | 2.5 | 20 | 30 | 0 | 0.82 % | 0.1 | 0.09 | Interno | 0.1812 | 3.02 |  | 3.24006 | Pilar C-30 - Retangular 20x30 | no | AltoQi_Eberick-Itens_associados - Armadura - Aço CA50 - ø 12.5 mm: 14.5811 kg
P5 | PAVTO 02 | 2.5 | 20 | 30 | 0 | 0.52 % | 0.04 | 0.03 | Interno | 0.1812 | 3.02 | 9.08776 | 4.0115 | Pilar C-30 - Retangular 20x30 | no
P50 | PAVTO 02 | 2.5 | 15 | 25 | 0 | 1.68 % | 0.06 | 0.05 | Interno | 0.11325 | 2.416 | 16.2223 | 3.12985 | Pilar C-30 - Retangular 15x25 | no
P51 | PAVTO 02 | 2.5 | 20 | 30 | 0 | 1.57 % | 0.03 | 0.02 | Interno | 0.1812 | 3.02 | 24.3335 | 4.0115 | Pilar C-30 - Retangular 20x30 | no
P52 | PAVTO 02 | 2.5 | 20 | 45 | 0 | 0.52 % | 0.04 | 0.04 | Interno | 0.2718 | 3.926 | 13.1433 | 6.65645 | Pilar C-30 - Retangular 20x45 | no
P53 | PAVTO 02 | 2.5 | 20 | 30 | 0 | 0.52 % | 0.05 | 0.05 | Interno | 0.1812 | 3.02 | 9.08776 | 4.0115 | Pilar C-30 - Retangular 20x30 | no
P54 | PAVTO 02 | 2.5 | 20 | 30 | 0 | 0.52 % | 0.07 | 0.07 | Interno | 0.1812 | 3.02 | 9.08776 | 4.0115 | Pilar C-30 - Retangular 20x30 | no
P55 | PAVTO 02 | 2.5 | 20 | 30 | 0 | 0.52 % | 0.06 | 0.05 | Interno | 0.1812 | 3.02 | 9.08776 | 4.0115 | Pilar C-30 - Retangular 20x30 | no
P56 | PAVTO 02 | 2.5 | 20 | 30 | 0 | 0.52 % | 0.08 | 0.07 | Interno | 0.1812 | 3.02 | 9.08776 | 4.0115 | Pilar C-30 - Retangular 20x30 | no
P57 | PAVTO 02 | 2.5 | 20 | 30 | 0 | 0.52 % | 0.06 | 0.05 | Interno | 0.1812 | 3.02 | 9.08776 | 4.0115 | Pilar C-30 - Retangular 20x30 | no
P58 | PAVTO 02 | 2.5 | 20 | 35 | 0 | 0.45 % | 0.08 | 0.07 | Interno | 0.2114 | 3.322 | 9.08776 | 4.45233 | Pilar C-30 - Retangular 20x35 | no
P59 | PAVTO 02 | 2.5 | 20 | 30 | 0 | 0.52 % | 0.06 | 0.05 | Interno | 0.1812 | 3.02 | 9.08776 | 4.0115 | Pilar C-30 - Retangular 20x30 | no
P60 | PAVTO 02 | 2.5 | 15 | 25 | 0 | 1.26 % | 0.02 | 0.01 | Interno | 0.0375 | 0.8 | 5.41197 | 1.08341 | Pilar C-30 - Retangular 15x25 | no
P61 | PAVTO 02 | 2.5 | 15 | 25 | 0 | 1.26 % | 0.02 | 0.02 | Interno | 0.0375 | 0.8 | 5.41197 | 1.08341 | Pilar C-30 - Retangular 15x25 | no
P8 | PAVTO 02 | 2.5 | 20 | 30 | 0 | 0.52 % | 0.05 | 0.04 | Interno | 0.1812 | 3.02 | 9.08776 | 4.0115 | Pilar C-30 - Retangular 20x30 | no
P9 | PAVTO 02 | 2.5 | 20 | 30 | 0 | 0.52 % | 0.12 | 0.11 | Interno | 0.1812 | 3.02 | 9.08776 | 4.0115 | Pilar C-30 - Retangular 20x30 | no
P10 | COB CX DAGUA | 2.5 | 20 | 30 | 0 | 0.52 % | 0.05 | 0.04 | Interno | 0.1956 | 3.26 | 9.73883 | 4.32008 | Pilar C-30 - Retangular 20x30 | no
P11 | COB CX DAGUA | 2.5 | 20 | 30 | 0 | 0.52 % | 0.04 | 0.03 | Interno | 0.1956 | 3.26 | 9.73883 | 4.32008 | Pilar C-30 - Retangular 20x30 | no
P12 | COB CX DAGUA | 2.5 | 20 | 30 | 0 | 0.52 % | 0.05 | 0.04 | Interno | 0.1956 | 3.26 | 9.73883 | 4.32008 | Pilar C-30 - Retangular 20x30 | no
P13 | COB CX DAGUA | 2.5 | 20 | 30 | 0 | 0.52 % | 0.05 | 0.05 | Interno | 0.1956 | 3.26 | 9.73883 | 4.32008 | Pilar C-30 - Retangular 20x30 | no
P14 | COB CX DAGUA | 2.5 | 20 | 30 | 0 | 0.52 % | 0.04 | 0.04 | Interno | 0.1956 | 3.26 | 9.73883 | 4.32008 | Pilar C-30 - Retangular 20x30 | no
P18 | COB CX DAGUA | 2.5 | 20 | 30 | 0 | 0.79 % | 0.05 | 0.05 | Interno | 0.1956 | 3.26 | 14.6082 | 4.32008 | Pilar C-30 - Retangular 20x30 | no
P19 | COB CX DAGUA | 2.5 | 20 | 30 | 0 | 0.52 % | 0.07 | 0.06 | Interno | 0.1956 | 3.26 | 9.73883 | 4.32008 | Pilar C-30 - Retangular 20x30 | no
P2 | COB CX DAGUA | 2.5 | 20 | 30 | -26 | 0.52 % | 0.02 | 0.02 | Interno | 0.18 | 3 | 8.05691 | 3.85721 | Pilar C-30 - Retangular 20x30 | no
P20 | COB CX DAGUA | 2.5 | 20 | 30 | 0 | 0.52 % | 0.03 | 0.02 | Interno | 0.1956 | 3.26 | 8.76223 | 4.32008 | Pilar C-30 - Retangular 20x30 | no
P22 | COB CX DAGUA | 2.5 | 20 | 30 | 0 | 1.05 % | 0.04 | 0.04 | Interno | 0.1956 | 3.26 | 17.5245 | 4.32008 | Pilar C-30 - Retangular 20x30 | no
P23 | COB CX DAGUA | 2.5 | 20 | 35 | 0 | 1.35 % | 0.03 | 0.03 | Interno | 0.2282 | 3.586 | 26.2867 | 4.79481 | Pilar C-30 - Retangular 20x35 | no
P25 | COB CX DAGUA | 2.5 | 20 | 30 | 0 | 0.79 % | 0.05 | 0.05 | Interno | 0.1956 | 3.26 | 14.6082 | 4.32008 | Pilar C-30 - Retangular 20x30 | no
P26 | COB CX DAGUA | 2.5 | 20 | 30 | 0 | 0.52 % | 0.06 | 0.06 | Interno | 0.1956 | 3.26 | 9.73883 | 4.32008 | Pilar C-30 - Retangular 20x30 | no
P27 | COB CX DAGUA | 2.5 | 25 | 30 | 0 | 1.26 % | 0.03 | 0.03 | Interno | 0.2445 | 3.586 | 26.2867 | 4.79481 | Pilar C-30 - Retangular 25x30 | no
P28 | COB CX DAGUA | 2.5 | 20 | 40 | 0 | 2.45 % | 0.02 | 0.02 | Interno | 0.2608 | 3.912 |  | 6.37839 | Pilar C-30 - Retangular 20x40 | no | AltoQi_Eberick-Itens_associados - Armadura - Aço CA50 - ø 12.5 mm: 54.7639 kg
P29 | COB CX DAGUA | 2.5 | 20 | 40 | 0 | 2.76 % | 0.03 | 0.02 | Interno | 0.2608 | 3.912 |  | 7.4974 | Pilar C-30 - Retangular 20x40 | no | AltoQi_Eberick-Itens_associados - Armadura - Aço CA50 - ø 12.5 mm: 61.6094 kg
P3 | COB CX DAGUA | 2.5 | 20 | 30 | -26 | 0.79 % | 0.03 | 0.02 | Interno | 0.18 | 3 | 12.0854 | 3.85721 | Pilar C-30 - Retangular 20x30 | no
P30 | COB CX DAGUA | 2.5 | 20 | 30 | 0 | 0.52 % | 0.05 | 0.05 | Interno | 0.1956 | 3.26 | 9.73883 | 4.32008 | Pilar C-30 - Retangular 20x30 | no
P31 | COB CX DAGUA | 2.5 | 20 | 30 | 0 | 0.52 % | 0.06 | 0.05 | Interno | 0.1956 | 3.26 | 9.73883 | 4.32008 | Pilar C-30 - Retangular 20x30 | no
P32 | COB CX DAGUA | 2.5 | 25 | 30 | 0 | 2.30 % | 0.05 | 0.04 | Interno | 0.2445 | 3.586 | 48.1923 | 8.11795 | Pilar C-30 - Retangular 25x30 | no
P33 | COB CX DAGUA | 2.5 | 20 | 40 | 0 | 2.45 % | 0.03 | 0.02 | Interno | 0.2608 | 3.912 |  | 6.37839 | Pilar C-30 - Retangular 20x40 | no | AltoQi_Eberick-Itens_associados - Armadura - Aço CA50 - ø 12.5 mm: 54.7639 kg
P34 | COB CX DAGUA | 2.5 | 20 | 30 | 0 | 0.52 % | 0.04 | 0.03 | Interno | 0.1956 | 3.26 | 9.73883 | 4.32008 | Pilar C-30 - Retangular 20x30 | no
P35 | COB CX DAGUA | 2.5 | 20 | 35 | 0 | 2.02 % | 0.04 | 0.03 | Interno | 0.2282 | 3.586 | 39.43 | 6.21901 | Pilar C-30 - Retangular 20x35 | no
P37 | COB CX DAGUA | 2.5 | 20 | 40 | 0 | 0.59 % | 0.04 | 0.03 | Interno | 0.2608 | 3.912 | 14.6082 | 6.69375 | Pilar C-30 - Retangular 20x40 | no
P38 | COB CX DAGUA | 2.5 | 15 | 25 | 0 | 0.84 % | 0.07 | 0.06 | Interno | 0.12225 | 2.608 | 9.73883 | 3.37061 | Pilar C-30 - Retangular 15x25 | no
P39 | COB CX DAGUA | 2.5 | 15 | 25 | 0 | 0.84 % | 0.06 | 0.05 | Interno | 0.12225 | 2.608 | 9.73883 | 3.37061 | Pilar C-30 - Retangular 15x25 | no
P4 | COB CX DAGUA | 2.5 | 20 | 30 | -26 | 0.79 % | 0.03 | 0.03 | Interno | 0.18 | 3 | 12.0854 | 3.85721 | Pilar C-30 - Retangular 20x30 | no
P40 | COB CX DAGUA | 2.5 | 20 | 30 | 0 | 1.31 % | 0.04 | 0.03 | Interno | 0.1956 | 3.26 | 21.9056 | 5.74428 | Pilar C-30 - Retangular 20x30 | no
P41 | COB CX DAGUA | 2.5 | 20 | 30 | 0 | 0.52 % | 0.04 | 0.04 | Interno | 0.1956 | 3.26 | 9.73883 | 4.32008 | Pilar C-30 - Retangular 20x30 | no
P42 | COB CX DAGUA | 2.5 | 20 | 30 | 0 | 0.52 % | 0.03 | 0.03 | Interno | 0.1956 | 3.26 | 9.73883 | 4.32008 | Pilar C-30 - Retangular 20x30 | no
P43 | COB CX DAGUA | 2.5 | 20 | 30 | 0 | 0.52 % | 0.04 | 0.04 | Interno | 0.1956 | 3.26 | 9.73883 | 4.32008 | Pilar C-30 - Retangular 20x30 | no
P44 | COB CX DAGUA | 2.5 | 20 | 30 | 0 | 0.52 % | 0.04 | 0.04 | Interno | 0.1956 | 3.26 | 9.73883 | 4.32008 | Pilar C-30 - Retangular 20x30 | no
P45 | COB CX DAGUA | 2.5 | 20 | 30 | 0 | 0.52 % | 0.05 | 0.05 | Interno | 0.1956 | 3.26 | 9.73883 | 4.32008 | Pilar C-30 - Retangular 20x30 | no
P46 | COB CX DAGUA | 2.5 | 20 | 30 | 0 | 0.52 % | 0.04 | 0.03 | Interno | 0.1956 | 3.26 | 9.73883 | 4.32008 | Pilar C-30 - Retangular 20x30 | no
P47 | COB CX DAGUA | 2.5 | 20 | 30 | 0 | 0.52 % | 0.04 | 0.03 | Interno | 0.1956 | 3.26 | 9.73883 | 4.32008 | Pilar C-30 - Retangular 20x30 | no
P48 | COB CX DAGUA | 2.5 | 15 | 25 | 0 | 0.84 % | 0.05 | 0.05 | Interno | 0.12225 | 2.608 | 9.73883 | 3.37061 | Pilar C-30 - Retangular 15x25 | no
P49 | COB CX DAGUA | 2.5 | 20 | 30 | 0 | 0.82 % | 0.05 | 0.05 | Interno | 0.1956 | 3.26 |  | 3.39435 | Pilar C-30 - Retangular 20x30 | no | AltoQi_Eberick-Itens_associados - Armadura - Aço CA50 - ø 12.5 mm: 15.5984 kg
P5 | COB CX DAGUA | 2.5 | 20 | 30 | -26 | 0.52 % | 0.01 | 0.01 | Interno | 0.18 | 3 | 8.05691 | 3.85721 | Pilar C-30 - Retangular 20x30 | no
P52 | COB CX DAGUA | 2.5 | 20 | 30 | 0 | 0.52 % | 0.01 | 0.01 | Interno | 0.1956 | 3.26 | 8.76223 | 4.32008 | Pilar C-30 - Retangular 20x30 | no
P53 | COB CX DAGUA | 2.5 | 20 | 30 | 0 | 0.52 % | 0.02 | 0.02 | Interno | 0.1956 | 3.26 | 8.76223 | 4.32008 | Pilar C-30 - Retangular 20x30 | no
P54 | COB CX DAGUA | 2.5 | 20 | 30 | 0 | 0.52 % | 0.03 | 0.03 | Interno | 0.1956 | 3.26 | 8.76223 | 4.32008 | Pilar C-30 - Retangular 20x30 | no
P55 | COB CX DAGUA | 2.5 | 20 | 30 | 0 | 0.52 % | 0.02 | 0.02 | Interno | 0.1956 | 3.26 | 8.76223 | 4.32008 | Pilar C-30 - Retangular 20x30 | no
P56 | COB CX DAGUA | 2.5 | 20 | 30 | 0 | 0.52 % | 0.03 | 0.03 | Interno | 0.1956 | 3.26 | 8.76223 | 4.32008 | Pilar C-30 - Retangular 20x30 | no
P57 | COB CX DAGUA | 2.5 | 20 | 30 | 0 | 0.52 % | 0.02 | 0.02 | Interno | 0.1956 | 3.26 | 8.76223 | 4.32008 | Pilar C-30 - Retangular 20x30 | no
P58 | COB CX DAGUA | 2.5 | 20 | 35 | 0 | 0.45 % | 0.03 | 0.03 | Interno | 0.2282 | 3.586 | 8.76223 | 4.79481 | Pilar C-30 - Retangular 20x35 | no
P59 | COB CX DAGUA | 2.5 | 20 | 30 | 0 | 0.52 % | 0.03 | 0.02 | Interno | 0.1956 | 3.26 | 8.76223 | 4.32008 | Pilar C-30 - Retangular 20x30 | no
P60 | COB CX DAGUA | 2.5 | 15 | 25 | -50 | 1.26 % | 0.01 | 0.01 | Interno | 0.1035 | 2.208 | 11.1088 | 2.76872 | Pilar C-30 - Retangular 15x25 | no
P61 | COB CX DAGUA | 2.5 | 15 | 25 | 0 | 1.26 % | 0.02 | 0.02 | Interno | 0.12225 | 2.608 | 13.1433 | 3.37061 | Pilar C-30 - Retangular 15x25 | no
P62 | COB CX DAGUA | 2.5 | 15 | 25 | 0 | 2.09 % | 0.01 | 0.01 | Interno | 0.12225 | 2.608 | 21.9056 | 3.37061 | Pilar C-30 - Retangular 15x25 | no
P8 | COB CX DAGUA | 2.5 | 20 | 30 | -41 | 0.52 % | 0.02 | 0.02 | Interno | 0.171 | 2.85 | 8.83683 | 3.70293 | Pilar C-30 - Retangular 20x30 | no
P9 | COB CX DAGUA | 2.5 | 20 | 30 | -41 | 0.52 % | 0.06 | 0.06 | Interno | 0.171 | 2.85 | 8.62659 | 3.70293 | Pilar C-30 - Retangular 20x30 | no
P10 | TELHADO CINE | 2.5 | 20 | 30 | -42 | 0.52 % | 0.04 | 0.04 | Interno | 0.0492 | 0.82 | 3.32992 | 1.08002 | Pilar C-30 - Retangular 20x30 | no
P11 | TELHADO CINE | 2.5 | 20 | 30 | 0 | 0.52 % | 0.01 | 0.01 | Interno | 0.0744 | 1.24 | 3.28245 | 1.69717 | Pilar C-30 - Retangular 20x30 | no
P12 | TELHADO CINE | 2.5 | 20 | 30 | 0 | 0.52 % | 0.02 | 0.02 | Interno | 0.0744 | 1.24 | 3.28245 | 1.69717 | Pilar C-30 - Retangular 20x30 | no
P13 | TELHADO CINE | 2.5 | 20 | 30 | 0 | 0.52 % | 0.02 | 0.02 | Interno | 0.0744 | 1.24 | 3.28245 | 1.69717 | Pilar C-30 - Retangular 20x30 | no
P14 | TELHADO CINE | 2.5 | 20 | 30 | 0 | 0.52 % | 0.03 | 0.02 | Interno | 0.0744 | 1.24 | 3.28245 | 1.69717 | Pilar C-30 - Retangular 20x30 | no
P15 | TELHADO CINE | 2.5 | 20 | 40 | 0 | 0.59 % | 0.02 | 0.02 | Interno | 0.2872 | 4.308 | 14.4862 | 7.17187 | Pilar C-30 - Retangular 20x40 | no
P16 | TELHADO CINE | 2.5 | 20 | 40 | 0 | 0.59 % | 0.02 | 0.02 | Interno | 0.2872 | 4.308 | 14.4862 | 7.17187 | Pilar C-30 - Retangular 20x40 | no
P17 | TELHADO CINE | 2.5 | 20 | 30 | 0 | 0.52 % | 0.03 | 0.03 | Interno | 0.27 | 4.5 | 12.1261 | 5.86296 | Pilar C-30 - Retangular 20x30 | no
P18 | TELHADO CINE | 2.5 | 20 | 30 | -42 | 0.79 % | 0.04 | 0.04 | Interno | 0.0492 | 0.82 | 4.19122 | 1.08002 | Pilar C-30 - Retangular 20x30 | no
P19 | TELHADO CINE | 2.5 | 20 | 30 | -42 | 0.52 % | 0.06 | 0.06 | Interno | 0.0492 | 0.82 | 3.32992 | 1.08002 | Pilar C-30 - Retangular 20x30 | no
P25 | TELHADO CINE | 2.5 | 20 | 30 | -42 | 0.79 % | 0.05 | 0.04 | Interno | 0.0492 | 0.82 | 4.19122 | 1.08002 | Pilar C-30 - Retangular 20x30 | no
P26 | TELHADO CINE | 2.5 | 20 | 30 | -42 | 0.52 % | 0.06 | 0.05 | Interno | 0.0492 | 0.82 | 3.32992 | 1.08002 | Pilar C-30 - Retangular 20x30 | no
P30 | TELHADO CINE | 2.5 | 20 | 30 | -42 | 0.52 % | 0.05 | 0.04 | Interno | 0.0492 | 0.82 | 3.32992 | 1.08002 | Pilar C-30 - Retangular 20x30 | no
P31 | TELHADO CINE | 2.5 | 20 | 30 | -42 | 0.52 % | 0.05 | 0.05 | Interno | 0.0492 | 0.82 | 3.32992 | 1.08002 | Pilar C-30 - Retangular 20x30 | no
P34 | TELHADO CINE | 2.5 | 20 | 30 | -42 | 0.52 % | 0.03 | 0.03 | Interno | 0.0492 | 0.82 | 3.32992 | 1.08002 | Pilar C-30 - Retangular 20x30 | no
P37 | TELHADO CINE | 2.5 | 20 | 40 | -42 | 0.59 % | 0.03 | 0.03 | Interno | 0.0656 | 0.984 | 4.40146 | 1.67344 | Pilar C-30 - Retangular 20x40 | no
P38 | TELHADO CINE | 2.5 | 15 | 25 | -35 | 0.84 % | 0.06 | 0.05 | Interno | 0.033375 | 0.712 | 2.33298 | 0.963032 | Pilar C-30 - Retangular 15x25 | no
P39 | TELHADO CINE | 2.5 | 15 | 25 | -35 | 0.84 % | 0.04 | 0.04 | Interno | 0.033375 | 0.712 | 2.33298 | 0.963032 | Pilar C-30 - Retangular 15x25 | no
P41 | TELHADO CINE | 2.5 | 20 | 30 | 0 | 0.52 % | 0.01 | 0.01 | Interno | 0.0744 | 1.24 | 3.28245 | 1.69717 | Pilar C-30 - Retangular 20x30 | no
P42 | TELHADO CINE | 2.5 | 20 | 30 | 0 | 0.52 % | 0.02 | 0.02 | Interno | 0.0744 | 1.24 | 3.28245 | 1.69717 | Pilar C-30 - Retangular 20x30 | no
P43 | TELHADO CINE | 2.5 | 20 | 30 | 0 | 0.52 % | 0.03 | 0.02 | Interno | 0.0744 | 1.24 | 3.28245 | 1.69717 | Pilar C-30 - Retangular 20x30 | no
P44 | TELHADO CINE | 2.5 | 20 | 30 | 0 | 0.52 % | 0.03 | 0.02 | Interno | 0.0744 | 1.24 | 3.28245 | 1.69717 | Pilar C-30 - Retangular 20x30 | no
P45 | TELHADO CINE | 2.5 | 20 | 30 | 0 | 0.52 % | 0.03 | 0.03 | Interno | 0.0744 | 1.24 | 3.28245 | 1.69717 | Pilar C-30 - Retangular 20x30 | no
P46 | TELHADO CINE | 2.5 | 20 | 30 | 0 | 0.52 % | 0.02 | 0.02 | Interno | 0.0744 | 1.24 | 3.28245 | 1.69717 | Pilar C-30 - Retangular 20x30 | no
P47 | TELHADO CINE | 2.5 | 20 | 30 | -42 | 0.52 % | 0.02 | 0.02 | Interno | 0.0492 | 0.82 | 3.32992 | 1.08002 | Pilar C-30 - Retangular 20x30 | no
P48 | TELHADO CINE | 2.5 | 15 | 25 | -35 | 0.84 % | 0.02 | 0.02 | Interno | 0.033375 | 0.712 | 2.33298 | 0.963032 | Pilar C-30 - Retangular 15x25 | no
P49 | TELHADO CINE | 2.5 | 20 | 30 | -35 | 0.82 % | 0.02 | 0.02 | Interno | 0.0534 | 0.89 |  | 0.925731 | Pilar C-30 - Retangular 20x30 | no | AltoQi_Eberick-Itens_associados - Armadura - Aço CA50 - ø 12.5 mm: 5.95537 kg
P8 | TELHADO CINE | 2.5 | 15 | 25 | 0 | 0.84 % | 0.01 | 0.01 | Interno | 0.061875 | 1.32 | 4.39468 | 1.68531 | Pilar C-30 - Retangular 15x25 | no
P9 | TELHADO CINE | 2.5 | 20 | 30 | 0 | 0.52 % | 0.04 | 0.04 | Interno | 0.099 | 1.65 | 5.37127 | 2.16004 | Pilar C-30 - Retangular 20x30 | no
P10 | TELHADO ANEXO | 2.5 | 15 | 25 | 0 | 0.84 % | 0.02 | 0.02 | Interno | 0.081375 | 1.736 | 5.80532 | 2.2872 | Pilar C-30 - Retangular 15x25 | no
P18 | TELHADO ANEXO | 2.5 | 15 | 25 | 0 | 0.84 % | 0.02 | 0.02 | Interno | 0.081375 | 1.736 | 5.80532 | 2.2872 | Pilar C-30 - Retangular 15x25 | no
P19 | TELHADO ANEXO | 2.5 | 15 | 25 | 0 | 0.84 % | 0.02 | 0.02 | Interno | 0.081375 | 1.736 | 5.80532 | 2.2872 | Pilar C-30 - Retangular 15x25 | no
P25 | TELHADO ANEXO | 2.5 | 15 | 25 | -50 | 0.84 % | 0.02 | 0.02 | Interno | 0.062625 | 1.336 | 4.44893 | 1.68531 | Pilar C-30 - Retangular 15x25 | no
P26 | TELHADO ANEXO | 2.5 | 15 | 25 | 0 | 0.84 % | 0.02 | 0.02 | Interno | 0.081375 | 1.736 | 5.80532 | 2.2872 | Pilar C-30 - Retangular 15x25 | no
P30 | TELHADO ANEXO | 2.5 | 15 | 25 | -50 | 0.84 % | 0.03 | 0.02 | Interno | 0.062625 | 1.336 | 4.44893 | 1.68531 | Pilar C-30 - Retangular 15x25 | no
P31 | TELHADO ANEXO | 2.5 | 15 | 25 | 0 | 0.84 % | 0.02 | 0.01 | Interno | 0.081375 | 1.736 | 5.80532 | 2.2872 | Pilar C-30 - Retangular 15x25 | no
P34 | TELHADO ANEXO | 2.5 | 15 | 25 | 0 | 0.84 % | 0.02 | 0.02 | Interno | 0.081375 | 1.736 | 5.80532 | 2.2872 | Pilar C-30 - Retangular 15x25 | no
P37 | TELHADO ANEXO | 2.5 | 15 | 25 | -50 | 0.84 % | 0.02 | 0.02 | Interno | 0.062625 | 1.336 | 4.44893 | 1.68531 | Pilar C-30 - Retangular 15x25 | no
P47 | TELHADO ANEXO | 2.5 | 15 | 25 | -50 | 0.84 % | 0.01 | 0.01 | Interno | 0.062625 | 1.336 | 4.44893 | 1.68531 | Pilar C-30 - Retangular 15x25 | no
P49 | TELHADO ANEXO | 2.5 | 15 | 25 | 0 | 1.31 % | 0.01 | 0.01 | Interno | 0.07875 | 1.68 |  | 1.68531 | Pilar C-30 - Retangular 15x25 | no | AltoQi_Eberick-Itens_associados - Armadura - Aço CA50 - ø 12.5 mm: 8.7741 kg
P9 | TELHADO ANEXO | 2.5 | 20 | 30 | 0 | 0.52 % | 0.01 | 0.01 | Interno | 0.105 | 1.75 | 4.66596 | 2.31433 | Pilar C-30 - Retangular 20x30 | no

# IfcFooting (59)
PredefinedType: PAD_FOOTING; Material: Concreto
Pset_ConcreteElementGeneral - ConcreteCover: 4.5 cm; ConstructionMethod: InSitu; ExposureClass: 2; StrengthClass: C-30
AltoQi_Eberick_Elemento - Elemento: Sapata
AltoQi_Eberick_Padrão - Cobrimento: 4.5 cm; Classe de concreto: C-30
AltoQi_Eberick-Itens_associados - Status: Dimensionado
Pset_FootingCommon - Reference: Sapata C-30
Name | In | Seção_B (cm) | Seção_H (cm) | Elevação (cm) | Concreto - C-30 - Abatimento 5 cm (m3) | Forma - Estrutura - Concreto (m2) | Armadura - Aço CA50 - ø 8.0 mm (kg)
P10 | FUNDAÇÃO | 110 | 110 | 10 | 0.506125 | 1.32 | 11.4631 | AltoQi_Eberick-Itens_associados - Armadura - Aço CA50 - ø 10.0 mm: 14.9066 kg; Armadura - Aço CA60 - ø 5.0 mm: 1.85146 kg
P59 | FUNDAÇÃO | 105 | 105 | 5 | 0.43125 | 1.26 | 8.14264 | AltoQi_Eberick-Itens_associados - Armadura - Aço CA50 - ø 10.0 mm: 12.3702 kg; Armadura - Aço CA60 - ø 5.0 mm: 0.805352 kg
P1 | TÉRREO | 85 | 95 | 0 | 0.197754 | 0.72 | 5.15642
P11 | TÉRREO | 125 | 135 | 0 | 0.440785 | 1.04 | 14.1151
P12 | TÉRREO | 100 | 110 | 0 | 0.26723 | 0.84 | 8.39004
P13 | TÉRREO | 105 | 150 | 0 | 0.386916 | 1.02 | 10.4691
P14 | TÉRREO | 105 | 135 | 0 | 0.346633 | 0.96 | 9.45344
P15 | TÉRREO | 105 | 135 | -44 | 0.346633 | 0.96 | 8.95864
P16 | TÉRREO | 105 | 135 | -44 | 0.42525 | 1.44 | 9.12357 | AltoQi_Eberick-Itens_associados - Armadura - Aço CA60 - ø 5.0 mm: 4.68461 kg
P17 | TÉRREO | 110 | 140 | -44 | 0.375748 | 1 | 10.9856
P18 | TÉRREO | 120 | 130 | -24 | 0.408297 | 1 | 12.7956
P19 | TÉRREO | 110 | 215 | -24 | 0.970167 | 2.485 | 7.27889 | AltoQi_Eberick-Itens_associados - Armadura - Aço CA50 - ø 10.0 mm: 17.382 kg
P2 | TÉRREO | 105 | 140 | 0 | 0.360071 | 0.98 | 9.62706
P20 | TÉRREO | 100 | 110 | 0 | 0.26723 | 0.84 | 8.39004
P21 | TÉRREO | 65 | 55 | -24 | 0.088526 | 0.48 | 3.59387
P22 | TÉRREO | 115 | 125 | 0 | 0.377059 | 0.96 | 11.7365
P23 | TÉRREO | 115 | 125 | 0 | 0.378736 | 0.96 | 11.7365
P24 | TÉRREO | 55 | 65 | -24 | 0.10725 | 0.72 | 4.58349 | AltoQi_Eberick-Itens_associados - Armadura - Aço CA60 - ø 5.0 mm: 1.69378 kg
P25 | TÉRREO | 115 | 125 | -24 | 0.377059 | 0.96 | 11.7365
P26 | TÉRREO | 115 | 215 | -24 | 1.01259 | 2.51 | 8.14264 | AltoQi_Eberick-Itens_associados - Armadura - Aço CA50 - ø 10.0 mm: 17.382 kg
P27 | TÉRREO | 115 | 120 | 0 | 0.335224 | 0.94 | 10.4214
P28 | TÉRREO | 115 | 130 | 41 | 0.395042 | 0.98 | 11.9535
P29 | TÉRREO | 130 | 150 | 41 | 0.551665 | 1.12 | 16.6412
P3 | TÉRREO | 85 | 115 | 0 | 0.280812 | 1.03 | 5.67727
P30 | TÉRREO | 135 | 145 | -24 | 0.548847 | 1.12 | 16.7714
P31 | TÉRREO | 115 | 200 | -24 | 0.8295 | 2.06 | 7.53498 | AltoQi_Eberick-Itens_associados - Armadura - Aço CA50 - ø 10.0 mm: 14.1064 kg
P32 | TÉRREO | 130 | 135 | 0 | 0.46064 | 1.06 | 14.1151
P33 | TÉRREO | 135 | 155 | 41 | 0.59061 | 1.16 | 17.9173
P34 | TÉRREO | 95 | 160 | -24 | 0.492199 | 1.5 | 12.1315
P35 | TÉRREO | 125 | 140 | 41 | 0.4585 | 1.06 | 14.0934
P36 | TÉRREO | 75 | 85 | -24 | 0.155154 | 0.64 | 4.63557
P37 | TÉRREO | 125 | 145 | -24 | 0.476164 | 1.08 | 14.9137
P38 | TÉRREO | 105 | 110 | -24 | 0.277687 | 0.86 | 8.75898
P39 | TÉRREO | 120 | 185 | -24 | 0.801894 | 1.96 | 8.39872 | AltoQi_Eberick-Itens_associados - Armadura - Aço CA50 - ø 10.0 mm: 14.398 kg
P4 | TÉRREO | 75 | 145 | 0 | 0.334412 | 1.2425 | 8.2034
P40 | TÉRREO | 115 | 125 | 0 | 0.377059 | 0.96 | 11.7365
P41 | TÉRREO | 125 | 135 | 21 | 0.440785 | 1.04 | 13.8546
P42 | TÉRREO | 100 | 110 | -9 | 0.26723 | 0.84 | 8.39004
P43 | TÉRREO | 115 | 145 | -24 | 0.442293 | 1.04 | 13.1428
P44 | TÉRREO | 115 | 145 | -24 | 0.442293 | 1.04 | 13.1428
P45 | TÉRREO | 120 | 150 | -24 | 0.476213 | 1.08 | 14.9137
P46 | TÉRREO | 110 | 140 | -24 | 0.375748 | 1 | 11.5021
P47 | TÉRREO | 125 | 155 | -24 | 0.511384 | 1.12 | 15.9728
P48 | TÉRREO | 105 | 115 | -24 | 0.290093 | 0.88 | 8.75898
P49 | TÉRREO | 115 | 225 | -24 | 1.10934 | 2.7125 | 8.14264 | AltoQi_Eberick-Itens_associados - Armadura - Aço CA50 - ø 10.0 mm: 19.7761 kg
P5 | TÉRREO | 110 | 95 | -44 | 0.306884 | 1.01 | 5.80749
P50 | TÉRREO | 95 | 105 | -24 | 0.240447 | 0.8 | 7.07489
P51 | TÉRREO | 75 | 125 | 0 | 0.249234 | 0.9875 | 6.25889
P52 | TÉRREO | 125 | 170 | 22 | 0.734437 | 1.775 | 7.56102 | AltoQi_Eberick-Itens_associados - Armadura - Aço CA50 - ø 10.0 mm: 12.0718 kg
P53 | TÉRREO | 95 | 175 | -40 | 0.570305 | 1.6925 | 4.06264 | AltoQi_Eberick-Itens_associados - Armadura - Aço CA50 - ø 10.0 mm: 9.92872 kg
P54 | TÉRREO | 105 | 195 | -24 | 0.737233 | 1.98 | 6.43251 | AltoQi_Eberick-Itens_associados - Armadura - Aço CA50 - ø 10.0 mm: 12.3906 kg
P55 | TÉRREO | 90 | 150 | -24 | 0.411217 | 1.335 | 9.64876
P56 | TÉRREO | 85 | 180 | -24 | 0.571799 | 1.865 | 3.15983 | AltoQi_Eberick-Itens_associados - Armadura - Aço CA50 - ø 10.0 mm: 9.39973 kg
P57 | TÉRREO | 90 | 150 | -24 | 0.411217 | 1.335 | 9.64876
P58 | TÉRREO | 105 | 190 | -24 | 0.72416 | 1.94 | 4.94808 | AltoQi_Eberick-Itens_associados - Armadura - Aço CA50 - ø 10.0 mm: 12.0854 kg
P6 | TÉRREO | 70 | 110 | -44 | 0.188831 | 0.83 | 5.15642
P7 | TÉRREO | 60 | 105 | -44 | 0.155481 | 0.765 | 4.76579
P8 | TÉRREO | 80 | 140 | -24 | 0.319949 | 1.16 | 7.49157
P9 | TÉRREO | 115 | 195 | -24 | 0.80966 | 2.02 | 7.53498 | AltoQi_Eberick-Itens_associados - Armadura - Aço CA50 - ø 10.0 mm: 14.1064 kg

# IfcOpeningElement (34)
Material: Concreto
Pset_ConcreteElementGeneral - ConcreteCover: 2.5 cm; ConstructionMethod: InSitu; ExposureClass: 2; StrengthClass: C-30
AltoQi_Eberick_Elemento - Elemento: Viga; Tipo: retangular; Seção_bw: 15 cm
AltoQi_Eberick_Padrão - Ambiente: Interno; Cobrimento: 2.5 cm; Classe de concreto: C-30
AltoQi_Eberick_Cargas - Adicional (G2): 0; Solo (S): 0; Acidental (Q): 0; Água (A): 0; Subpressão (AS): 0
Pset_BeamCommon - IsExternal: no; LoadBearing: yes
Name | In | Seção_h (cm) | Elevação (cm) | Taxa de armadura | Cargas de parede (G2) | Reference
2 x V210 - Abertura 1 | PAVTO 02 | 45 | 0 | 0.30 % | 0 | Viga C-30 - Seção Retangular 15 X 45
V210 - Abertura 1 | PAVTO 02 | 45 | 0 | 0.15 % | 0 | Viga C-30 - Seção Retangular 15 X 45
V210 - Abertura 2 | PAVTO 02 | 45 | 0 | 0.30 % | 0 | Viga C-30 - Seção Retangular 15 X 45
V213 - Abertura 1 | PAVTO 02 | 45 | 0 | 0.23 % | 0 | Viga C-30 - Seção Retangular 15 X 45
2 x V213 - Abertura 1 | PAVTO 02 | 45 | 0 | 0.35 % | 0 | Viga C-30 - Seção Retangular 15 X 45
V213 - Abertura 2 | PAVTO 02 | 45 | 0 | 0.35 % | 0 | Viga C-30 - Seção Retangular 15 X 45
V216 - Abertura 1 | PAVTO 02 | 50 | 0 | 0.82 % | 442.62 | Viga C-30 - Seção Retangular 15 X 50
2 x V216 - Abertura 1 | PAVTO 02 | 50 | 0 | 0.82 % | 544.64 | Viga C-30 - Seção Retangular 15 X 50
V216 - Abertura 1 | PAVTO 02 | 50 | 0 | 0.65 % | 442.62 | Viga C-30 - Seção Retangular 15 X 50
V220 - Abertura 1 | PAVTO 02 | 45 | 0 | 0.35 % | 0 | Viga C-30 - Seção Retangular 15 X 45
V220 - Abertura 1 | PAVTO 02 | 45 | 0 | 0.22 % | 0 | Viga C-30 - Seção Retangular 15 X 45
2 x V220 - Abertura 1 | PAVTO 02 | 45 | 0 | 0.36 % | 0 | Viga C-30 - Seção Retangular 15 X 45
2 x V223 - Abertura 1 | PAVTO 02 | 50 | 0 | 0.20 % | 0 | Viga C-30 - Seção Retangular 15 X 50
2 x V223 - Abertura 1 | PAVTO 02 | 50 | 0 | 0.20 % | 408.48 | Viga C-30 - Seção Retangular 15 X 50
2 x V228 - Abertura 1 | PAVTO 02 | 40 | 0 | 0.17 % | 0 | Viga C-30 - Seção Retangular 15 X 40
3 x V260 - Abertura 1 | PAVTO 02 | 50 | 0 | 0.20 % | 0 | Viga C-30 - Seção Retangular 15 X 50
V260 - Abertura 1 | PAVTO 02 | 50 | 0 | 0.31 % | 0 | Viga C-30 - Seção Retangular 15 X 50
V264 - Abertura 1 | PAVTO 02 | 45 | 0 | 0.55 % | 408.48 | Viga C-30 - Seção Retangular 15 X 45
V264 - Abertura 1 | PAVTO 02 | 45 | 0 | 0.91 % | 408.48 | Viga C-30 - Seção Retangular 15 X 45
2 x V328 - Abertura 1 | COB CX DAGUA | 50 | -26 | 0.20 % | 0 | Viga C-30 - Seção Retangular 15 X 50
2 x V330 - Abertura 1 | COB CX DAGUA | 40 | -26 | 0.17 % | 0 | Viga C-30 - Seção Retangular 15 X 40
2 x V333 - Abertura 1 | COB CX DAGUA | 40 | -26 | 0.17 % | 0 | Viga C-30 - Seção Retangular 15 X 40

# IfcSlab (101)
Material: Concreto
Pset_ConcreteElementGeneral - ConstructionMethod: InSitu; ExposureClass: 2; StrengthClass: C-30
AltoQi_Eberick_Padrão - Classe de concreto: C-30
AltoQi_Eberick-Itens_associados - Status: Dimensionado
AltoQi_Eberick_Cargas - Adicional (G2): 0; Solo (S): 0; Água (A): 0; Subpressão (AS): 0
Pset_SlabCommon - LoadBearing: yes; IsExternal: yes; PitchAngle: 0 rad
Name | In | PredefinedType | ConcreteCover (cm) = Cobrimento (cm) | Elemento | Tipo | Elevação (cm) | Espessura (cm) | Ambiente | Concreto - C-30 - Abatimento 5 cm (m3) | Revestimento (G2) | Acidental (Q) | Reference | Treliça - Aço CA60 - TR 08645 (cm) | Armadura - Aço CA60 - Ø 5.0 mm (kg) | Armadura - Aço CA50 - Ø 10.0 mm (kg) | Armadura - Aço CA50 - Ø 8.0 mm (kg) | Armadura - Aço CA50 - Ø 6.3 mm (kg) | Enchimento - EPS Unidirecional - B8/40/40/4.5
L2 | FUNDO CISTERNA | FLOOR | 3 | Laje de reservatório | Maciça | 0 | 15 | Contato com solo | 1.26378 | 37.5 | 10 | Laje de reservatório C-30 - h=15cm | AltoQi_Eberick-Itens_associados - Armadura - Aço CA50 - ø 6.3 mm: 71.1441 kg; Armadura - Aço CA50 - ø 12.5 mm: 2.36817 kg; Armadura - Aço CA50 - ø 8.0 mm: 40.5144 kg; Armadura - Aço CA50 - ø 10.0 mm: 31.7068 kg; Armadura - Aço CA60 - ø 5.0 mm: 3.51104 kg
L3 | FUNDO CISTERNA | FLOOR | 3 | Laje de reservatório | Maciça | 60 | 15 | Contato com solo | 0.752503 | 136.5 | 5000 | Laje de reservatório C-30 - h=15cm | AltoQi_Eberick-Itens_associados - Armadura - Aço CA50 - ø 6.3 mm: 90.7496 kg; Armadura - Aço CA50 - ø 12.5 mm: 22.1987 kg; Armadura - Aço CA50 - ø 8.0 mm: 44.6958 kg; Armadura - Aço CA50 - ø 10.0 mm: 46.0969 kg; Armadura - Aço CA60 - ø 5.0 mm: 5.40613 kg
L1 | TÉRREO | FLOOR | 3 | Laje de reservatório | Maciça | -40 | 10 | Contato com solo | 0.799887 | 37.5 | 10 | Laje de reservatório C-30 - h=10cm | AltoQi_Eberick-Itens_associados - Armadura - Aço CA50 - ø 6.3 mm: 45.0296 kg; Armadura - Aço CA50 - ø 12.5 mm: 1.4989 kg; Armadura - Aço CA50 - ø 8.0 mm: 25.643 kg; Armadura - Aço CA50 - ø 10.0 mm: 20.0684 kg; Armadura - Aço CA60 - ø 5.0 mm: 2.22226 kg; Forma - Estrutura - Concreto: 8.13387 m2
L101 | PAVTO 01 | FLOOR | 2.5 | Laje | Treliçada 1D | 0 | 12 | Externo | 0.57549 | 81 | 300 | Laje Treliçada 1D - h=12cm | 2319.31 | 9.29865 | 0.963585 | 10.3212 | 4.21178 | 64
L102 | PAVTO 01 | FLOOR | 2.5 | Laje | Treliçada 1D | 0 | 12 | Externo | 0.459369 | 81 | 300 | Laje Treliçada 1D - h=12cm | 1851.33 | 7.42239 | 0.769155 | 8.23864 | 3.36194 | 48
L103 | PAVTO 01 | FLOOR | 2.5 | Laje | Treliçada 1D | 0 | 12 | Externo | 0.451131 | 81 | 300 | Laje Treliçada 1D - h=12cm | 1818.12 | 7.28927 | 0.75536 | 8.09088 | 3.30164 | 42
L104 | PAVTO 01 | FLOOR | 2.5 | Laje | Treliçada 1D | 0 | 12 | Externo | 0.398593 | 81 | 300 | Laje Treliçada 1D - h=12cm | 1606.39 | 6.44039 | 0.667394 | 7.14864 | 2.91714 | 42
L105 | PAVTO 01 | FLOOR | 2.5 | Laje | Treliçada 1D | 0 | 12 | Externo | 0.74983 | 154.5 | 300 | Laje Treliçada 1D - h=12cm | 3021.93 | 12.1156 | 1.25549 | 13.448 | 5.4877 | 80
L106 | PAVTO 01 | FLOOR | 2.5 | Laje | Treliçada 1D | 0 | 12 | Externo | 0.752784 | 154.5 | 300 | Laje Treliçada 1D - h=12cm | 3033.83 | 12.1633 | 1.26044 | 13.5009 | 5.50932 | 80
L107 | PAVTO 01 | FLOOR | 2.5 | Laje | Treliçada 1D | 0 | 12 | Externo | 0.851762 | 154.5 | 300 | Laje Treliçada 1D - h=12cm | 3432.73 | 13.7626 | 1.42617 | 15.2761 | 6.2337 | 100
L108 | PAVTO 01 | FLOOR | 2.5 | Laje | Treliçada 1D | 0 | 12 | Externo | 0.548559 | 154.5 | 300 | Laje Treliçada 1D - h=12cm | 2210.77 | 8.8635 | 0.918491 | 9.83822 | 4.01468 | 60
L109 | PAVTO 01 | FLOOR | 2.5 | Laje | Treliçada 1D | 0 | 12 | Externo | 0.233214 | 154.5 | 300 | Laje Treliçada 1D - h=12cm | 939.889 | 3.76823 | 0.390487 | 4.18262 | 1.7068 | 25
L110 | PAVTO 01 | FLOOR | 2.5 | Laje | Treliçada 1D | 0 | 12 | Externo | 0.220572 | 154.5 | 300 | Laje Treliçada 1D - h=12cm | 888.937 | 3.56395 | 0.369319 | 3.95588 | 1.61427 | 25
L111 | PAVTO 01 | FLOOR | 2.5 | Laje | Treliçada 1D | -2 | 12 | Externo | 0.166652 | 181.5 | 200 | Laje Treliçada 1D - h=12cm | 671.634 | 2.69273 | 0.279038 | 2.98885 | 1.21966 | 15
L112 | PAVTO 01 | FLOOR | 2.5 | Laje | Treliçada 1D | 0 | 12 | Externo | 0.2635 | 154.5 | 300 | Laje Treliçada 1D - h=12cm | 1061.95 | 4.25758 | 0.441197 | 4.72579 | 1.92845 | 30
L113 | PAVTO 01 | FLOOR | 2.5 | Laje | Treliçada 1D | 0 | 12 | Externo | 0.851504 | 181.5 | 200 | Laje Treliçada 1D - h=12cm | 3431.69 | 13.7584 | 1.42573 | 15.2715 | 6.23181 | 83
L114 | PAVTO 01 | FLOOR | 2.5 | Laje | Treliçada 1D | 0 | 12 | Externo | 0.843476 | 154.5 | 300 | Laje Treliçada 1D - h=12cm | 3399.33 | 13.6287 | 1.41229 | 15.1275 | 6.17306 | 96
L115 | PAVTO 01 | FLOOR | 2.5 | Laje | Treliçada 1D | 0 | 12 | Externo | 0.100698 | 154.5 | 300 | Laje Treliçada 1D - h=12cm | 405.83 | 1.62706 | 0.168607 | 1.80599 | 0.73697 | 9
L116 | PAVTO 01 | FLOOR | 2.5 | Laje | Treliçada 1D | 0 | 12 | Externo | 0.536235 | 154.5 | 300 | Laje Treliçada 1D - h=12cm | 2161.11 | 8.66437 | 0.897856 | 9.61719 | 3.92448 | 64
L117 | PAVTO 01 | FLOOR | 2.5 | Laje | Treliçada 1D | 0 | 12 | Externo | 0.657776 | 154.5 | 300 | Laje Treliçada 1D - h=12cm | 2650.93 | 10.6282 | 1.10136 | 11.797 | 4.81399 | 64
L118 | PAVTO 01 | FLOOR | 2.5 | Laje | Treliçada 1D | 0 | 12 | Externo | 0.100698 | 154.5 | 300 | Laje Treliçada 1D - h=12cm | 405.83 | 1.62706 | 0.168607 | 1.80599 | 0.73697 | 9
L119 | PAVTO 01 | FLOOR | 2.5 | Laje | Treliçada 1D | 0 | 12 | Externo | 1.03869 | 154.5 | 300 | Laje Treliçada 1D - h=12cm | 4186.1 | 16.783 | 1.73916 | 18.6286 | 7.60178 | 113
L120 | PAVTO 01 | FLOOR | 2.5 | Laje | Treliçada 1D | 0 | 12 | Externo | 0.089061 | 154.5 | 300 | Laje Treliçada 1D - h=12cm | 358.928 | 1.43902 | 0.149121 | 1.59727 | 0.651799 | 12
L121 | PAVTO 01 | FLOOR | 2.5 | Laje | Treliçada 1D | 0 | 12 | Externo | 0.060402 | 154.5 | 300 | Laje Treliçada 1D - h=12cm | 243.429 | 0.975964 | 0.101136 | 1.08329 | 0.442058 | 8
PAT 1 | PAVTO 01 | LANDING | 2.5 | Patamar de escada | Maciça | 0 | 12 | Externo | 0.313567 | 154.5 | 300 | Patamar de escada C-30 - h=12cm | AltoQi_Eberick-Itens_associados - Armadura - Aço CA50 - ø 6.3 mm: 4.92589 kg; Armadura - Aço CA50 - ø 8.0 mm: 1.48443 kg; Armadura - Aço CA50 - ø 10.0 mm: 5.79854 kg; Armadura - Aço CA60 - ø 5.0 mm: 0.28484 kg; Forma - Estrutura - Concreto: 3.01107 m2
PAT 2 | PAVTO 01 | LANDING | 2.5 | Patamar de escada | Maciça | 17.65 | 12 | Externo | 0.313807 | 154.5 | 300 | Patamar de escada C-30 - h=12cm | AltoQi_Eberick-Itens_associados - Armadura - Aço CA50 - ø 6.3 mm: 6.86394 kg; Armadura - Aço CA50 - ø 8.0 mm: 1.48443 kg; Armadura - Aço CA50 - ø 10.0 mm: 5.79854 kg; Armadura - Aço CA60 - ø 5.0 mm: 1.17497 kg; Forma - Estrutura - Concreto: 3.01546 m2
L201 | PAVTO 02 | FLOOR | 2.5 | Laje | Treliçada 1D | 0 | 12 | Externo | 0.585261 | 154.5 | 250 | Laje Treliçada 1D - h=12cm | 2363.51 | 10.3935 | 1.13651 | 8.13696 | 1.58862 | 64
L202 | PAVTO 02 | FLOOR | 2.5 | Laje | Treliçada 1D | -2 | 12 | Externo | 0.165147 | 181.5 | 200 | Laje Treliçada 1D - h=12cm | 666.925 | 2.9328 | 0.320695 | 2.29606 | 0.44827 | 20
L203 | PAVTO 02 | FLOOR | 2.5 | Laje | Treliçada 1D | -2 | 12 | Externo | 0.202176 | 181.5 | 200 | Laje Treliçada 1D - h=12cm | 816.463 | 3.59039 | 0.392601 | 2.81088 | 0.548782 | 20
L204 | PAVTO 02 | FLOOR | 2.5 | Laje | Treliçada 1D | -2 | 12 | Externo | 0.145293 | 181.5 | 200 | Laje Treliçada 1D - h=12cm | 586.748 | 2.58022 | 0.282141 | 2.02003 | 0.39438 | 16
L205 | PAVTO 02 | FLOOR | 2.5 | Laje | Treliçada 1D | -2 | 12 | Externo | 0.348604 | 181.5 | 200 | Laje Treliçada 1D - h=12cm | 1407.79 | 6.19077 | 0.676946 | 4.84669 | 0.946242 | 35
L206 | PAVTO 02 | FLOOR | 2.5 | Laje | Treliçada 1D | 0 | 12 | Externo | 0.382354 | 181.5 | 200 | Laje Treliçada 1D - h=12cm | 1544.09 | 6.79013 | 0.742484 | 5.31592 | 1.03785 | 42
L207 | PAVTO 02 | FLOOR | 2.5 | Laje | Treliçada 1D | 0 | 12 | Externo | 0.398281 | 154.5 | 250 | Laje Treliçada 1D - h=12cm | 1608.41 | 7.07297 | 0.773412 | 5.53735 | 1.08108 | 42
L208 | PAVTO 02 | FLOOR | 2.5 | Laje | Treliçada 1D | 0 | 12 | Externo | 0.755323 | 154.5 | 250 | Laje Treliçada 1D - h=12cm | 3050.28 | 13.4136 | 1.46674 | 10.5014 | 2.05023 | 80
L209 | PAVTO 02 | FLOOR | 2.5 | Laje | Treliçada 1D | 0 | 12 | Externo | 0.107422 | 81 | 300 | Laje Treliçada 1D - h=12cm | 433.811 | 1.90768 | 0.2086 | 1.4935 | 0.291584 | 12
L210 | PAVTO 02 | FLOOR | 2.5 | Laje | Treliçada 1D | 0 | 12 | Externo | 0.192503 | 81 | 300 | Laje Treliçada 1D - h=12cm | 777.398 | 3.41861 | 0.373816 | 2.67639 | 0.522525 | 24
L211 | PAVTO 02 | FLOOR | 2.5 | Laje | Treliçada 1D | 0 | 12 | Externo | 0.184524 | 81 | 300 | Laje Treliçada 1D - h=12cm | 745.178 | 3.27692 | 0.358323 | 2.56546 | 0.500868 | 18
L212 | PAVTO 02 | FLOOR | 2.5 | Laje | Treliçada 1D | 0 | 12 | Externo | 0.03981 | 81 | 300 | Laje Treliçada 1D - h=12cm | 160.769 | 0.706983 | 0.077307 | 0.553489 | 0.10806 | 4
L213 | PAVTO 02 | FLOOR | 2.5 | Laje | Treliçada 1D | 0 | 12 | Externo | 0.469911 | 154.5 | 300 | Laje Treliçada 1D - h=12cm | 1897.68 | 8.34503 | 0.912508 | 6.53323 | 1.27551 | 48
L214 | PAVTO 02 | FLOOR | 2.5 | Laje | Treliçada 1D | 0 | 12 | Externo | 0.192633 | 81 | 300 | Laje Treliçada 1D - h=12cm | 777.925 | 3.42092 | 0.37407 | 2.6782 | 0.522879 | 24
L215 | PAVTO 02 | FLOOR | 2.5 | Laje | Treliçada 1D | -2 | 12 | Externo | 0.172118 | 181.5 | 200 | Laje Treliçada 1D - h=12cm | 695.077 | 3.0566 | 0.334232 | 2.39298 | 0.467193 | 18
L216 | PAVTO 02 | FLOOR | 2.5 | Laje | Treliçada 1D | 0 | 12 | Externo | 0.747681 | 154.5 | 250 | Laje Treliçada 1D - h=12cm | 3019.42 | 13.2779 | 1.4519 | 10.3951 | 2.02949 | 80
L217 | PAVTO 02 | FLOOR | 2.5 | Laje | Treliçada 1D | 0 | 12 | Externo | 0.199115 | 154.5 | 300 | Laje Treliçada 1D - h=12cm | 804.1 | 3.53603 | 0.386656 | 2.76832 | 0.540472 | 24
L218 | PAVTO 02 | FLOOR | 2.5 | Laje | Treliçada 1D | 0 | 12 | Externo | 0.132204 | 81 | 300 | Laje Treliçada 1D - h=12cm | 533.887 | 2.34777 | 0.256723 | 1.83804 | 0.35885 | 20
L219 | PAVTO 02 | FLOOR | 2.5 | Laje | Treliçada 1D | 0 | 12 | Externo | 0.586043 | 154.5 | 250 | Laje Treliçada 1D - h=12cm | 2366.66 | 10.4074 | 1.13802 | 8.14783 | 1.59074 | 60
L220 | PAVTO 02 | FLOOR | 2.5 | Laje | Treliçada 1D | 0 | 12 | Externo | 0.455255 | 154.5 | 300 | Laje Treliçada 1D - h=12cm | 1838.49 | 8.08476 | 0.884048 | 6.32946 | 1.23573 | 48
L221 | PAVTO 02 | FLOOR | 2.5 | Laje | Treliçada 1D | 0 | 12 | Externo | 0.135839 | 81 | 300 | Laje Treliçada 1D - h=12cm | 548.57 | 2.41233 | 0.263783 | 1.88859 | 0.368719 | 20
L222 | PAVTO 02 | FLOOR | 2.5 | Laje | Treliçada 1D | 0 | 12 | Externo | 0.287116 | 81 | 300 | Laje Treliçada 1D - h=12cm | 1159.48 | 5.09882 | 0.557543 | 3.99181 | 0.77934 | 30
L223 | PAVTO 02 | FLOOR | 2.5 | Laje | Treliçada 1D | 0 | 12 | Externo | 0.851737 | 154.5 | 250 | Laje Treliçada 1D - h=12cm | 3439.63 | 15.1258 | 1.65397 | 11.8418 | 2.31194 | 90
L224 | PAVTO 02 | FLOOR | 2.5 | Laje | Treliçada 1D | 0 | 12 | Externo | 0.382277 | 154.5 | 300 | Laje Treliçada 1D - h=12cm | 1543.78 | 6.78877 | 0.742335 | 5.31485 | 1.03764 | 40
L225 | PAVTO 02 | FLOOR | 2.5 | Laje | Treliçada 1D | 0 | 12 | Externo | 0.156128 | 81 | 300 | Laje Treliçada 1D - h=12cm | 630.504 | 2.77264 | 0.303181 | 2.17067 | 0.42379 | 20
L226 | PAVTO 02 | FLOOR | 2.5 | Laje | Treliçada 1D | 0 | 12 | Externo | 0.474675 | 154.5 | 300 | Laje Treliçada 1D - h=12cm | 1916.92 | 8.42963 | 0.921759 | 6.59947 | 1.28845 | 48
L227 | PAVTO 02 | FLOOR | 2.5 | Laje | Treliçada 1D | 0 | 12 | Externo | 0.19376 | 81 | 300 | Laje Treliçada 1D - h=12cm | 782.476 | 3.44094 | 0.376258 | 2.69387 | 0.525937 | 24
L228 | PAVTO 02 | FLOOR | 2.5 | Laje | Treliçada 1D | -2 | 12 | Externo | 0.166618 | 181.5 | 200 | Laje Treliçada 1D - h=12cm | 672.865 | 2.95892 | 0.323551 | 2.31651 | 0.452263 | 15
L229 | PAVTO 02 | FLOOR | 2.5 | Laje | Treliçada 1D | 0 | 12 | Externo | 0.026719 | 154.5 | 250 | Laje Treliçada 1D - h=12cm | 107.903 | 0.474502 | 0.051886 | 0.371482 | 0.072526 | 2
L230 | PAVTO 02 | FLOOR | 2.5 | Laje | Treliçada 1D | 0 | 12 | Externo | 0.079268 | 154.5 | 250 | Laje Treliçada 1D - h=12cm | 320.114 | 1.4077 | 0.153929 | 1.10207 | 0.215163 | 7
L231 | PAVTO 02 | FLOOR | 2.5 | Laje | Treliçada 1D | 0 | 12 | Externo | 0.376994 | 154.5 | 300 | Laje Treliçada 1D - h=12cm | 1522.44 | 6.69494 | 0.732075 | 5.2414 | 1.0233 | 40
L232 | PAVTO 02 | FLOOR | 2.5 | Laje | Treliçada 1D | 0 | 12 | Externo | 0.154046 | 81 | 300 | Laje Treliçada 1D - h=12cm | 622.097 | 2.73567 | 0.299139 | 2.14172 | 0.418139 | 20
L233 | PAVTO 02 | FLOOR | 2.5 | Laje | Treliçada 1D | 0 | 12 | Externo | 0.334955 | 154.5 | 250 | Laje Treliçada 1D - h=12cm | 1352.67 | 5.94838 | 0.650441 | 4.65692 | 0.909193 | 35
L234 | PAVTO 02 | FLOOR | 2.5 | Laje | Treliçada 1D | 0 | 12 | Externo | 0.263929 | 154.5 | 250 | Laje Treliçada 1D - h=12cm | 1065.84 | 4.68705 | 0.512517 | 3.66944 | 0.716402 | 30
L235 | PAVTO 02 | FLOOR | 2.5 | Laje | Treliçada 1D | 0 | 12 | Externo | 0.031004 | 81 | 300 | Laje Treliçada 1D - h=12cm | 125.205 | 0.55059 | 0.060206 | 0.431051 | 0.084156 | 4
L236 | PAVTO 02 | FLOOR | 2.5 | Laje | Treliçada 1D | 0 | 12 | Externo | 0.549545 | 81 | 300 | Laje Treliçada 1D - h=12cm | 2219.27 | 9.75924 | 1.06715 | 7.6404 | 1.49167 | 55
L237 | PAVTO 02 | FLOOR | 2.5 | Laje | Treliçada 1D | 0 | 12 | Externo | 0.273248 | 81 | 300 | Laje Treliçada 1D - h=12cm | 1103.48 | 4.85255 | 0.530614 | 3.79901 | 0.741699 | 28
L238 | PAVTO 02 | FLOOR | 2.5 | Laje | Treliçada 1D | 0 | 12 | Externo | 0.866463 | 154.5 | 300 | Laje Treliçada 1D - h=12cm | 3499.1 | 15.3873 | 1.68256 | 12.0465 | 2.35191 | 96
L239 | PAVTO 02 | FLOOR | 2.5 | Laje | Treliçada 1D | 0 | 12 | Externo | 0.100683 | 154.5 | 300 | Laje Treliçada 1D - h=12cm | 406.596 | 1.78801 | 0.195514 | 1.39981 | 0.273292 | 9
L240 | PAVTO 02 | FLOOR | 2.5 | Laje | Treliçada 1D | 0 | 12 | Externo | 0.562042 | 154.5 | 300 | Laje Treliçada 1D - h=12cm | 2269.74 | 9.98117 | 1.09142 | 7.81415 | 1.52559 | 64
L241 | PAVTO 02 | FLOOR | 2.5 | Laje | Treliçada 1D | 0 | 12 | Externo | 0.657676 | 154.5 | 300 | Laje Treliçada 1D - h=12cm | 2655.94 | 11.6795 | 1.27712 | 9.14375 | 1.78518 | 64
L242 | PAVTO 02 | FLOOR | 2.5 | Laje | Treliçada 1D | 0 | 12 | Externo | 0.100683 | 154.5 | 300 | Laje Treliçada 1D - h=12cm | 406.596 | 1.78801 | 0.195514 | 1.39981 | 0.273292 | 9
L243 | PAVTO 02 | FLOOR | 2.5 | Laje | Treliçada 1D | 0 | 12 | Externo | 1.04105 | 154.5 | 300 | Laje Treliçada 1D - h=12cm | 4204.13 | 18.4877 | 2.02158 | 14.4738 | 2.82579 | 113
L244 | PAVTO 02 | FLOOR | 2.5 | Laje | Treliçada 1D | 0 | 12 | Externo | 0.114992 | 154.5 | 300 | Laje Treliçada 1D - h=12cm | 464.381 | 2.04212 | 0.2233 | 1.59875 | 0.312132 | 16
L245 | PAVTO 02 | FLOOR | 2.5 | Laje | Treliçada 1D | 0 | 12 | Externo | 0.060393 | 154.5 | 300 | Laje Treliçada 1D - h=12cm | 243.889 | 1.0725 | 0.117275 | 0.83965 | 0.163929 | 8
L246 | PAVTO 02 | FLOOR | 2.5 | Laje | Treliçada 1D | 0 | 12 | Externo | 0.320893 | 154.5 | 250 | Laje Treliçada 1D - h=12cm | 1295.89 | 5.69866 | 0.623134 | 4.46141 | 0.871024 | 36
L247 | PAVTO 02 | FLOOR | 2.5 | Laje | Treliçada 1D | 0 | 12 | Externo | 0.22828 | 154.5 | 250 | Laje Treliçada 1D - h=12cm | 921.882 | 4.05397 | 0.443292 | 3.17381 | 0.619638 | 28
L248 | PAVTO 02 | FLOOR | 2.5 | Laje | Treliçada 1D | 0 | 12 | Externo | 0.22145 | 154.5 | 250 | Laje Treliçada 1D - h=12cm | 894.298 | 3.93267 | 0.430028 | 3.07884 | 0.601098 | 28
L249 | PAVTO 02 | FLOOR | 2.5 | Laje | Treliçada 1D | 0 | 12 | Externo | 0.262858 | 154.5 | 250 | Laje Treliçada 1D - h=12cm | 1061.52 | 4.66803 | 0.510438 | 3.65455 | 0.713495 | 28
L250 | PAVTO 02 | FLOOR | 2.5 | Laje | Treliçada 1D | 0 | 12 | Externo | 0.263022 | 154.5 | 250 | Laje Treliçada 1D - h=12cm | 1062.18 | 4.67094 | 0.510755 | 3.65682 | 0.713939 | 28
PAT 1 | PAVTO 02 | LANDING | 2.5 | Patamar de escada | Maciça | 0 | 12 | Externo | 0.658175 | 154.5 | 300 | Patamar de escada C-30 - h=12cm | AltoQi_Eberick-Itens_associados - Armadura - Aço CA50 - ø 6.3 mm: 16.3416 kg; Armadura - Aço CA50 - ø 8.0 mm: 2.96885 kg; Armadura - Aço CA50 - ø 10.0 mm: 1.23431 kg; Armadura - Aço CA60 - ø 5.0 mm: 3.05186 kg; Forma - Estrutura - Concreto: 6.28321 m2
L301 | COB CX DAGUA | FLOOR | 2.5 | Laje | Treliçada 1D | -26 | 12 | Externo | 0.582286 | 37.5 | 10 | Laje Treliçada 1D - h=12cm | 792.477 | 10.3659 | 3.95654 | 2.79029 | 0.299079 | 64 | AltoQi_Eberick-Itens_associados - Forma - Estrutura - Concreto: 0.640765 m2; Treliça - Aço CA60 - TR 12645: 1080.86 cm; Armadura - Aço CA50 - Ø 12.5 mm: 1.97409 kg
L302 | COB CX DAGUA | FLOOR | 2.5 | Laje | Treliçada 1D | -26 | 12 | Externo | 0.559168 | 37.5 | 10 | Laje Treliçada 1D - h=12cm | 761.013 | 9.9543 | 3.79945 | 2.67951 | 0.287205 | 48 | AltoQi_Eberick-Itens_associados - Forma - Estrutura - Concreto: 0.615325 m2; Treliça - Aço CA60 - TR 12645: 1037.95 cm; Armadura - Aço CA50 - Ø 12.5 mm: 1.89571 kg
L303 | COB CX DAGUA | FLOOR | 2.5 | Laje | Maciça | -26 | 10 | Externo | 0.757602 | 37.5 | 10 | Laje Maciça - h=10cm | 1031.08 | 13.4868 | 5.14778 | 3.63041 | 0.389127 | AltoQi_Eberick-Itens_associados - Forma - Estrutura - Concreto: 0.833689 m2; Treliça - Aço CA60 - TR 12645: 1406.29 cm; Armadura - Aço CA50 - Ø 12.5 mm: 2.56846 kg
L304 | COB CX DAGUA | FLOOR | 2.5 | Laje | Treliçada 1D | -41 | 12 | Externo | 0.382741 | 37.5 | 10 | Laje Treliçada 1D - h=12cm | 520.901 | 6.81356 | 2.60066 | 1.83408 | 0.196587 | 42 | AltoQi_Eberick-Itens_associados - Forma - Estrutura - Concreto: 0.42118 m2; Treliça - Aço CA60 - TR 12645: 710.459 cm; Armadura - Aço CA50 - Ø 12.5 mm: 1.29758 kg
L305 | COB CX DAGUA | FLOOR | 2.5 | Laje | Treliçada 1D | 0 | 16 | Externo | 0.389757 | 37.5 | 50 | Laje Treliçada 1D - h=16cm | 530.45 | 6.93846 | 2.64834 | 1.8677 | 0.200191 | AltoQi_Eberick-Itens_associados - Forma - Estrutura - Concreto: 0.428901 m2; Treliça - Aço CA60 - TR 12645: 723.484 cm; Armadura - Aço CA50 - Ø 12.5 mm: 1.32137 kg; Enchimento - EPS Unidirecional - B12/40/40: 36
L306 | COB CX DAGUA | FLOOR | 2.5 | Laje | Treliçada 1D | 0 | 16 | Externo | 0.378561 | 37.5 | 50 | Laje Treliçada 1D - h=16cm | 515.212 | 6.73914 | 2.57226 | 1.81405 | 0.19444 | AltoQi_Eberick-Itens_associados - Forma - Estrutura - Concreto: 0.41658 m2; Treliça - Aço CA60 - TR 12645: 702.7 cm; Armadura - Aço CA50 - Ø 12.5 mm: 1.28341 kg; Enchimento - EPS Unidirecional - B12/40/40: 36
L307 | COB CX DAGUA | FLOOR | 2.5 | Laje | Treliçada 1D | 0 | 16 | Externo | 0.274789 | 37.5 | 50 | Laje Treliçada 1D - h=16cm | 373.982 | 4.8918 | 1.86715 | 1.31678 | 0.14114 | AltoQi_Eberick-Itens_associados - Forma - Estrutura - Concreto: 0.302387 m2; Treliça - Aço CA60 - TR 12645: 510.075 cm; Armadura - Aço CA50 - Ø 12.5 mm: 0.931603 kg; Enchimento - EPS Unidirecional - B12/40/40: 30
L308 | COB CX DAGUA | FLOOR | 2.5 | Laje | Treliçada 1D | 0 | 16 | Externo | 0.267595 | 37.5 | 50 | Laje Treliçada 1D - h=16cm | 364.19 | 4.76373 | 1.81826 | 1.28231 | 0.137445 | AltoQi_Eberick-Itens_associados - Forma - Estrutura - Concreto: 0.29447 m2; Treliça - Aço CA60 - TR 12645: 496.721 cm; Armadura - Aço CA50 - Ø 12.5 mm: 0.907212 kg; Enchimento - EPS Unidirecional - B12/40/40: 30
L309 | COB CX DAGUA | FLOOR | 2.5 | Laje | Treliçada 1D | 0 | 16 | Externo | 0.279634 | 37.5 | 50 | Laje Treliçada 1D - h=16cm | 380.574 | 4.97804 | 1.90006 | 1.33999 | 0.143628 | AltoQi_Eberick-Itens_associados - Forma - Estrutura - Concreto: 0.307717 m2; Treliça - Aço CA60 - TR 12645: 519.067 cm; Armadura - Aço CA50 - Ø 12.5 mm: 0.948026 kg; Enchimento - EPS Unidirecional - B12/40/40: 30
L310 | COB CX DAGUA | FLOOR | 2.5 | Laje | Treliçada 1D | 0 | 16 | Externo | 0.271322 | 37.5 | 50 | Laje Treliçada 1D - h=16cm | 369.263 | 4.83008 | 1.84359 | 1.30017 | 0.139359 | AltoQi_Eberick-Itens_associados - Forma - Estrutura - Concreto: 0.298571 m2; Treliça - Aço CA60 - TR 12645: 503.639 cm; Armadura - Aço CA50 - Ø 12.5 mm: 0.919848 kg; Enchimento - EPS Unidirecional - B12/40/40: 30
L311 | COB CX DAGUA | FLOOR | 2.5 | Laje | Treliçada 1D | 0 | 16 | Externo | 0.325607 | 37.5 | 50 | Laje Treliçada 1D - h=16cm | 443.144 | 5.79646 | 2.21245 | 1.5603 | 0.167242 | AltoQi_Eberick-Itens_associados - Forma - Estrutura - Concreto: 0.358308 m2; Treliça - Aço CA60 - TR 12645: 604.406 cm; Armadura - Aço CA50 - Ø 12.5 mm: 1.10389 kg; Enchimento - EPS Unidirecional - B12/40/40: 30
L312 | COB CX DAGUA | FLOOR | 2.5 | Laje | Treliçada 1D | 0 | 16 | Externo | 0.315234 | 37.5 | 50 | Laje Treliçada 1D - h=16cm | 429.025 | 5.61179 | 2.14196 | 1.51059 | 0.161913 | AltoQi_Eberick-Itens_associados - Forma - Estrutura - Concreto: 0.346893 m2; Treliça - Aço CA60 - TR 12645: 585.15 cm; Armadura - Aço CA50 - Ø 12.5 mm: 1.06872 kg; Enchimento - EPS Unidirecional - B12/40/40: 30
L313 | COB CX DAGUA | FLOOR | 2.5 | Laje | Treliçada 1D | 0 | 16 | Externo | 0.414801 | 37.5 | 50 | Laje Treliçada 1D - h=16cm | 564.534 | 7.3843 | 2.81851 | 1.98771 | 0.213054 | AltoQi_Eberick-Itens_associados - Forma - Estrutura - Concreto: 0.45646 m2; Treliça - Aço CA60 - TR 12645: 769.971 cm; Armadura - Aço CA50 - Ø 12.5 mm: 1.40628 kg; Enchimento - EPS Unidirecional - B12/40/40: 42
L314 | COB CX DAGUA | FLOOR | 2.5 | Laje | Treliçada 1D | 0 | 16 | Externo | 0.401241 | 37.5 | 50 | Laje Treliçada 1D - h=16cm | 546.079 | 7.1429 | 2.72637 | 1.92273 | 0.206089 | AltoQi_Eberick-Itens_associados - Forma - Estrutura - Concreto: 0.441538 m2; Treliça - Aço CA60 - TR 12645: 744.8 cm; Armadura - Aço CA50 - Ø 12.5 mm: 1.36031 kg; Enchimento - EPS Unidirecional - B12/40/40: 42
L315 | COB CX DAGUA | FLOOR | 2.5 | Laje | Treliçada 1D | 0 | 16 | Externo | 0.296552 | 37.5 | 50 | Laje Treliçada 1D - h=16cm | 403.6 | 5.27922 | 2.01502 | 1.42107 | 0.152318 | AltoQi_Eberick-Itens_associados - Forma - Estrutura - Concreto: 0.326335 m2; Treliça - Aço CA60 - TR 12645: 550.472 cm; Armadura - Aço CA50 - Ø 12.5 mm: 1.00538 kg; Enchimento - EPS Unidirecional - B12/40/40: 30
L316 | COB CX DAGUA | FLOOR | 2.5 | Laje | Treliçada 1D | 0 | 16 | Externo | 0.286692 | 37.5 | 50 | Laje Treliçada 1D - h=16cm | 390.181 | 5.10369 | 1.94802 | 1.37382 | 0.147253 | AltoQi_Eberick-Itens_associados - Forma - Estrutura - Concreto: 0.315484 m2; Treliça - Aço CA60 - TR 12645: 532.169 cm; Armadura - Aço CA50 - Ø 12.5 mm: 0.971955 kg; Enchimento - EPS Unidirecional - B12/40/40: 30
L317 | COB CX DAGUA | FLOOR | 2.5 | Laje | Treliçada 1D | 0 | 12 | Externo | 0.786418 | 37.5 | 10 | Laje Treliçada 1D - h=12cm | 1070.3 | 13.9998 | 5.34358 | 3.76849 | 0.403928 | 80 | AltoQi_Eberick-Itens_associados - Forma - Estrutura - Concreto: 0.865399 m2; Treliça - Aço CA60 - TR 12645: 1459.78 cm; Armadura - Aço CA50 - Ø 12.5 mm: 2.66615 kg
L401 | TELHADO CINE | FLOOR | 2.5 | Laje | Treliçada 1D | -42 | 12 | Externo | 0.755343 | 37.5 | 10 | Laje Treliçada 1D - h=12cm | 2191.69 | 11.5296 | 3.60621 | 5.12542 | 2.74686 | 80 | AltoQi_Eberick-Itens_associados - Forma - Estrutura - Concreto: 2.00515 m2
L402 | TELHADO CINE | FLOOR | 2.5 | Laje | Treliçada 1D | -42 | 12 | Externo | 0.747135 | 37.5 | 10 | Laje Treliçada 1D - h=12cm | 2167.87 | 11.4043 | 3.56702 | 5.06972 | 2.71701 | 80 | AltoQi_Eberick-Itens_associados - Forma - Estrutura - Concreto: 1.98336 m2
L403 | TELHADO CINE | FLOOR | 2.5 | Laje | Treliçada 1D | -42 | 12 | Externo | 0.85181 | 37.5 | 10 | Laje Treliçada 1D - h=12cm | 2471.6 | 13.0021 | 4.06677 | 5.78 | 3.09767 | 100 | AltoQi_Eberick-Itens_associados - Forma - Estrutura - Concreto: 2.26124 m2
L404 | TELHADO CINE | FLOOR | 2.5 | Laje | Treliçada 1D | -42 | 12 | Externo | 0.861683 | 37.5 | 10 | Laje Treliçada 1D - h=12cm | 2500.24 | 13.1528 | 4.1139 | 5.847 | 3.13357 | 100 | AltoQi_Eberick-Itens_associados - Forma - Estrutura - Concreto: 2.28745 m2
L405 | TELHADO CINE | FLOOR | 2.5 | Laje | Maciça | -42 | 10 | Externo | 0.706822 | 37.5 | 10 | Laje Maciça - h=10cm | 2050.9 | 10.789 | 3.37456 | 4.79618 | 2.57041 | AltoQi_Eberick-Itens_associados - Forma - Estrutura - Concreto: 1.87635 m2
L406 | TELHADO CINE | FLOOR | 2.5 | Laje | Treliçada 1D | -42 | 12 | Externo | 0.072658 | 37.5 | 10 | Laje Treliçada 1D - h=12cm | 210.822 | 1.10905 | 0.346887 | 0.493023 | 0.264225 | 10 | AltoQi_Eberick-Itens_associados - Forma - Estrutura - Concreto: 0.192879 m2
L407 | TELHADO CINE | FLOOR | 2.5 | Laje | Maciça | -35 | 10 | Externo | 0.434549 | 136.5 | 300 | Laje Maciça - h=10cm | 1260.88 | 6.63301 | 2.07465 | 2.94866 | 1.58027 | AltoQi_Eberick-Itens_associados - Forma - Estrutura - Concreto: 1.15357 m2

# IfcStairFlight (4)
NumberOfRisers: 0; NumberOfTreads: 0; Material: Concreto
Pset_ConcreteElementGeneral - ConcreteCover: 2.5 cm; ConstructionMethod: InSitu; ExposureClass: 2; StrengthClass: C-30
AltoQi_Eberick_Elemento - Elemento: Escada; Tipo: Fundo plano; Espessura: 12 cm; Piso: 28 cm; Primeira_face: 0 cm
AltoQi_Eberick_Padrão - Ambiente: Externo; Cobrimento: 2.5 cm; Classe de concreto: C-30
AltoQi_Eberick-Itens_associados - Status: Dimensionado
AltoQi_Eberick_Cargas - Adicional (G2): 0; Solo (S): 0; Acidental (Q): 300; Água (A): 0; Subpressão (AS): 0
Pset_StairFlightCommon - Reference: Lance de escada C-30 - Fundo plano - h= 12cm; TreadLength: 28 cm; WaistThickness: 12 cm
Name | In | Espelho (cm) = RiserHeight (cm) | Concreto - C-30 - Abatimento 5 cm (m3) | Forma - Estrutura - Concreto (m2) | Armadura - Aço CA50 - ø 6.3 mm (kg) | Armadura - Aço CA50 - ø 8.0 mm (kg) | Armadura - Aço CA50 - ø 10.0 mm (kg) | Revestimento (G2)
LE1 | PAVTO 01 | 17.55 | 0.732318 | 7.18143 | 12.5112 | 23.4947 | 5.79854 | 169
LE2 | PAVTO 01 | 17.55 | 0.892709 | 8.77557 | 34.3062 | 22.5832 | 5.79854 | 169
LE1 | PAVTO 02 | 17.75 | 0.761966 | 7.50226 | 12.7723 | 13.5551 |  | 170
LE2 | PAVTO 02 | 17.75 | 0.878966 | 8.61527 | 22.1773 | 28.8031 | 1.11223 | 170

# IfcWall (11)
In: TÉRREO
PredefinedType: SHEAR; Material: Concreto
Pset_ConcreteElementGeneral - ConcreteCover: 3 cm; ConstructionMethod: InSitu; ExposureClass: 2; StrengthClass: C-30
AltoQi_Eberick-Itens_associados - Status: Dimensionado
Pset_WallCommon - Reference: Parede de Reservatório C-30 - e=15cm; LoadBearing: yes
Name | Elemento | Concreto - C-30 - Abatimento 5 cm (m3) | Forma - Estrutura - Concreto (m2) | Armadura - Aço CA50 - ø 6.3 mm (kg) | Armadura - Aço CA50 - ø 8.0 mm (kg) | Armadura - Aço CA50 - ø 10.0 mm (kg) | Armadura - Aço CA50 - ø 12.5 mm (kg) | Armadura - Aço CA60 - ø 5.0 mm (kg)
PAR1-A | PAR1-A | 0.612982 | 8.54686 | 34.5077 | 19.6511 | 15.3791 | 1.14866 | 1.703
PAR1-B | PAR1-B | 0.71636 | 9.98828 | 40.3274 | 22.9652 | 17.9727 | 1.34238 | 1.99021
PAR2-A | PAR2-A | 0.125866 | 1.75496 | 7.08562 | 4.03505 | 3.15785 | 0.235859 | 0.349684
PAR2-B | PAR2-B | 0.12555 | 1.75056 | 7.06782 | 4.02491 | 3.14992 | 0.235266 | 0.348805
PAR3-A | PAR3-A | 0.12555 | 1.75056 | 7.06782 | 4.02491 | 3.14992 | 0.235266 | 0.348805
PAR3-B | PAR3-B | 1.20379 | 16.7846 | 67.7673 | 38.5914 | 30.2019 | 2.25577 | 3.3444
PAR4 | PAR4 | 0.251416 | 3.50552 | 14.1534 | 8.05996 | 6.30777 | 0.471125 | 0.698489
PAR5 | PAR5 | 0.130691 | 1.85145 | 15.7609 | 7.76253 | 8.00586 | 3.85535 | 0.938907
PAR6 | PAR6 | 0.127429 | 1.80525 | 15.3676 | 7.5688 | 7.80606 | 3.75914 | 0.915475
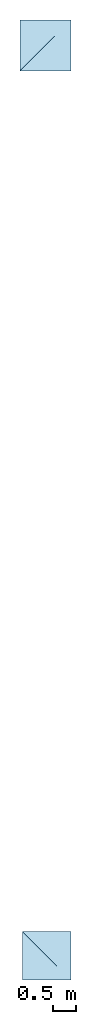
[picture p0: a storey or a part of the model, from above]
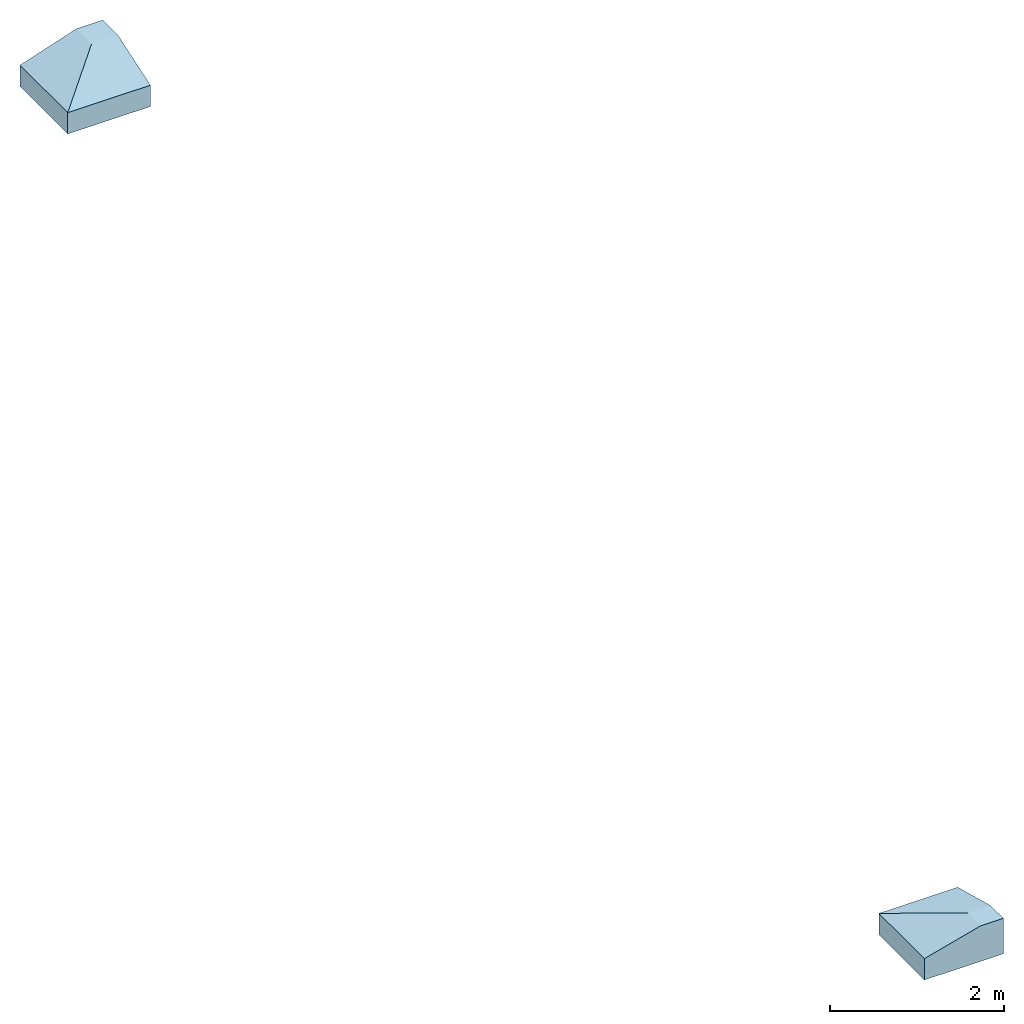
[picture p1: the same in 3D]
Properties of the parts of a building model (IFC4), part 4 of 4

# IfcWall (11)
Name | Elemento | Concreto - C-30 - Abatimento 5 cm (m3) | Forma - Estrutura - Concreto (m2) | Armadura - Aço CA50 - ø 6.3 mm (kg) | Armadura - Aço CA50 - ø 8.0 mm (kg) | Armadura - Aço CA50 - ø 10.0 mm (kg) | Armadura - Aço CA50 - ø 12.5 mm (kg) | Armadura - Aço CA60 - ø 5.0 mm (kg)
PAR7 | PAR7 | 0.130691 | 1.85145 | 15.7609 | 7.76253 | 8.00586 | 3.85535 | 0.938907
PAR8 | PAR8 | 0.127429 | 1.80525 | 15.3676 | 7.5688 | 7.80606 | 3.75914 | 0.915475
